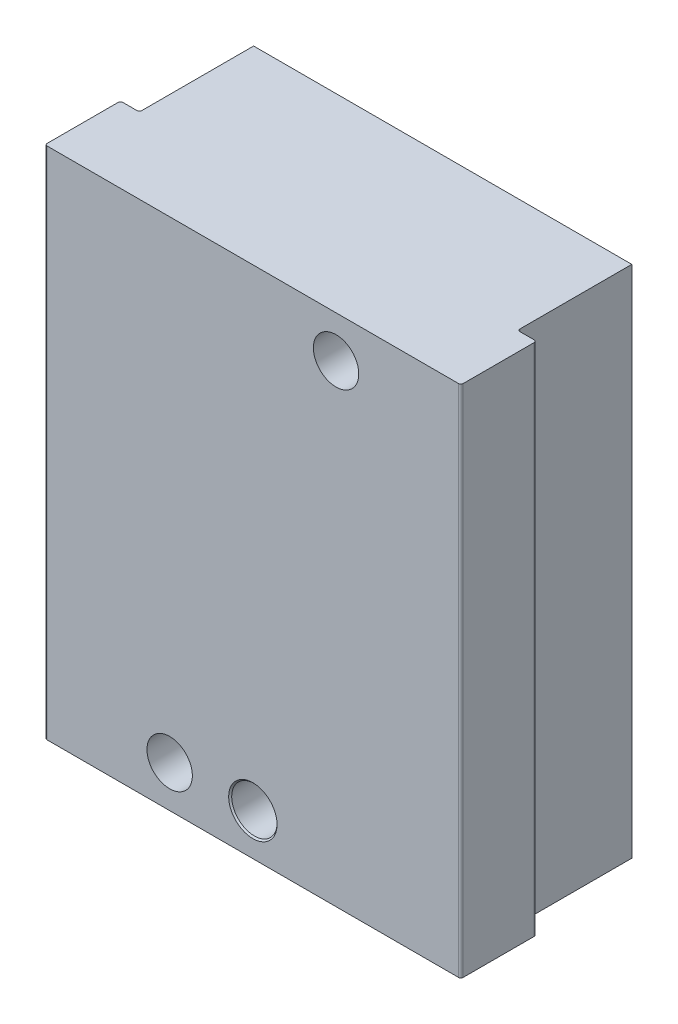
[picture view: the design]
ISO-10303-21;
HEADER;
FILE_DESCRIPTION(('STEP AP214'),'2;1');
FILE_NAME('part.step','',(''),(''),'','','');
FILE_SCHEMA(('AUTOMOTIVE_DESIGN { 1 0 10303 214 1 1 1 1 }'));
ENDSEC;
DATA;
#1=APPLICATION_CONTEXT('core data for automotive mechanical design processes');
#2=APPLICATION_PROTOCOL_DEFINITION('international standard','automotive_design',2000,#1);
#3=PRODUCT_CONTEXT('',#1,'mechanical');
#4=PRODUCT('Part','Part','',(#3));
#5=PRODUCT_RELATED_PRODUCT_CATEGORY('part','',(#4));
#6=PRODUCT_DEFINITION_FORMATION('','',#4);
#7=PRODUCT_DEFINITION_CONTEXT('part definition',#1,'design');
#8=PRODUCT_DEFINITION('design','',#6,#7);
#9=PRODUCT_DEFINITION_SHAPE('','',#8);
#10=(LENGTH_UNIT() NAMED_UNIT(*) SI_UNIT(.MILLI.,.METRE.));
#11=(NAMED_UNIT(*) PLANE_ANGLE_UNIT() SI_UNIT($,.RADIAN.));
#12=(NAMED_UNIT(*) SI_UNIT($,.STERADIAN.) SOLID_ANGLE_UNIT());
#13=UNCERTAINTY_MEASURE_WITH_UNIT(LENGTH_MEASURE(1.E-05),#10,'distance_accuracy_value','');
#14=(GEOMETRIC_REPRESENTATION_CONTEXT(3) GLOBAL_UNCERTAINTY_ASSIGNED_CONTEXT((#13)) GLOBAL_UNIT_ASSIGNED_CONTEXT((#10,
#11,#12)) REPRESENTATION_CONTEXT('',''));
#15=CARTESIAN_POINT('',(0.,0.,0.));
#16=DIRECTION('',(0.,0.,1.));
#17=DIRECTION('',(1.,0.,0.));
#18=AXIS2_PLACEMENT_3D('',#15,#16,#17);
#19=CARTESIAN_POINT('',(-27.0049800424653,-47.5378154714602,-43.689241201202));
#20=DIRECTION('',(0.,0.,-1.));
#21=DIRECTION('',(-1.,0.,0.));
#22=AXIS2_PLACEMENT_3D('',#19,#20,#21);
#23=CYLINDRICAL_SURFACE('',#22,1.5);
#24=CARTESIAN_POINT('',(-28.4999146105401,-47.4146463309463,-66.789241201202));
#25=CARTESIAN_POINT('',(-28.4972110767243,-47.3817342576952,-66.7892330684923));
#26=CARTESIAN_POINT('',(-28.4934051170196,-47.3489165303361,-66.7903240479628));
#27=CARTESIAN_POINT('',(-28.483673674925,-47.2837622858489,-66.7946785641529));
#28=CARTESIAN_POINT('',(-28.477749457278,-47.2514254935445,-66.7979408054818));
#29=CARTESIAN_POINT('',(-28.4639196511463,-47.1877447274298,-66.8065771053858));
#30=CARTESIAN_POINT('',(-28.4560305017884,-47.1563948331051,-66.8119338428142));
#31=CARTESIAN_POINT('',(-28.4383822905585,-47.0946558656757,-66.8246760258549));
#32=CARTESIAN_POINT('',(-28.4286230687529,-47.0642668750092,-66.8320616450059));
#33=CARTESIAN_POINT('',(-28.3968080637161,-46.9749749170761,-66.8570731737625));
#34=CARTESIAN_POINT('',(-28.3721724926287,-46.9177568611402,-66.8775803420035));
#35=CARTESIAN_POINT('',(-28.3174044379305,-46.8089287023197,-66.9251452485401));
#36=CARTESIAN_POINT('',(-28.2872611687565,-46.7573299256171,-66.9522158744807));
#37=CARTESIAN_POINT('',(-28.209920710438,-46.6407227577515,-67.0235740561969));
#38=CARTESIAN_POINT('',(-28.1607244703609,-46.5786047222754,-67.0704173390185));
#39=CARTESIAN_POINT('',(-28.0570787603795,-46.4659110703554,-67.1715633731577));
#40=CARTESIAN_POINT('',(-28.002617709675,-46.4153617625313,-67.2258826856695));
#41=CARTESIAN_POINT('',(-27.8644724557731,-46.3039609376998,-67.3660541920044));
#42=CARTESIAN_POINT('',(-27.7789289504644,-46.249169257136,-67.4548650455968));
#43=CARTESIAN_POINT('',(-27.6045173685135,-46.1593404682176,-67.6387878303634));
#44=CARTESIAN_POINT('',(-27.5156456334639,-46.1243258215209,-67.7339067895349));
#45=CARTESIAN_POINT('',(-27.3572407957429,-46.0780080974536,-67.9049248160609));
#46=CARTESIAN_POINT('',(-27.2880051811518,-46.063088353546,-67.9801625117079));
#47=CARTESIAN_POINT('',(-27.1492344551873,-46.0431264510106,-68.1314555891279));
#48=CARTESIAN_POINT('',(-27.0797001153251,-46.0380664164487,-68.2075092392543));
#49=CARTESIAN_POINT('',(-27.0084643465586,-46.0378185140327,-68.2854299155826));
#50=CARTESIAN_POINT('',(-27.0067221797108,-46.0378154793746,-68.2873355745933));
#51=CARTESIAN_POINT('',(-27.0049800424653,-46.0378154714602,-68.289241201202));
#52=B_SPLINE_CURVE_WITH_KNOTS('',3,(#24,#25,#26,#27,#28,#29,#30,#31,#32,#33,#34,#35,#36,#37,#38,
#39,#40,#41,#42,#43,#44,#45,#46,#47,#48,#49,#50,#51),.UNSPECIFIED.,.F.,.F.,(4,2,2,2,2,2,2,2,2,2,
2,2,2,4),(0.,0.099026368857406,0.197993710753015,0.296159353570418,0.394333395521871,
0.590099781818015,0.786253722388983,1.0608579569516,1.33608060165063,1.73868272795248,
2.14174119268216,2.45127871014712,2.76025450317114,2.76800047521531),.UNSPECIFIED.);
#53=CARTESIAN_POINT('',(-28.4999146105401,-47.4146463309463,-66.789241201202));
#54=VERTEX_POINT('',#53);
#55=CARTESIAN_POINT('',(-27.0049800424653,-46.0378154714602,-68.289241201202));
#56=VERTEX_POINT('',#55);
#57=EDGE_CURVE('E1026',#54,#56,#52,.T.);
#58=ORIENTED_EDGE('',*,*,#57,.T.);
#59=CARTESIAN_POINT('',(-25.5100454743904,-47.4146463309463,-66.789241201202));
#60=CARTESIAN_POINT('',(-25.5127490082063,-47.3817342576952,-66.7892330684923));
#61=CARTESIAN_POINT('',(-25.516554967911,-47.3489165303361,-66.7903240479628));
#62=CARTESIAN_POINT('',(-25.5262864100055,-47.2837622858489,-66.7946785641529));
#63=CARTESIAN_POINT('',(-25.5322106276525,-47.2514254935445,-66.7979408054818));
#64=CARTESIAN_POINT('',(-25.5460404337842,-47.1877447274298,-66.8065771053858));
#65=CARTESIAN_POINT('',(-25.5539295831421,-47.1563948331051,-66.8119338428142));
#66=CARTESIAN_POINT('',(-25.571577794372,-47.0946558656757,-66.8246760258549));
#67=CARTESIAN_POINT('',(-25.5813370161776,-47.0642668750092,-66.8320616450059));
#68=CARTESIAN_POINT('',(-25.6131520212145,-46.9749749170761,-66.8570731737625));
#69=CARTESIAN_POINT('',(-25.6377875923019,-46.9177568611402,-66.8775803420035));
#70=CARTESIAN_POINT('',(-25.692555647,-46.8089287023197,-66.9251452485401));
#71=CARTESIAN_POINT('',(-25.722698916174,-46.7573299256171,-66.9522158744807));
#72=CARTESIAN_POINT('',(-25.8000393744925,-46.6407227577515,-67.0235740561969));
#73=CARTESIAN_POINT('',(-25.8492356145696,-46.5786047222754,-67.0704173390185));
#74=CARTESIAN_POINT('',(-25.952881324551,-46.4659110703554,-67.1715633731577));
#75=CARTESIAN_POINT('',(-26.0073423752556,-46.4153617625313,-67.2258826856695));
#76=CARTESIAN_POINT('',(-26.1454876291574,-46.3039609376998,-67.3660541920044));
#77=CARTESIAN_POINT('',(-26.2310311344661,-46.249169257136,-67.4548650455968));
#78=CARTESIAN_POINT('',(-26.405442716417,-46.1593404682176,-67.6387878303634));
#79=CARTESIAN_POINT('',(-26.4943144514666,-46.1243258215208,-67.7339067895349));
#80=CARTESIAN_POINT('',(-26.6527192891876,-46.0780080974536,-67.9049248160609));
#81=CARTESIAN_POINT('',(-26.7219549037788,-46.063088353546,-67.9801625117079));
#82=CARTESIAN_POINT('',(-26.8607256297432,-46.0431264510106,-68.1314555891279));
#83=CARTESIAN_POINT('',(-26.9302599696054,-46.0380664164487,-68.2075092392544));
#84=CARTESIAN_POINT('',(-27.0014957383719,-46.0378185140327,-68.2854299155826));
#85=CARTESIAN_POINT('',(-27.0032379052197,-46.0378154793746,-68.2873355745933));
#86=CARTESIAN_POINT('',(-27.0049800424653,-46.0378154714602,-68.289241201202));
#87=B_SPLINE_CURVE_WITH_KNOTS('',3,(#59,#60,#61,#62,#63,#64,#65,#66,#67,#68,#69,#70,#71,#72,#73,
#74,#75,#76,#77,#78,#79,#80,#81,#82,#83,#84,#85,#86),.UNSPECIFIED.,.F.,.F.,(4,2,2,2,2,2,2,2,2,2,
2,2,2,4),(0.,0.099026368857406,0.197993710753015,0.296159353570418,0.394333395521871,
0.590099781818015,0.786253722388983,1.06085795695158,1.33608060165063,1.7386827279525,
2.14174119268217,2.45127871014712,2.76025450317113,2.76800047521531),.UNSPECIFIED.);
#88=CARTESIAN_POINT('',(-25.5100454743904,-47.4146463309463,-66.789241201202));
#89=VERTEX_POINT('',#88);
#90=EDGE_CURVE('E1060',#56,#89,#87,.F.);
#91=ORIENTED_EDGE('',*,*,#90,.T.);
#92=CARTESIAN_POINT('',(-25.5100454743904,-47.4146463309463,-66.789241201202));
#93=CARTESIAN_POINT('',(-25.5072231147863,-47.4487981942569,-66.7892334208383));
#94=CARTESIAN_POINT('',(-25.5055885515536,-47.483038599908,-66.7904073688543));
#95=CARTESIAN_POINT('',(-25.5046547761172,-47.5513686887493,-66.7950174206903));
#96=CARTESIAN_POINT('',(-25.5053534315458,-47.5854584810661,-66.7984514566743));
#97=CARTESIAN_POINT('',(-25.5090251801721,-47.6529351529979,-66.8074423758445));
#98=CARTESIAN_POINT('',(-25.511978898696,-47.6863255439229,-66.8129809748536));
#99=CARTESIAN_POINT('',(-25.5200410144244,-47.7524477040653,-66.8260400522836));
#100=CARTESIAN_POINT('',(-25.5251498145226,-47.7851793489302,-66.8335609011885));
#101=CARTESIAN_POINT('',(-25.5434958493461,-47.8818249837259,-66.8588079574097));
#102=CARTESIAN_POINT('',(-25.5597706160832,-47.9444872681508,-66.8792604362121));
#103=CARTESIAN_POINT('',(-25.5993224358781,-48.0652514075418,-66.9261517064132));
#104=CARTESIAN_POINT('',(-25.6226162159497,-48.1233419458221,-66.9526047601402));
#105=CARTESIAN_POINT('',(-25.6855078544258,-48.2563882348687,-67.0217805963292));
#106=CARTESIAN_POINT('',(-25.7279038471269,-48.3288406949,-67.0667861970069));
#107=CARTESIAN_POINT('',(-25.8213452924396,-48.4628618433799,-67.1634416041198));
#108=CARTESIAN_POINT('',(-25.8724040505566,-48.5244134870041,-67.2151016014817));
#109=CARTESIAN_POINT('',(-25.9984156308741,-48.6547154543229,-67.3404775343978));
#110=CARTESIAN_POINT('',(-26.0757786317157,-48.7194390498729,-67.4159519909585));
#111=CARTESIAN_POINT('',(-26.2380110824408,-48.8306627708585,-67.5720731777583));
#112=CARTESIAN_POINT('',(-26.3228915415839,-48.8771356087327,-67.6527274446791));
#113=CARTESIAN_POINT('',(-26.5047543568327,-48.9557039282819,-67.8241245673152));
#114=CARTESIAN_POINT('',(-26.6021508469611,-48.9862296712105,-67.9151402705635));
#115=CARTESIAN_POINT('',(-26.7993600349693,-49.0270516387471,-68.0986670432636));
#116=CARTESIAN_POINT('',(-26.8991664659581,-49.0373955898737,-68.1911740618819));
#117=CARTESIAN_POINT('',(-27.0008934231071,-49.0378112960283,-68.2854537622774));
#118=CARTESIAN_POINT('',(-27.0029367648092,-49.0378154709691,-68.2873475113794));
#119=CARTESIAN_POINT('',(-27.0049800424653,-49.0378154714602,-68.289241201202));
#120=B_SPLINE_CURVE_WITH_KNOTS('',3,(#92,#93,#94,#95,#96,#97,#98,#99,#100,#101,#102,#103,#104,
#105,#106,#107,#108,#109,#110,#111,#112,#113,#114,#115,#116,#117,#118,#119),.UNSPECIFIED.,.F.,
.F.,(4,2,2,2,2,2,2,2,2,2,2,2,2,4),(0.,0.102749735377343,0.20540559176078,0.307189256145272,
0.408991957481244,0.611706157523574,0.814907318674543,1.09907841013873,1.38368999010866,
1.75961926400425,2.13610848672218,2.54480013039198,2.95252411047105,2.96088196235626),.UNSPECIFIED.);
#121=CARTESIAN_POINT('',(-27.0049800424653,-49.0378154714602,-68.289241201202));
#122=VERTEX_POINT('',#121);
#123=EDGE_CURVE('E1066',#89,#122,#120,.T.);
#124=ORIENTED_EDGE('',*,*,#123,.T.);
#125=CARTESIAN_POINT('',(-28.4999146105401,-47.4146463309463,-66.789241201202));
#126=CARTESIAN_POINT('',(-28.5027369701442,-47.4487981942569,-66.7892334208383));
#127=CARTESIAN_POINT('',(-28.5043715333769,-47.483038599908,-66.7904073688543));
#128=CARTESIAN_POINT('',(-28.5053053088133,-47.5513686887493,-66.7950174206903));
#129=CARTESIAN_POINT('',(-28.5046066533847,-47.5854584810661,-66.7984514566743));
#130=CARTESIAN_POINT('',(-28.5009349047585,-47.6529351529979,-66.8074423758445));
#131=CARTESIAN_POINT('',(-28.4979811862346,-47.6863255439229,-66.8129809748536));
#132=CARTESIAN_POINT('',(-28.4899190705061,-47.7524477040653,-66.8260400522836));
#133=CARTESIAN_POINT('',(-28.4848102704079,-47.7851793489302,-66.8335609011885));
#134=CARTESIAN_POINT('',(-28.4664642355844,-47.8818249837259,-66.8588079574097));
#135=CARTESIAN_POINT('',(-28.4501894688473,-47.9444872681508,-66.8792604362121));
#136=CARTESIAN_POINT('',(-28.4106376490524,-48.0652514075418,-66.9261517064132));
#137=CARTESIAN_POINT('',(-28.3873438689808,-48.1233419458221,-66.9526047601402));
#138=CARTESIAN_POINT('',(-28.3244522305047,-48.2563882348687,-67.0217805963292));
#139=CARTESIAN_POINT('',(-28.2820562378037,-48.3288406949,-67.0667861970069));
#140=CARTESIAN_POINT('',(-28.1886147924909,-48.4628618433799,-67.1634416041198));
#141=CARTESIAN_POINT('',(-28.1375560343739,-48.5244134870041,-67.2151016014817));
#142=CARTESIAN_POINT('',(-28.0115444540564,-48.6547154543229,-67.3404775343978));
#143=CARTESIAN_POINT('',(-27.9341814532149,-48.7194390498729,-67.4159519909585));
#144=CARTESIAN_POINT('',(-27.7719490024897,-48.8306627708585,-67.5720731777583));
#145=CARTESIAN_POINT('',(-27.6870685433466,-48.8771356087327,-67.6527274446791));
#146=CARTESIAN_POINT('',(-27.5052057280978,-48.9557039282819,-67.8241245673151));
#147=CARTESIAN_POINT('',(-27.4078092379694,-48.9862296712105,-67.9151402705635));
#148=CARTESIAN_POINT('',(-27.2106000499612,-49.027051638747,-68.0986670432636));
#149=CARTESIAN_POINT('',(-27.1107936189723,-49.0373955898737,-68.1911740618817));
#150=CARTESIAN_POINT('',(-27.0090666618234,-49.0378112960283,-68.2854537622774));
#151=CARTESIAN_POINT('',(-27.0070233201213,-49.0378154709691,-68.2873475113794));
#152=CARTESIAN_POINT('',(-27.0049800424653,-49.0378154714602,-68.289241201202));
#153=B_SPLINE_CURVE_WITH_KNOTS('',3,(#125,#126,#127,#128,#129,#130,#131,#132,#133,#134,#135,
#136,#137,#138,#139,#140,#141,#142,#143,#144,#145,#146,#147,#148,#149,#150,#151,#152),
.UNSPECIFIED.,.F.,.F.,(4,2,2,2,2,2,2,2,2,2,2,2,2,4),(0.,0.102749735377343,0.20540559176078,
0.307189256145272,0.408991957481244,0.611706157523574,0.814907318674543,1.09907841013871,
1.38368999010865,1.75961926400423,2.13610848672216,2.54480013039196,2.95252411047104,
2.96088196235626),.UNSPECIFIED.);
#154=EDGE_CURVE('E1034',#122,#54,#153,.F.);
#155=ORIENTED_EDGE('',*,*,#154,.T.);
#156=EDGE_LOOP('',(#58,#91,#124,#155));
#157=FACE_BOUND('',#156,.T.);
#158=CARTESIAN_POINT('',(-27.0049800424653,-47.5378154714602,-53.689241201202));
#159=DIRECTION('',(0.,0.,1.));
#160=DIRECTION('',(1.,0.,0.));
#161=AXIS2_PLACEMENT_3D('',#158,#159,#160);
#162=CIRCLE('',#161,1.5);
#163=CARTESIAN_POINT('',(-25.5049800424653,-47.5378154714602,-53.689241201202));
#164=VERTEX_POINT('',#163);
#165=EDGE_CURVE('E754',#164,#164,#162,.F.);
#166=ORIENTED_EDGE('',*,*,#165,.F.);
#167=EDGE_LOOP('',(#166));
#168=FACE_BOUND('',#167,.T.);
#169=ADVANCED_FACE('F36',(#157,#168),#23,.F.);
#170=CARTESIAN_POINT('',(0.495019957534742,14.9621845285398,-53.689241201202));
#171=DIRECTION('',(-1.,0.,0.));
#172=DIRECTION('',(0.,0.,1.));
#173=AXIS2_PLACEMENT_3D('',#170,#171,#172);
#174=PLANE('',#173);
#175=DIRECTION('',(0.,0.,-1.));
#176=VECTOR('',#175,1.);
#177=CARTESIAN_POINT('',(0.495019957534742,-53.0378154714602,-53.689241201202));
#178=LINE('',#177,#176);
#179=CARTESIAN_POINT('',(0.495019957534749,-53.0378154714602,-43.989241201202));
#180=VERTEX_POINT('',#179);
#181=CARTESIAN_POINT('',(0.495019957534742,-53.0378154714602,-53.389241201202));
#182=VERTEX_POINT('',#181);
#183=EDGE_CURVE('E765',#180,#182,#178,.T.);
#184=ORIENTED_EDGE('',*,*,#183,.T.);
#185=DIRECTION('',(0.,-1.,0.));
#186=VECTOR('',#185,1.);
#187=CARTESIAN_POINT('',(0.495019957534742,14.9621845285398,-53.389241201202));
#188=LINE('',#187,#186);
#189=CARTESIAN_POINT('',(0.495019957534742,14.9621845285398,-53.389241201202));
#190=VERTEX_POINT('',#189);
#191=EDGE_CURVE('E833',#182,#190,#188,.F.);
#192=ORIENTED_EDGE('',*,*,#191,.T.);
#193=DIRECTION('',(0.,0.,-1.));
#194=VECTOR('',#193,1.);
#195=CARTESIAN_POINT('',(0.495019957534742,14.9621845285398,-53.689241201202));
#196=LINE('',#195,#194);
#197=CARTESIAN_POINT('',(0.495019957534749,14.9621845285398,-43.989241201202));
#198=VERTEX_POINT('',#197);
#199=EDGE_CURVE('E768',#198,#190,#196,.T.);
#200=ORIENTED_EDGE('',*,*,#199,.F.);
#201=DIRECTION('',(0.,-1.,0.));
#202=VECTOR('',#201,1.);
#203=CARTESIAN_POINT('',(0.495019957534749,14.9621845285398,-43.989241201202));
#204=LINE('',#203,#202);
#205=EDGE_CURVE('E830',#198,#180,#204,.T.);
#206=ORIENTED_EDGE('',*,*,#205,.T.);
#207=EDGE_LOOP('',(#184,#192,#200,#206));
#208=FACE_BOUND('',#207,.T.);
#209=ADVANCED_FACE('F1267',(#208),#174,.F.);
#210=CARTESIAN_POINT('',(0.495019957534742,14.9621845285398,-53.689241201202));
#211=DIRECTION('',(0.,0.,1.));
#212=DIRECTION('',(1.,0.,0.));
#213=AXIS2_PLACEMENT_3D('',#210,#211,#212);
#214=PLANE('',#213);
#215=DIRECTION('',(-1.,0.,0.));
#216=VECTOR('',#215,1.);
#217=CARTESIAN_POINT('',(0.495019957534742,14.9621845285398,-53.689241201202));
#218=LINE('',#217,#216);
#219=CARTESIAN_POINT('',(0.19501995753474,14.9621845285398,-53.689241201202));
#220=VERTEX_POINT('',#219);
#221=CARTESIAN_POINT('',(-1.70498004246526,14.9621845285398,-53.689241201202));
#222=VERTEX_POINT('',#221);
#223=EDGE_CURVE('E771',#220,#222,#218,.T.);
#224=ORIENTED_EDGE('',*,*,#223,.F.);
#225=DIRECTION('',(0.,-1.,0.));
#226=VECTOR('',#225,1.);
#227=CARTESIAN_POINT('',(0.19501995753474,14.9621845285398,-53.689241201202));
#228=LINE('',#227,#226);
#229=CARTESIAN_POINT('',(0.19501995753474,-53.0378154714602,-53.689241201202));
#230=VERTEX_POINT('',#229);
#231=EDGE_CURVE('E819',#220,#230,#228,.T.);
#232=ORIENTED_EDGE('',*,*,#231,.T.);
#233=DIRECTION('',(-1.,0.,0.));
#234=VECTOR('',#233,1.);
#235=CARTESIAN_POINT('',(0.495019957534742,-53.0378154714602,-53.689241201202));
#236=LINE('',#235,#234);
#237=CARTESIAN_POINT('',(-1.70498004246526,-53.0378154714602,-53.689241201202));
#238=VERTEX_POINT('',#237);
#239=EDGE_CURVE('E794',#230,#238,#236,.T.);
#240=ORIENTED_EDGE('',*,*,#239,.T.);
#241=DIRECTION('',(0.,-1.,0.));
#242=VECTOR('',#241,1.);
#243=CARTESIAN_POINT('',(-1.70498004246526,14.9621845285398,-53.689241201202));
#244=LINE('',#243,#242);
#245=EDGE_CURVE('E817',#238,#222,#244,.F.);
#246=ORIENTED_EDGE('',*,*,#245,.T.);
#247=EDGE_LOOP('',(#224,#232,#240,#246));
#248=FACE_BOUND('',#247,.T.);
#249=ADVANCED_FACE('F1271',(#248),#214,.F.);
#250=CARTESIAN_POINT('',(-2.00498004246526,14.9621845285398,-68.789241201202));
#251=DIRECTION('',(-1.,0.,0.));
#252=DIRECTION('',(0.,0.,1.));
#253=AXIS2_PLACEMENT_3D('',#250,#251,#252);
#254=PLANE('',#253);
#255=DIRECTION('',(0.,0.,-1.));
#256=VECTOR('',#255,1.);
#257=CARTESIAN_POINT('',(-2.00498004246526,14.9621845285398,-68.789241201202));
#258=LINE('',#257,#256);
#259=CARTESIAN_POINT('',(-2.00498004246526,14.9621845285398,-53.989241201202));
#260=VERTEX_POINT('',#259);
#261=CARTESIAN_POINT('',(-2.00498004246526,14.9621845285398,-68.789241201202));
#262=VERTEX_POINT('',#261);
#263=EDGE_CURVE('E775',#260,#262,#258,.T.);
#264=ORIENTED_EDGE('',*,*,#263,.F.);
#265=DIRECTION('',(0.,-1.,0.));
#266=VECTOR('',#265,1.);
#267=CARTESIAN_POINT('',(-2.00498004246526,-53.0378154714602,-53.989241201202));
#268=LINE('',#267,#266);
#269=CARTESIAN_POINT('',(-2.00498004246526,-53.0378154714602,-53.989241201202));
#270=VERTEX_POINT('',#269);
#271=EDGE_CURVE('E843',#260,#270,#268,.T.);
#272=ORIENTED_EDGE('',*,*,#271,.T.);
#273=DIRECTION('',(0.,0.,-1.));
#274=VECTOR('',#273,1.);
#275=CARTESIAN_POINT('',(-2.00498004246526,-53.0378154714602,-68.789241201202));
#276=LINE('',#275,#274);
#277=CARTESIAN_POINT('',(-2.00498004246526,-53.0378154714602,-68.789241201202));
#278=VERTEX_POINT('',#277);
#279=EDGE_CURVE('E797',#270,#278,#276,.T.);
#280=ORIENTED_EDGE('',*,*,#279,.T.);
#281=DIRECTION('',(0.,-1.,0.));
#282=VECTOR('',#281,1.);
#283=CARTESIAN_POINT('',(-2.00498004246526,14.9621845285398,-68.789241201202));
#284=LINE('',#283,#282);
#285=EDGE_CURVE('E814',#262,#278,#284,.T.);
#286=ORIENTED_EDGE('',*,*,#285,.F.);
#287=EDGE_LOOP('',(#264,#272,#280,#286));
#288=FACE_BOUND('',#287,.T.);
#289=ADVANCED_FACE('F1277',(#288),#254,.F.);
#290=CARTESIAN_POINT('',(-52.0049800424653,14.9621845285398,-68.789241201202));
#291=DIRECTION('',(0.,0.,1.));
#292=DIRECTION('',(1.,0.,0.));
#293=AXIS2_PLACEMENT_3D('',#290,#291,#292);
#294=PLANE('',#293);
#295=CARTESIAN_POINT('',(-34.9583645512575,-42.8950959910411,-68.789241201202));
#296=DIRECTION('',(0.,0.,1.));
#297=DIRECTION('',(1.,0.,0.));
#298=AXIS2_PLACEMENT_3D('',#295,#296,#297);
#299=CIRCLE('',#298,1.5);
#300=CARTESIAN_POINT('',(-33.6522158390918,-42.1575490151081,-68.789241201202));
#301=VERTEX_POINT('',#300);
#302=CARTESIAN_POINT('',(-35.1102008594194,-41.4028005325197,-68.789241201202));
#303=VERTEX_POINT('',#302);
#304=EDGE_CURVE('E995',#301,#303,#299,.T.);
#305=ORIENTED_EDGE('',*,*,#304,.T.);
#306=DIRECTION('',(0.,-1.,0.));
#307=VECTOR('',#306,1.);
#308=CARTESIAN_POINT('',(-35.1102008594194,-42.0812232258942,-68.789241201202));
#309=LINE('',#308,#307);
#310=CARTESIAN_POINT('',(-35.1102008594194,-40.5628154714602,-68.789241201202));
#311=VERTEX_POINT('',#310);
#312=EDGE_CURVE('E1136',#311,#303,#309,.T.);
#313=ORIENTED_EDGE('',*,*,#312,.F.);
#314=DIRECTION('',(-1.,0.,0.));
#315=VECTOR('',#314,1.);
#316=CARTESIAN_POINT('',(-52.0049800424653,-40.5628154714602,-68.789241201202));
#317=LINE('',#316,#315);
#318=CARTESIAN_POINT('',(-34.9299800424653,-40.5628154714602,-68.789241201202));
#319=VERTEX_POINT('',#318);
#320=EDGE_CURVE('E513',#319,#311,#317,.T.);
#321=ORIENTED_EDGE('',*,*,#320,.F.);
#322=CARTESIAN_POINT('',(-34.9299800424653,-38.5128154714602,-68.789241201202));
#323=DIRECTION('',(0.,0.,1.));
#324=DIRECTION('',(1.,0.,0.));
#325=AXIS2_PLACEMENT_3D('',#322,#323,#324);
#326=CIRCLE('',#325,2.05);
#327=CARTESIAN_POINT('',(-32.8799800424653,-38.5128154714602,-68.789241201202));
#328=VERTEX_POINT('',#327);
#329=EDGE_CURVE('E966',#319,#328,#326,.T.);
#330=ORIENTED_EDGE('',*,*,#329,.T.);
#331=DIRECTION('',(0.,-1.,0.));
#332=VECTOR('',#331,1.);
#333=CARTESIAN_POINT('',(-32.8799800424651,14.9621845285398,-68.789241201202));
#334=LINE('',#333,#332);
#335=CARTESIAN_POINT('',(-32.8799800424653,-34.1140252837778,-68.789241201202));
#336=VERTEX_POINT('',#335);
#337=EDGE_CURVE('E964',#336,#328,#334,.T.);
#338=ORIENTED_EDGE('',*,*,#337,.F.);
#339=CARTESIAN_POINT('',(-34.9299800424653,-34.1140252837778,-68.789241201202));
#340=DIRECTION('',(0.,0.,1.));
#341=DIRECTION('',(1.,0.,0.));
#342=AXIS2_PLACEMENT_3D('',#339,#340,#341);
#343=CIRCLE('',#342,2.05);
#344=CARTESIAN_POINT('',(-33.2899800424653,-32.8840252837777,-68.789241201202));
#345=VERTEX_POINT('',#344);
#346=EDGE_CURVE('E959',#336,#345,#343,.T.);
#347=ORIENTED_EDGE('',*,*,#346,.T.);
#348=CARTESIAN_POINT('',(-26.7299800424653,-27.9640252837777,-68.789241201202));
#349=DIRECTION('',(0.,0.,1.));
#350=DIRECTION('',(1.,0.,0.));
#351=AXIS2_PLACEMENT_3D('',#348,#349,#350);
#352=CIRCLE('',#351,8.2);
#353=CARTESIAN_POINT('',(-34.9299800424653,-27.9640252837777,-68.789241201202));
#354=VERTEX_POINT('',#353);
#355=EDGE_CURVE('E953',#354,#345,#352,.T.);
#356=ORIENTED_EDGE('',*,*,#355,.F.);
#357=DIRECTION('',(0.,-1.,0.));
#358=VECTOR('',#357,1.);
#359=CARTESIAN_POINT('',(-34.9299800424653,14.9621845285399,-68.789241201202));
#360=LINE('',#359,#358);
#361=CARTESIAN_POINT('',(-34.9299800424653,-10.1116056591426,-68.789241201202));
#362=VERTEX_POINT('',#361);
#363=EDGE_CURVE('E948',#362,#354,#360,.T.);
#364=ORIENTED_EDGE('',*,*,#363,.F.);
#365=CARTESIAN_POINT('',(-26.7299800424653,-10.1116056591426,-68.789241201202));
#366=DIRECTION('',(0.,0.,1.));
#367=DIRECTION('',(1.,0.,0.));
#368=AXIS2_PLACEMENT_3D('',#365,#366,#367);
#369=CIRCLE('',#368,8.2);
#370=CARTESIAN_POINT('',(-33.2899800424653,-5.19160565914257,-68.789241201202));
#371=VERTEX_POINT('',#370);
#372=EDGE_CURVE('E944',#371,#362,#369,.T.);
#373=ORIENTED_EDGE('',*,*,#372,.F.);
#374=CARTESIAN_POINT('',(-34.9299800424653,-3.96160565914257,-68.789241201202));
#375=DIRECTION('',(0.,0.,1.));
#376=DIRECTION('',(1.,0.,0.));
#377=AXIS2_PLACEMENT_3D('',#374,#375,#376);
#378=CIRCLE('',#377,2.05);
#379=CARTESIAN_POINT('',(-32.8799800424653,-3.96160565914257,-68.789241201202));
#380=VERTEX_POINT('',#379);
#381=EDGE_CURVE('E938',#371,#380,#378,.T.);
#382=ORIENTED_EDGE('',*,*,#381,.T.);
#383=DIRECTION('',(0.,-1.,0.));
#384=VECTOR('',#383,1.);
#385=CARTESIAN_POINT('',(-32.8799800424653,14.9621845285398,-68.789241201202));
#386=LINE('',#385,#384);
#387=CARTESIAN_POINT('',(-32.8799800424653,0.437184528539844,-68.789241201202));
#388=VERTEX_POINT('',#387);
#389=EDGE_CURVE('E936',#388,#380,#386,.T.);
#390=ORIENTED_EDGE('',*,*,#389,.F.);
#391=CARTESIAN_POINT('',(-34.9299800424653,0.437184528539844,-68.789241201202));
#392=DIRECTION('',(0.,0.,1.));
#393=DIRECTION('',(1.,0.,0.));
#394=AXIS2_PLACEMENT_3D('',#391,#392,#393);
#395=CIRCLE('',#394,2.05);
#396=CARTESIAN_POINT('',(-34.9299800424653,2.48718452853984,-68.789241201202));
#397=VERTEX_POINT('',#396);
#398=EDGE_CURVE('E930',#388,#397,#395,.T.);
#399=ORIENTED_EDGE('',*,*,#398,.T.);
#400=DIRECTION('',(1.,0.,0.));
#401=VECTOR('',#400,1.);
#402=CARTESIAN_POINT('',(-52.0049800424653,2.48718452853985,-68.789241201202));
#403=LINE('',#402,#401);
#404=CARTESIAN_POINT('',(-41.0799800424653,2.48718452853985,-68.789241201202));
#405=VERTEX_POINT('',#404);
#406=EDGE_CURVE('E933',#405,#397,#403,.T.);
#407=ORIENTED_EDGE('',*,*,#406,.F.);
#408=CARTESIAN_POINT('',(-41.0799800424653,0.437184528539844,-68.789241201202));
#409=DIRECTION('',(0.,0.,1.));
#410=DIRECTION('',(1.,0.,0.));
#411=AXIS2_PLACEMENT_3D('',#408,#409,#410);
#412=CIRCLE('',#411,2.05);
#413=CARTESIAN_POINT('',(-43.1299800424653,0.437184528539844,-68.789241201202));
#414=VERTEX_POINT('',#413);
#415=EDGE_CURVE('E941',#405,#414,#412,.T.);
#416=ORIENTED_EDGE('',*,*,#415,.T.);
#417=DIRECTION('',(0.,1.,0.));
#418=VECTOR('',#417,1.);
#419=CARTESIAN_POINT('',(-43.1299800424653,14.9621845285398,-68.789241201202));
#420=LINE('',#419,#418);
#421=CARTESIAN_POINT('',(-43.1299800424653,-3.96160565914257,-68.789241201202));
#422=VERTEX_POINT('',#421);
#423=EDGE_CURVE('E946',#422,#414,#420,.T.);
#424=ORIENTED_EDGE('',*,*,#423,.F.);
#425=CARTESIAN_POINT('',(-41.0799800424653,-3.96160565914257,-68.789241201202));
#426=DIRECTION('',(0.,0.,1.));
#427=DIRECTION('',(1.,0.,0.));
#428=AXIS2_PLACEMENT_3D('',#425,#426,#427);
#429=CIRCLE('',#428,2.05);
#430=CARTESIAN_POINT('',(-42.7199800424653,-5.19160565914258,-68.789241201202));
#431=VERTEX_POINT('',#430);
#432=EDGE_CURVE('E950',#422,#431,#429,.T.);
#433=ORIENTED_EDGE('',*,*,#432,.T.);
#434=CARTESIAN_POINT('',(-49.2799800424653,-10.1116056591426,-68.789241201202));
#435=DIRECTION('',(0.,0.,1.));
#436=DIRECTION('',(1.,0.,0.));
#437=AXIS2_PLACEMENT_3D('',#434,#435,#436);
#438=CIRCLE('',#437,8.2);
#439=CARTESIAN_POINT('',(-41.0799800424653,-10.1116056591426,-68.789241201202));
#440=VERTEX_POINT('',#439);
#441=EDGE_CURVE('E955',#440,#431,#438,.T.);
#442=ORIENTED_EDGE('',*,*,#441,.F.);
#443=DIRECTION('',(0.,1.,0.));
#444=VECTOR('',#443,1.);
#445=CARTESIAN_POINT('',(-41.0799800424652,14.9621845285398,-68.789241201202));
#446=LINE('',#445,#444);
#447=CARTESIAN_POINT('',(-41.0799800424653,-27.9640252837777,-68.789241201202));
#448=VERTEX_POINT('',#447);
#449=EDGE_CURVE('E957',#448,#440,#446,.T.);
#450=ORIENTED_EDGE('',*,*,#449,.F.);
#451=CARTESIAN_POINT('',(-49.2799800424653,-27.9640252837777,-68.789241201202));
#452=DIRECTION('',(0.,0.,1.));
#453=DIRECTION('',(1.,0.,0.));
#454=AXIS2_PLACEMENT_3D('',#451,#452,#453);
#455=CIRCLE('',#454,8.2);
#456=CARTESIAN_POINT('',(-42.7199800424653,-32.8840252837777,-68.789241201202));
#457=VERTEX_POINT('',#456);
#458=EDGE_CURVE('E962',#457,#448,#455,.T.);
#459=ORIENTED_EDGE('',*,*,#458,.F.);
#460=CARTESIAN_POINT('',(-41.0799800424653,-34.1140252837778,-68.789241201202));
#461=DIRECTION('',(0.,0.,1.));
#462=DIRECTION('',(1.,0.,0.));
#463=AXIS2_PLACEMENT_3D('',#460,#461,#462);
#464=CIRCLE('',#463,2.05);
#465=CARTESIAN_POINT('',(-43.1299800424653,-34.1140252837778,-68.789241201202));
#466=VERTEX_POINT('',#465);
#467=EDGE_CURVE('E969',#457,#466,#464,.T.);
#468=ORIENTED_EDGE('',*,*,#467,.T.);
#469=DIRECTION('',(0.,1.,0.));
#470=VECTOR('',#469,1.);
#471=CARTESIAN_POINT('',(-43.1299800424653,14.9621845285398,-68.789241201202));
#472=LINE('',#471,#470);
#473=CARTESIAN_POINT('',(-43.1299800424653,-38.5128154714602,-68.789241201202));
#474=VERTEX_POINT('',#473);
#475=EDGE_CURVE('E974',#474,#466,#472,.T.);
#476=ORIENTED_EDGE('',*,*,#475,.F.);
#477=CARTESIAN_POINT('',(-41.0799800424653,-38.5128154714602,-68.789241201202));
#478=DIRECTION('',(0.,0.,1.));
#479=DIRECTION('',(1.,0.,0.));
#480=AXIS2_PLACEMENT_3D('',#477,#478,#479);
#481=CIRCLE('',#480,2.05);
#482=CARTESIAN_POINT('',(-41.0799800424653,-40.5628154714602,-68.789241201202));
#483=VERTEX_POINT('',#482);
#484=EDGE_CURVE('E976',#474,#483,#481,.T.);
#485=ORIENTED_EDGE('',*,*,#484,.T.);
#486=CARTESIAN_POINT('',(-35.857329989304,-40.5628154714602,-68.789241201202));
#487=VERTEX_POINT('',#486);
#488=EDGE_CURVE('E972',#487,#483,#317,.T.);
#489=ORIENTED_EDGE('',*,*,#488,.F.);
#490=DIRECTION('',(0.,1.,0.));
#491=VECTOR('',#490,1.);
#492=CARTESIAN_POINT('',(-35.857329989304,-42.0812232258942,-68.789241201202));
#493=LINE('',#492,#491);
#494=CARTESIAN_POINT('',(-35.857329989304,-41.6943207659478,-68.789241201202));
#495=VERTEX_POINT('',#494);
#496=EDGE_CURVE('E507',#495,#487,#493,.T.);
#497=ORIENTED_EDGE('',*,*,#496,.F.);
#498=CARTESIAN_POINT('',(-34.9583645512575,-42.8950959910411,-68.789241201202));
#499=DIRECTION('',(0.,0.,1.));
#500=DIRECTION('',(1.,0.,0.));
#501=AXIS2_PLACEMENT_3D('',#498,#499,#500);
#502=CIRCLE('',#501,1.5);
#503=CARTESIAN_POINT('',(-36.2645132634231,-43.6326429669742,-68.789241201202));
#504=VERTEX_POINT('',#503);
#505=EDGE_CURVE('E998',#495,#504,#502,.T.);
#506=ORIENTED_EDGE('',*,*,#505,.T.);
#507=CARTESIAN_POINT('',(-27.0049800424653,-38.404034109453,-68.789241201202));
#508=DIRECTION('',(0.,0.,1.));
#509=DIRECTION('',(1.,0.,0.));
#510=AXIS2_PLACEMENT_3D('',#507,#508,#509);
#511=CIRCLE('',#510,10.6337813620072);
#512=CARTESIAN_POINT('',(-17.7454468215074,-43.6326429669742,-68.789241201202));
#513=VERTEX_POINT('',#512);
#514=EDGE_CURVE('E982',#504,#513,#511,.T.);
#515=ORIENTED_EDGE('',*,*,#514,.T.);
#516=CARTESIAN_POINT('',(-19.0515955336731,-42.8950959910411,-68.789241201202));
#517=DIRECTION('',(0.,0.,1.));
#518=DIRECTION('',(1.,0.,0.));
#519=AXIS2_PLACEMENT_3D('',#516,#517,#518);
#520=CIRCLE('',#519,1.5);
#521=CARTESIAN_POINT('',(-18.204598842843,-41.6571151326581,-68.7892412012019));
#522=VERTEX_POINT('',#521);
#523=EDGE_CURVE('E1000',#513,#522,#520,.T.);
#524=ORIENTED_EDGE('',*,*,#523,.T.);
#525=DIRECTION('',(-0.412647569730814,-0.910890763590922,0.));
#526=VECTOR('',#525,1.);
#527=CARTESIAN_POINT('',(-18.2617564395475,-41.7832865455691,-68.789241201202));
#528=LINE('',#527,#526);
#529=CARTESIAN_POINT('',(-17.7088642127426,-40.5628154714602,-68.7892412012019));
#530=VERTEX_POINT('',#529);
#531=EDGE_CURVE('E523',#530,#522,#528,.T.);
#532=ORIENTED_EDGE('',*,*,#531,.F.);
#533=DIRECTION('',(-1.,0.,0.));
#534=VECTOR('',#533,1.);
#535=CARTESIAN_POINT('',(-52.0049800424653,-40.5628154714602,-68.789241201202));
#536=LINE('',#535,#534);
#537=CARTESIAN_POINT('',(-12.9299800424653,-40.5628154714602,-68.789241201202));
#538=VERTEX_POINT('',#537);
#539=EDGE_CURVE('E922',#538,#530,#536,.T.);
#540=ORIENTED_EDGE('',*,*,#539,.F.);
#541=CARTESIAN_POINT('',(-12.9299800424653,-38.5128154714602,-68.789241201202));
#542=DIRECTION('',(0.,0.,1.));
#543=DIRECTION('',(1.,0.,0.));
#544=AXIS2_PLACEMENT_3D('',#541,#542,#543);
#545=CIRCLE('',#544,2.05);
#546=CARTESIAN_POINT('',(-10.8799800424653,-38.5128154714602,-68.789241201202));
#547=VERTEX_POINT('',#546);
#548=EDGE_CURVE('E927',#538,#547,#545,.T.);
#549=ORIENTED_EDGE('',*,*,#548,.T.);
#550=DIRECTION('',(0.,-1.,0.));
#551=VECTOR('',#550,1.);
#552=CARTESIAN_POINT('',(-10.8799800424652,14.9621845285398,-68.789241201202));
#553=LINE('',#552,#551);
#554=CARTESIAN_POINT('',(-10.8799800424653,-34.1140252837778,-68.789241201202));
#555=VERTEX_POINT('',#554);
#556=EDGE_CURVE('E925',#555,#547,#553,.T.);
#557=ORIENTED_EDGE('',*,*,#556,.F.);
#558=CARTESIAN_POINT('',(-12.9299800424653,-34.1140252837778,-68.789241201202));
#559=DIRECTION('',(0.,0.,1.));
#560=DIRECTION('',(1.,0.,0.));
#561=AXIS2_PLACEMENT_3D('',#558,#559,#560);
#562=CIRCLE('',#561,2.05);
#563=CARTESIAN_POINT('',(-11.2899800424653,-32.8840252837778,-68.789241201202));
#564=VERTEX_POINT('',#563);
#565=EDGE_CURVE('E918',#555,#564,#562,.T.);
#566=ORIENTED_EDGE('',*,*,#565,.T.);
#567=CARTESIAN_POINT('',(-4.72998004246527,-27.9640252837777,-68.789241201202));
#568=DIRECTION('',(0.,0.,1.));
#569=DIRECTION('',(1.,0.,0.));
#570=AXIS2_PLACEMENT_3D('',#567,#568,#569);
#571=CIRCLE('',#570,8.2);
#572=CARTESIAN_POINT('',(-12.9299800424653,-27.9640252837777,-68.789241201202));
#573=VERTEX_POINT('',#572);
#574=EDGE_CURVE('E911',#573,#564,#571,.T.);
#575=ORIENTED_EDGE('',*,*,#574,.F.);
#576=DIRECTION('',(0.,-1.,0.));
#577=VECTOR('',#576,1.);
#578=CARTESIAN_POINT('',(-12.9299800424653,14.9621845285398,-68.789241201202));
#579=LINE('',#578,#577);
#580=CARTESIAN_POINT('',(-12.9299800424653,-10.1116056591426,-68.789241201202));
#581=VERTEX_POINT('',#580);
#582=EDGE_CURVE('E906',#581,#573,#579,.T.);
#583=ORIENTED_EDGE('',*,*,#582,.F.);
#584=CARTESIAN_POINT('',(-4.72998004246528,-10.1116056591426,-68.789241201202));
#585=DIRECTION('',(0.,0.,1.));
#586=DIRECTION('',(1.,0.,0.));
#587=AXIS2_PLACEMENT_3D('',#584,#585,#586);
#588=CIRCLE('',#587,8.2);
#589=CARTESIAN_POINT('',(-11.2899800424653,-5.19160565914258,-68.789241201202));
#590=VERTEX_POINT('',#589);
#591=EDGE_CURVE('E904',#590,#581,#588,.T.);
#592=ORIENTED_EDGE('',*,*,#591,.F.);
#593=CARTESIAN_POINT('',(-12.9299800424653,-3.96160565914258,-68.789241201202));
#594=DIRECTION('',(0.,0.,1.));
#595=DIRECTION('',(1.,0.,0.));
#596=AXIS2_PLACEMENT_3D('',#593,#594,#595);
#597=CIRCLE('',#596,2.05);
#598=CARTESIAN_POINT('',(-10.8799800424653,-3.96160565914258,-68.789241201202));
#599=VERTEX_POINT('',#598);
#600=EDGE_CURVE('E899',#590,#599,#597,.T.);
#601=ORIENTED_EDGE('',*,*,#600,.T.);
#602=DIRECTION('',(0.,-1.,0.));
#603=VECTOR('',#602,1.);
#604=CARTESIAN_POINT('',(-10.8799800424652,14.9621845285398,-68.789241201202));
#605=LINE('',#604,#603);
#606=CARTESIAN_POINT('',(-10.8799800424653,0.437184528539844,-68.789241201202));
#607=VERTEX_POINT('',#606);
#608=EDGE_CURVE('E895',#607,#599,#605,.T.);
#609=ORIENTED_EDGE('',*,*,#608,.F.);
#610=CARTESIAN_POINT('',(-12.9299800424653,0.437184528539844,-68.789241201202));
#611=DIRECTION('',(0.,0.,1.));
#612=DIRECTION('',(1.,0.,0.));
#613=AXIS2_PLACEMENT_3D('',#610,#611,#612);
#614=CIRCLE('',#613,2.05);
#615=CARTESIAN_POINT('',(-12.9299800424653,2.48718452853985,-68.789241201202));
#616=VERTEX_POINT('',#615);
#617=EDGE_CURVE('E890',#607,#616,#614,.T.);
#618=ORIENTED_EDGE('',*,*,#617,.T.);
#619=DIRECTION('',(1.,0.,0.));
#620=VECTOR('',#619,1.);
#621=CARTESIAN_POINT('',(-52.0049800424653,2.48718452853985,-68.789241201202));
#622=LINE('',#621,#620);
#623=CARTESIAN_POINT('',(-19.0799800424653,2.48718452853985,-68.789241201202));
#624=VERTEX_POINT('',#623);
#625=EDGE_CURVE('E882',#624,#616,#622,.T.);
#626=ORIENTED_EDGE('',*,*,#625,.F.);
#627=CARTESIAN_POINT('',(-19.0799800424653,0.437184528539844,-68.789241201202));
#628=DIRECTION('',(0.,0.,1.));
#629=DIRECTION('',(1.,0.,0.));
#630=AXIS2_PLACEMENT_3D('',#627,#628,#629);
#631=CIRCLE('',#630,2.05);
#632=CARTESIAN_POINT('',(-21.1299800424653,0.437184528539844,-68.789241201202));
#633=VERTEX_POINT('',#632);
#634=EDGE_CURVE('E879',#624,#633,#631,.T.);
#635=ORIENTED_EDGE('',*,*,#634,.T.);
#636=DIRECTION('',(0.,1.,0.));
#637=VECTOR('',#636,1.);
#638=CARTESIAN_POINT('',(-21.1299800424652,14.9621845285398,-68.789241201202));
#639=LINE('',#638,#637);
#640=CARTESIAN_POINT('',(-21.1299800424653,-3.96160565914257,-68.789241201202));
#641=VERTEX_POINT('',#640);
#642=EDGE_CURVE('E884',#641,#633,#639,.T.);
#643=ORIENTED_EDGE('',*,*,#642,.F.);
#644=CARTESIAN_POINT('',(-19.0799800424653,-3.96160565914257,-68.789241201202));
#645=DIRECTION('',(0.,0.,1.));
#646=DIRECTION('',(1.,0.,0.));
#647=AXIS2_PLACEMENT_3D('',#644,#645,#646);
#648=CIRCLE('',#647,2.05);
#649=CARTESIAN_POINT('',(-20.7199800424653,-5.19160565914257,-68.789241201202));
#650=VERTEX_POINT('',#649);
#651=EDGE_CURVE('E887',#641,#650,#648,.T.);
#652=ORIENTED_EDGE('',*,*,#651,.T.);
#653=CARTESIAN_POINT('',(-27.2799800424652,-10.1116056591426,-68.789241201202));
#654=DIRECTION('',(0.,0.,1.));
#655=DIRECTION('',(1.,0.,0.));
#656=AXIS2_PLACEMENT_3D('',#653,#654,#655);
#657=CIRCLE('',#656,8.2);
#658=CARTESIAN_POINT('',(-19.0799800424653,-10.1116056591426,-68.789241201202));
#659=VERTEX_POINT('',#658);
#660=EDGE_CURVE('E893',#659,#650,#657,.T.);
#661=ORIENTED_EDGE('',*,*,#660,.F.);
#662=DIRECTION('',(0.,1.,0.));
#663=VECTOR('',#662,1.);
#664=CARTESIAN_POINT('',(-19.0799800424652,14.9621845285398,-68.789241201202));
#665=LINE('',#664,#663);
#666=CARTESIAN_POINT('',(-19.0799800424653,-27.9640252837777,-68.789241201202));
#667=VERTEX_POINT('',#666);
#668=EDGE_CURVE('E897',#667,#659,#665,.T.);
#669=ORIENTED_EDGE('',*,*,#668,.F.);
#670=CARTESIAN_POINT('',(-27.2799800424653,-27.9640252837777,-68.789241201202));
#671=DIRECTION('',(0.,0.,1.));
#672=DIRECTION('',(1.,0.,0.));
#673=AXIS2_PLACEMENT_3D('',#670,#671,#672);
#674=CIRCLE('',#673,8.2);
#675=CARTESIAN_POINT('',(-20.7199800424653,-32.8840252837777,-68.789241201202));
#676=VERTEX_POINT('',#675);
#677=EDGE_CURVE('E902',#676,#667,#674,.T.);
#678=ORIENTED_EDGE('',*,*,#677,.F.);
#679=CARTESIAN_POINT('',(-19.0799800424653,-34.1140252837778,-68.789241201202));
#680=DIRECTION('',(0.,0.,1.));
#681=DIRECTION('',(1.,0.,0.));
#682=AXIS2_PLACEMENT_3D('',#679,#680,#681);
#683=CIRCLE('',#682,2.05);
#684=CARTESIAN_POINT('',(-21.1299800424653,-34.1140252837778,-68.789241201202));
#685=VERTEX_POINT('',#684);
#686=EDGE_CURVE('E908',#676,#685,#683,.T.);
#687=ORIENTED_EDGE('',*,*,#686,.T.);
#688=DIRECTION('',(0.,1.,0.));
#689=VECTOR('',#688,1.);
#690=CARTESIAN_POINT('',(-21.1299800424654,14.9621845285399,-68.789241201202));
#691=LINE('',#690,#689);
#692=CARTESIAN_POINT('',(-21.1299800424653,-38.5128154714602,-68.789241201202));
#693=VERTEX_POINT('',#692);
#694=EDGE_CURVE('E913',#693,#685,#691,.T.);
#695=ORIENTED_EDGE('',*,*,#694,.F.);
#696=CARTESIAN_POINT('',(-19.0799800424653,-38.5128154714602,-68.789241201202));
#697=DIRECTION('',(0.,0.,1.));
#698=DIRECTION('',(1.,0.,0.));
#699=AXIS2_PLACEMENT_3D('',#696,#697,#698);
#700=CIRCLE('',#699,2.05);
#701=CARTESIAN_POINT('',(-19.0799800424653,-40.5628154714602,-68.789241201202));
#702=VERTEX_POINT('',#701);
#703=EDGE_CURVE('E915',#693,#702,#700,.T.);
#704=ORIENTED_EDGE('',*,*,#703,.T.);
#705=CARTESIAN_POINT('',(-18.5322340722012,-40.5628154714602,-68.7892412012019));
#706=VERTEX_POINT('',#705);
#707=EDGE_CURVE('E921',#706,#702,#536,.T.);
#708=ORIENTED_EDGE('',*,*,#707,.F.);
#709=DIRECTION('',(0.412647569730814,0.910890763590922,0.));
#710=VECTOR('',#709,1.);
#711=CARTESIAN_POINT('',(-18.9703918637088,-41.5300182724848,-68.789241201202));
#712=LINE('',#711,#710);
#713=CARTESIAN_POINT('',(-18.9122101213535,-41.4015861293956,-68.7892412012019));
#714=VERTEX_POINT('',#713);
#715=EDGE_CURVE('E525',#714,#706,#712,.T.);
#716=ORIENTED_EDGE('',*,*,#715,.F.);
#717=CARTESIAN_POINT('',(-19.0515955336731,-42.8950959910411,-68.789241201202));
#718=DIRECTION('',(0.,0.,1.));
#719=DIRECTION('',(1.,0.,0.));
#720=AXIS2_PLACEMENT_3D('',#717,#718,#719);
#721=CIRCLE('',#720,1.5);
#722=CARTESIAN_POINT('',(-20.3577442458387,-42.1575490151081,-68.789241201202));
#723=VERTEX_POINT('',#722);
#724=EDGE_CURVE('E1003',#714,#723,#721,.T.);
#725=ORIENTED_EDGE('',*,*,#724,.T.);
#726=CARTESIAN_POINT('',(-27.0049800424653,-38.404034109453,-68.789241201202));
#727=DIRECTION('',(0.,0.,1.));
#728=DIRECTION('',(1.,0.,0.));
#729=AXIS2_PLACEMENT_3D('',#726,#727,#728);
#730=CIRCLE('',#729,7.63378136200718);
#731=EDGE_CURVE('E979',#723,#301,#730,.F.);
#732=ORIENTED_EDGE('',*,*,#731,.T.);
#733=EDGE_LOOP('',(#305,#313,#321,#330,#338,#347,#356,#364,#373,#382,#390,#399,#407,#416,#424,
#433,#442,#450,#459,#468,#476,#485,#489,#497,#506,#515,#524,#532,#540,#549,#557,#566,#575,#583,
#592,#601,#609,#618,#626,#635,#643,#652,#661,#669,#678,#687,#695,#704,#708,#716,#725,#732));
#734=FACE_BOUND('',#733,.T.);
#735=CARTESIAN_POINT('',(-38.0049800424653,-47.5378154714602,-68.789241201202));
#736=DIRECTION('',(0.,0.,-1.));
#737=DIRECTION('',(-1.,0.,0.));
#738=AXIS2_PLACEMENT_3D('',#735,#736,#737);
#739=CIRCLE('',#738,3.);
#740=CARTESIAN_POINT('',(-41.0049800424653,-47.5378154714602,-68.789241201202));
#741=VERTEX_POINT('',#740);
#742=EDGE_CURVE('E759',#741,#741,#739,.T.);
#743=ORIENTED_EDGE('',*,*,#742,.F.);
#744=EDGE_LOOP('',(#743));
#745=FACE_BOUND('',#744,.T.);
#746=CARTESIAN_POINT('',(-16.0049800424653,9.46218452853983,-68.789241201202));
#747=DIRECTION('',(0.,0.,-1.));
#748=DIRECTION('',(-1.,0.,0.));
#749=AXIS2_PLACEMENT_3D('',#746,#747,#748);
#750=CIRCLE('',#749,3.);
#751=CARTESIAN_POINT('',(-19.0049800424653,9.46218452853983,-68.789241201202));
#752=VERTEX_POINT('',#751);
#753=EDGE_CURVE('E758',#752,#752,#750,.T.);
#754=ORIENTED_EDGE('',*,*,#753,.F.);
#755=EDGE_LOOP('',(#754));
#756=FACE_BOUND('',#755,.T.);
#757=DIRECTION('',(-1.,0.,0.));
#758=VECTOR('',#757,1.);
#759=CARTESIAN_POINT('',(-52.0049800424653,-53.0378154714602,-68.789241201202));
#760=LINE('',#759,#758);
#761=CARTESIAN_POINT('',(-52.0049800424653,-53.0378154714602,-68.789241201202));
#762=VERTEX_POINT('',#761);
#763=EDGE_CURVE('E799',#278,#762,#760,.T.);
#764=ORIENTED_EDGE('',*,*,#763,.T.);
#765=DIRECTION('',(0.,-1.,0.));
#766=VECTOR('',#765,1.);
#767=CARTESIAN_POINT('',(-52.0049800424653,14.9621845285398,-68.789241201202));
#768=LINE('',#767,#766);
#769=CARTESIAN_POINT('',(-52.0049800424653,14.9621845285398,-68.789241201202));
#770=VERTEX_POINT('',#769);
#771=EDGE_CURVE('E791',#770,#762,#768,.T.);
#772=ORIENTED_EDGE('',*,*,#771,.F.);
#773=DIRECTION('',(-1.,0.,0.));
#774=VECTOR('',#773,1.);
#775=CARTESIAN_POINT('',(-52.0049800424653,14.9621845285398,-68.789241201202));
#776=LINE('',#775,#774);
#777=EDGE_CURVE('E777',#262,#770,#776,.T.);
#778=ORIENTED_EDGE('',*,*,#777,.F.);
#779=ORIENTED_EDGE('',*,*,#285,.T.);
#780=EDGE_LOOP('',(#764,#772,#778,#779));
#781=FACE_BOUND('',#780,.T.);
#782=ADVANCED_FACE('F1138',(#734,#745,#756,#781),#294,.F.);
#783=CARTESIAN_POINT('',(-52.0049800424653,14.9621845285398,-68.789241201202));
#784=DIRECTION('',(1.,0.,0.));
#785=DIRECTION('',(0.,0.,-1.));
#786=AXIS2_PLACEMENT_3D('',#783,#784,#785);
#787=PLANE('',#786);
#788=DIRECTION('',(0.,0.,1.));
#789=VECTOR('',#788,1.);
#790=CARTESIAN_POINT('',(-52.0049800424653,-53.0378154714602,-68.789241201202));
#791=LINE('',#790,#789);
#792=CARTESIAN_POINT('',(-52.0049800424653,-53.0378154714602,-53.989241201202));
#793=VERTEX_POINT('',#792);
#794=EDGE_CURVE('E801',#762,#793,#791,.T.);
#795=ORIENTED_EDGE('',*,*,#794,.T.);
#796=DIRECTION('',(0.,-1.,0.));
#797=VECTOR('',#796,1.);
#798=CARTESIAN_POINT('',(-52.0049800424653,14.9621845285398,-53.989241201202));
#799=LINE('',#798,#797);
#800=CARTESIAN_POINT('',(-52.0049800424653,14.9621845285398,-53.989241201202));
#801=VERTEX_POINT('',#800);
#802=EDGE_CURVE('E851',#793,#801,#799,.F.);
#803=ORIENTED_EDGE('',*,*,#802,.T.);
#804=DIRECTION('',(0.,0.,1.));
#805=VECTOR('',#804,1.);
#806=CARTESIAN_POINT('',(-52.0049800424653,14.9621845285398,-68.789241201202));
#807=LINE('',#806,#805);
#808=EDGE_CURVE('E779',#770,#801,#807,.T.);
#809=ORIENTED_EDGE('',*,*,#808,.F.);
#810=ORIENTED_EDGE('',*,*,#771,.T.);
#811=EDGE_LOOP('',(#795,#803,#809,#810));
#812=FACE_BOUND('',#811,.T.);
#813=ADVANCED_FACE('F1469',(#812),#787,.F.);
#814=CARTESIAN_POINT('',(-54.5049800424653,14.9621845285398,-53.689241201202));
#815=DIRECTION('',(0.,0.,1.));
#816=DIRECTION('',(1.,0.,0.));
#817=AXIS2_PLACEMENT_3D('',#814,#815,#816);
#818=PLANE('',#817);
#819=DIRECTION('',(-1.,0.,0.));
#820=VECTOR('',#819,1.);
#821=CARTESIAN_POINT('',(-54.5049800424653,14.9621845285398,-53.689241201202));
#822=LINE('',#821,#820);
#823=CARTESIAN_POINT('',(-52.3049800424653,14.9621845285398,-53.689241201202));
#824=VERTEX_POINT('',#823);
#825=CARTESIAN_POINT('',(-54.2049800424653,14.9621845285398,-53.689241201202));
#826=VERTEX_POINT('',#825);
#827=EDGE_CURVE('E782',#824,#826,#822,.T.);
#828=ORIENTED_EDGE('',*,*,#827,.F.);
#829=DIRECTION('',(0.,-1.,0.));
#830=VECTOR('',#829,1.);
#831=CARTESIAN_POINT('',(-52.3049800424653,-53.0378154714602,-53.689241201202));
#832=LINE('',#831,#830);
#833=CARTESIAN_POINT('',(-52.3049800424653,-53.0378154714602,-53.689241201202));
#834=VERTEX_POINT('',#833);
#835=EDGE_CURVE('E848',#824,#834,#832,.T.);
#836=ORIENTED_EDGE('',*,*,#835,.T.);
#837=DIRECTION('',(-1.,0.,0.));
#838=VECTOR('',#837,1.);
#839=CARTESIAN_POINT('',(-54.5049800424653,-53.0378154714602,-53.689241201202));
#840=LINE('',#839,#838);
#841=CARTESIAN_POINT('',(-54.2049800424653,-53.0378154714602,-53.689241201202));
#842=VERTEX_POINT('',#841);
#843=EDGE_CURVE('E804',#834,#842,#840,.T.);
#844=ORIENTED_EDGE('',*,*,#843,.T.);
#845=DIRECTION('',(0.,-1.,0.));
#846=VECTOR('',#845,1.);
#847=CARTESIAN_POINT('',(-54.2049800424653,14.9621845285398,-53.689241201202));
#848=LINE('',#847,#846);
#849=EDGE_CURVE('E846',#842,#826,#848,.F.);
#850=ORIENTED_EDGE('',*,*,#849,.T.);
#851=EDGE_LOOP('',(#828,#836,#844,#850));
#852=FACE_BOUND('',#851,.T.);
#853=ADVANCED_FACE('F1944',(#852),#818,.F.);
#854=CARTESIAN_POINT('',(-54.5049800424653,14.9621845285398,-53.689241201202));
#855=DIRECTION('',(1.,0.,0.));
#856=DIRECTION('',(0.,0.,-1.));
#857=AXIS2_PLACEMENT_3D('',#854,#855,#856);
#858=PLANE('',#857);
#859=DIRECTION('',(0.,0.,1.));
#860=VECTOR('',#859,1.);
#861=CARTESIAN_POINT('',(-54.5049800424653,14.9621845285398,-53.689241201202));
#862=LINE('',#861,#860);
#863=CARTESIAN_POINT('',(-54.5049800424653,14.9621845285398,-53.389241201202));
#864=VERTEX_POINT('',#863);
#865=CARTESIAN_POINT('',(-54.5049800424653,14.9621845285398,-43.989241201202));
#866=VERTEX_POINT('',#865);
#867=EDGE_CURVE('E785',#864,#866,#862,.T.);
#868=ORIENTED_EDGE('',*,*,#867,.F.);
#869=DIRECTION('',(0.,-1.,0.));
#870=VECTOR('',#869,1.);
#871=CARTESIAN_POINT('',(-54.5049800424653,14.9621845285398,-53.389241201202));
#872=LINE('',#871,#870);
#873=CARTESIAN_POINT('',(-54.5049800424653,-53.0378154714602,-53.389241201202));
#874=VERTEX_POINT('',#873);
#875=EDGE_CURVE('E855',#864,#874,#872,.T.);
#876=ORIENTED_EDGE('',*,*,#875,.T.);
#877=DIRECTION('',(0.,0.,1.));
#878=VECTOR('',#877,1.);
#879=CARTESIAN_POINT('',(-54.5049800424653,-53.0378154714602,-53.689241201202));
#880=LINE('',#879,#878);
#881=CARTESIAN_POINT('',(-54.5049800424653,-53.0378154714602,-43.989241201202));
#882=VERTEX_POINT('',#881);
#883=EDGE_CURVE('E807',#874,#882,#880,.T.);
#884=ORIENTED_EDGE('',*,*,#883,.T.);
#885=DIRECTION('',(0.,-1.,0.));
#886=VECTOR('',#885,1.);
#887=CARTESIAN_POINT('',(-54.5049800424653,14.9621845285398,-43.989241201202));
#888=LINE('',#887,#886);
#889=EDGE_CURVE('E853',#882,#866,#888,.F.);
#890=ORIENTED_EDGE('',*,*,#889,.T.);
#891=EDGE_LOOP('',(#868,#876,#884,#890));
#892=FACE_BOUND('',#891,.T.);
#893=ADVANCED_FACE('F1935',(#892),#858,.F.);
#894=CARTESIAN_POINT('',(-54.5049800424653,14.9621845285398,-43.689241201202));
#895=DIRECTION('',(0.,0.,-1.));
#896=DIRECTION('',(-1.,0.,0.));
#897=AXIS2_PLACEMENT_3D('',#894,#895,#896);
#898=PLANE('',#897);
#899=CARTESIAN_POINT('',(-27.0049800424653,-47.5378154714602,-43.689241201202));
#900=DIRECTION('',(0.,0.,-1.));
#901=DIRECTION('',(-1.,0.,0.));
#902=AXIS2_PLACEMENT_3D('',#899,#900,#901);
#903=CIRCLE('',#902,3.19999999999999);
#904=CARTESIAN_POINT('',(-30.2049800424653,-47.5378154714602,-43.689241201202));
#905=VERTEX_POINT('',#904);
#906=EDGE_CURVE('E876',#905,#905,#903,.T.);
#907=ORIENTED_EDGE('',*,*,#906,.T.);
#908=EDGE_LOOP('',(#907));
#909=FACE_BOUND('',#908,.T.);
#910=CARTESIAN_POINT('',(-38.0049800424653,-47.5378154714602,-43.689241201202));
#911=DIRECTION('',(0.,0.,-1.));
#912=DIRECTION('',(-1.,0.,0.));
#913=AXIS2_PLACEMENT_3D('',#910,#911,#912);
#914=CIRCLE('',#913,3.);
#915=CARTESIAN_POINT('',(-41.0049800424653,-47.5378154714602,-43.689241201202));
#916=VERTEX_POINT('',#915);
#917=EDGE_CURVE('E755',#916,#916,#914,.T.);
#918=ORIENTED_EDGE('',*,*,#917,.T.);
#919=EDGE_LOOP('',(#918));
#920=FACE_BOUND('',#919,.T.);
#921=CARTESIAN_POINT('',(-16.0049800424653,9.46218452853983,-43.689241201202));
#922=DIRECTION('',(0.,0.,-1.));
#923=DIRECTION('',(-1.,0.,0.));
#924=AXIS2_PLACEMENT_3D('',#921,#922,#923);
#925=CIRCLE('',#924,3.);
#926=CARTESIAN_POINT('',(-19.0049800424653,9.46218452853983,-43.689241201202));
#927=VERTEX_POINT('',#926);
#928=EDGE_CURVE('E762',#927,#927,#925,.T.);
#929=ORIENTED_EDGE('',*,*,#928,.T.);
#930=EDGE_LOOP('',(#929));
#931=FACE_BOUND('',#930,.T.);
#932=DIRECTION('',(1.,0.,0.));
#933=VECTOR('',#932,1.);
#934=CARTESIAN_POINT('',(-54.5049800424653,-53.0378154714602,-43.689241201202));
#935=LINE('',#934,#933);
#936=CARTESIAN_POINT('',(-54.2049800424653,-53.0378154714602,-43.689241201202));
#937=VERTEX_POINT('',#936);
#938=CARTESIAN_POINT('',(0.195019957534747,-53.0378154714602,-43.689241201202));
#939=VERTEX_POINT('',#938);
#940=EDGE_CURVE('E772',#937,#939,#935,.T.);
#941=ORIENTED_EDGE('',*,*,#940,.T.);
#942=DIRECTION('',(0.,-1.,0.));
#943=VECTOR('',#942,1.);
#944=CARTESIAN_POINT('',(0.195019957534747,14.9621845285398,-43.689241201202));
#945=LINE('',#944,#943);
#946=CARTESIAN_POINT('',(0.195019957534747,14.9621845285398,-43.689241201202));
#947=VERTEX_POINT('',#946);
#948=EDGE_CURVE('E861',#939,#947,#945,.F.);
#949=ORIENTED_EDGE('',*,*,#948,.T.);
#950=DIRECTION('',(1.,0.,0.));
#951=VECTOR('',#950,1.);
#952=CARTESIAN_POINT('',(-54.5049800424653,14.9621845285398,-43.689241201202));
#953=LINE('',#952,#951);
#954=CARTESIAN_POINT('',(-54.2049800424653,14.9621845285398,-43.689241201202));
#955=VERTEX_POINT('',#954);
#956=EDGE_CURVE('E788',#955,#947,#953,.T.);
#957=ORIENTED_EDGE('',*,*,#956,.F.);
#958=DIRECTION('',(0.,-1.,0.));
#959=VECTOR('',#958,1.);
#960=CARTESIAN_POINT('',(-54.2049800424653,14.9621845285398,-43.689241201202));
#961=LINE('',#960,#959);
#962=EDGE_CURVE('E858',#955,#937,#961,.T.);
#963=ORIENTED_EDGE('',*,*,#962,.T.);
#964=EDGE_LOOP('',(#941,#949,#957,#963));
#965=FACE_BOUND('',#964,.T.);
#966=ADVANCED_FACE('F1926',(#909,#920,#931,#965),#898,.F.);
#967=CARTESIAN_POINT('',(-27.0049800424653,14.9621845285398,-43.689241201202));
#968=DIRECTION('',(0.,1.,0.));
#969=DIRECTION('',(0.,0.,1.));
#970=AXIS2_PLACEMENT_3D('',#967,#968,#969);
#971=PLANE('',#970);
#972=ORIENTED_EDGE('',*,*,#199,.T.);
#973=CARTESIAN_POINT('',(0.19501995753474,14.9621845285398,-53.389241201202));
#974=DIRECTION('',(0.,1.,0.));
#975=DIRECTION('',(0.,0.,1.));
#976=AXIS2_PLACEMENT_3D('',#973,#974,#975);
#977=CIRCLE('',#976,0.3);
#978=EDGE_CURVE('E841',#190,#220,#977,.T.);
#979=ORIENTED_EDGE('',*,*,#978,.T.);
#980=ORIENTED_EDGE('',*,*,#223,.T.);
#981=CARTESIAN_POINT('',(-1.70498004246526,14.9621845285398,-53.989241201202));
#982=DIRECTION('',(0.,1.,0.));
#983=DIRECTION('',(0.,0.,1.));
#984=AXIS2_PLACEMENT_3D('',#981,#982,#983);
#985=CIRCLE('',#984,0.3);
#986=EDGE_CURVE('E865',#222,#260,#985,.F.);
#987=ORIENTED_EDGE('',*,*,#986,.T.);
#988=ORIENTED_EDGE('',*,*,#263,.T.);
#989=ORIENTED_EDGE('',*,*,#777,.T.);
#990=ORIENTED_EDGE('',*,*,#808,.T.);
#991=CARTESIAN_POINT('',(-52.3049800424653,14.9621845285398,-53.989241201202));
#992=DIRECTION('',(0.,1.,0.));
#993=DIRECTION('',(0.,0.,1.));
#994=AXIS2_PLACEMENT_3D('',#991,#992,#993);
#995=CIRCLE('',#994,0.3);
#996=EDGE_CURVE('E869',#801,#824,#995,.F.);
#997=ORIENTED_EDGE('',*,*,#996,.T.);
#998=ORIENTED_EDGE('',*,*,#827,.T.);
#999=CARTESIAN_POINT('',(-54.2049800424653,14.9621845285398,-53.389241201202));
#1000=DIRECTION('',(0.,1.,0.));
#1001=DIRECTION('',(0.,0.,1.));
#1002=AXIS2_PLACEMENT_3D('',#999,#1000,#1001);
#1003=CIRCLE('',#1002,0.3);
#1004=EDGE_CURVE('E839',#826,#864,#1003,.T.);
#1005=ORIENTED_EDGE('',*,*,#1004,.T.);
#1006=ORIENTED_EDGE('',*,*,#867,.T.);
#1007=CARTESIAN_POINT('',(-54.2049800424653,14.9621845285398,-43.989241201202));
#1008=DIRECTION('',(0.,1.,0.));
#1009=DIRECTION('',(0.,0.,1.));
#1010=AXIS2_PLACEMENT_3D('',#1007,#1008,#1009);
#1011=CIRCLE('',#1010,0.3);
#1012=EDGE_CURVE('E835',#866,#955,#1011,.T.);
#1013=ORIENTED_EDGE('',*,*,#1012,.T.);
#1014=ORIENTED_EDGE('',*,*,#956,.T.);
#1015=CARTESIAN_POINT('',(0.195019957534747,14.9621845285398,-43.989241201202));
#1016=DIRECTION('',(0.,1.,0.));
#1017=DIRECTION('',(0.,0.,1.));
#1018=AXIS2_PLACEMENT_3D('',#1015,#1016,#1017);
#1019=CIRCLE('',#1018,0.3);
#1020=EDGE_CURVE('E837',#947,#198,#1019,.T.);
#1021=ORIENTED_EDGE('',*,*,#1020,.T.);
#1022=EDGE_LOOP('',(#972,#979,#980,#987,#988,#989,#990,#997,#998,#1005,#1006,#1013,#1014,#1021));
#1023=FACE_BOUND('',#1022,.T.);
#1024=ADVANCED_FACE('F1917',(#1023),#971,.T.);
#1025=CARTESIAN_POINT('',(-27.0049800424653,-53.0378154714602,-43.689241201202));
#1026=DIRECTION('',(0.,1.,0.));
#1027=DIRECTION('',(0.,0.,1.));
#1028=AXIS2_PLACEMENT_3D('',#1025,#1026,#1027);
#1029=PLANE('',#1028);
#1030=ORIENTED_EDGE('',*,*,#239,.F.);
#1031=CARTESIAN_POINT('',(0.19501995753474,-53.0378154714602,-53.389241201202));
#1032=DIRECTION('',(0.,1.,0.));
#1033=DIRECTION('',(0.,0.,1.));
#1034=AXIS2_PLACEMENT_3D('',#1031,#1032,#1033);
#1035=CIRCLE('',#1034,0.3);
#1036=EDGE_CURVE('E828',#230,#182,#1035,.F.);
#1037=ORIENTED_EDGE('',*,*,#1036,.T.);
#1038=ORIENTED_EDGE('',*,*,#183,.F.);
#1039=CARTESIAN_POINT('',(0.195019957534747,-53.0378154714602,-43.989241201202));
#1040=DIRECTION('',(0.,1.,0.));
#1041=DIRECTION('',(0.,0.,1.));
#1042=AXIS2_PLACEMENT_3D('',#1039,#1040,#1041);
#1043=CIRCLE('',#1042,0.3);
#1044=EDGE_CURVE('E824',#180,#939,#1043,.F.);
#1045=ORIENTED_EDGE('',*,*,#1044,.T.);
#1046=ORIENTED_EDGE('',*,*,#940,.F.);
#1047=CARTESIAN_POINT('',(-54.2049800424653,-53.0378154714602,-43.989241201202));
#1048=DIRECTION('',(0.,1.,0.));
#1049=DIRECTION('',(0.,0.,1.));
#1050=AXIS2_PLACEMENT_3D('',#1047,#1048,#1049);
#1051=CIRCLE('',#1050,0.3);
#1052=EDGE_CURVE('E822',#937,#882,#1051,.F.);
#1053=ORIENTED_EDGE('',*,*,#1052,.T.);
#1054=ORIENTED_EDGE('',*,*,#883,.F.);
#1055=CARTESIAN_POINT('',(-54.2049800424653,-53.0378154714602,-53.389241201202));
#1056=DIRECTION('',(0.,1.,0.));
#1057=DIRECTION('',(0.,0.,1.));
#1058=AXIS2_PLACEMENT_3D('',#1055,#1056,#1057);
#1059=CIRCLE('',#1058,0.3);
#1060=EDGE_CURVE('E826',#874,#842,#1059,.F.);
#1061=ORIENTED_EDGE('',*,*,#1060,.T.);
#1062=ORIENTED_EDGE('',*,*,#843,.F.);
#1063=CARTESIAN_POINT('',(-52.3049800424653,-53.0378154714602,-53.989241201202));
#1064=DIRECTION('',(0.,1.,0.));
#1065=DIRECTION('',(0.,0.,1.));
#1066=AXIS2_PLACEMENT_3D('',#1063,#1064,#1065);
#1067=CIRCLE('',#1066,0.3);
#1068=EDGE_CURVE('E867',#834,#793,#1067,.T.);
#1069=ORIENTED_EDGE('',*,*,#1068,.T.);
#1070=ORIENTED_EDGE('',*,*,#794,.F.);
#1071=ORIENTED_EDGE('',*,*,#763,.F.);
#1072=ORIENTED_EDGE('',*,*,#279,.F.);
#1073=CARTESIAN_POINT('',(-1.70498004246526,-53.0378154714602,-53.989241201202));
#1074=DIRECTION('',(0.,1.,0.));
#1075=DIRECTION('',(0.,0.,1.));
#1076=AXIS2_PLACEMENT_3D('',#1073,#1074,#1075);
#1077=CIRCLE('',#1076,0.3);
#1078=EDGE_CURVE('E863',#270,#238,#1077,.T.);
#1079=ORIENTED_EDGE('',*,*,#1078,.T.);
#1080=EDGE_LOOP('',(#1030,#1037,#1038,#1045,#1046,#1053,#1054,#1061,#1062,#1069,#1070,#1071,
#1072,#1079));
#1081=FACE_BOUND('',#1080,.T.);
#1082=ADVANCED_FACE('F1286',(#1081),#1029,.F.);
#1083=CARTESIAN_POINT('',(0.19501995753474,14.9621845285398,-53.389241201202));
#1084=DIRECTION('',(0.,-1.,0.));
#1085=DIRECTION('',(0.,0.,-1.));
#1086=AXIS2_PLACEMENT_3D('',#1083,#1084,#1085);
#1087=CYLINDRICAL_SURFACE('',#1086,0.3);
#1088=ORIENTED_EDGE('',*,*,#978,.F.);
#1089=ORIENTED_EDGE('',*,*,#191,.F.);
#1090=ORIENTED_EDGE('',*,*,#1036,.F.);
#1091=ORIENTED_EDGE('',*,*,#231,.F.);
#1092=EDGE_LOOP('',(#1088,#1089,#1090,#1091));
#1093=FACE_BOUND('',#1092,.T.);
#1094=ADVANCED_FACE('F1282',(#1093),#1087,.T.);
#1095=CARTESIAN_POINT('',(-1.70498004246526,14.9621845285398,-53.989241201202));
#1096=DIRECTION('',(0.,1.,0.));
#1097=DIRECTION('',(0.,0.,1.));
#1098=AXIS2_PLACEMENT_3D('',#1095,#1096,#1097);
#1099=CYLINDRICAL_SURFACE('',#1098,0.3);
#1100=ORIENTED_EDGE('',*,*,#986,.F.);
#1101=ORIENTED_EDGE('',*,*,#245,.F.);
#1102=ORIENTED_EDGE('',*,*,#1078,.F.);
#1103=ORIENTED_EDGE('',*,*,#271,.F.);
#1104=EDGE_LOOP('',(#1100,#1101,#1102,#1103));
#1105=FACE_BOUND('',#1104,.T.);
#1106=ADVANCED_FACE('F1285',(#1105),#1099,.F.);
#1107=CARTESIAN_POINT('',(-52.3049800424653,14.9621845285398,-53.989241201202));
#1108=DIRECTION('',(0.,1.,0.));
#1109=DIRECTION('',(0.,0.,1.));
#1110=AXIS2_PLACEMENT_3D('',#1107,#1108,#1109);
#1111=CYLINDRICAL_SURFACE('',#1110,0.3);
#1112=ORIENTED_EDGE('',*,*,#996,.F.);
#1113=ORIENTED_EDGE('',*,*,#802,.F.);
#1114=ORIENTED_EDGE('',*,*,#1068,.F.);
#1115=ORIENTED_EDGE('',*,*,#835,.F.);
#1116=EDGE_LOOP('',(#1112,#1113,#1114,#1115));
#1117=FACE_BOUND('',#1116,.T.);
#1118=ADVANCED_FACE('F1290',(#1117),#1111,.F.);
#1119=CARTESIAN_POINT('',(-54.2049800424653,14.9621845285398,-53.389241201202));
#1120=DIRECTION('',(0.,-1.,0.));
#1121=DIRECTION('',(0.,0.,-1.));
#1122=AXIS2_PLACEMENT_3D('',#1119,#1120,#1121);
#1123=CYLINDRICAL_SURFACE('',#1122,0.3);
#1124=ORIENTED_EDGE('',*,*,#1004,.F.);
#1125=ORIENTED_EDGE('',*,*,#849,.F.);
#1126=ORIENTED_EDGE('',*,*,#1060,.F.);
#1127=ORIENTED_EDGE('',*,*,#875,.F.);
#1128=EDGE_LOOP('',(#1124,#1125,#1126,#1127));
#1129=FACE_BOUND('',#1128,.T.);
#1130=ADVANCED_FACE('F1294',(#1129),#1123,.T.);
#1131=CARTESIAN_POINT('',(0.195019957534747,14.9621845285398,-43.989241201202));
#1132=DIRECTION('',(0.,-1.,0.));
#1133=DIRECTION('',(0.,0.,-1.));
#1134=AXIS2_PLACEMENT_3D('',#1131,#1132,#1133);
#1135=CYLINDRICAL_SURFACE('',#1134,0.3);
#1136=ORIENTED_EDGE('',*,*,#1020,.F.);
#1137=ORIENTED_EDGE('',*,*,#948,.F.);
#1138=ORIENTED_EDGE('',*,*,#1044,.F.);
#1139=ORIENTED_EDGE('',*,*,#205,.F.);
#1140=EDGE_LOOP('',(#1136,#1137,#1138,#1139));
#1141=FACE_BOUND('',#1140,.T.);
#1142=ADVANCED_FACE('F1298',(#1141),#1135,.T.);
#1143=CARTESIAN_POINT('',(-54.2049800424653,14.9621845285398,-43.989241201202));
#1144=DIRECTION('',(0.,-1.,0.));
#1145=DIRECTION('',(0.,0.,-1.));
#1146=AXIS2_PLACEMENT_3D('',#1143,#1144,#1145);
#1147=CYLINDRICAL_SURFACE('',#1146,0.3);
#1148=ORIENTED_EDGE('',*,*,#1012,.F.);
#1149=ORIENTED_EDGE('',*,*,#889,.F.);
#1150=ORIENTED_EDGE('',*,*,#1052,.F.);
#1151=ORIENTED_EDGE('',*,*,#962,.F.);
#1152=EDGE_LOOP('',(#1148,#1149,#1150,#1151));
#1153=FACE_BOUND('',#1152,.T.);
#1154=ADVANCED_FACE('F1302',(#1153),#1147,.T.);
#1155=CARTESIAN_POINT('',(-16.0049800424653,9.46218452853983,-43.689241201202));
#1156=DIRECTION('',(0.,0.,-1.));
#1157=DIRECTION('',(-1.,0.,0.));
#1158=AXIS2_PLACEMENT_3D('',#1155,#1156,#1157);
#1159=CYLINDRICAL_SURFACE('',#1158,3.);
#1160=ORIENTED_EDGE('',*,*,#928,.F.);
#1161=EDGE_LOOP('',(#1160));
#1162=FACE_BOUND('',#1161,.T.);
#1163=ORIENTED_EDGE('',*,*,#753,.T.);
#1164=EDGE_LOOP('',(#1163));
#1165=FACE_BOUND('',#1164,.T.);
#1166=ADVANCED_FACE('F1306',(#1162,#1165),#1159,.F.);
#1167=CARTESIAN_POINT('',(-38.0049800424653,-47.5378154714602,-43.689241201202));
#1168=DIRECTION('',(0.,0.,-1.));
#1169=DIRECTION('',(-1.,0.,0.));
#1170=AXIS2_PLACEMENT_3D('',#1167,#1168,#1169);
#1171=CYLINDRICAL_SURFACE('',#1170,3.);
#1172=ORIENTED_EDGE('',*,*,#917,.F.);
#1173=EDGE_LOOP('',(#1172));
#1174=FACE_BOUND('',#1173,.T.);
#1175=ORIENTED_EDGE('',*,*,#742,.T.);
#1176=EDGE_LOOP('',(#1175));
#1177=FACE_BOUND('',#1176,.T.);
#1178=ADVANCED_FACE('F1829',(#1174,#1177),#1171,.F.);
#1179=CARTESIAN_POINT('',(-27.0049800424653,-47.5378154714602,-53.689241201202));
#1180=DIRECTION('',(0.,0.,1.));
#1181=DIRECTION('',(1.,0.,0.));
#1182=AXIS2_PLACEMENT_3D('',#1179,#1180,#1181);
#1183=PLANE('',#1182);
#1184=CARTESIAN_POINT('',(-27.0049800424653,-47.5378154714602,-53.689241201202));
#1185=DIRECTION('',(0.,0.,1.));
#1186=DIRECTION('',(1.,0.,0.));
#1187=AXIS2_PLACEMENT_3D('',#1184,#1185,#1186);
#1188=CIRCLE('',#1187,3.);
#1189=CARTESIAN_POINT('',(-24.0049800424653,-47.5378154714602,-53.689241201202));
#1190=VERTEX_POINT('',#1189);
#1191=EDGE_CURVE('E751',#1190,#1190,#1188,.T.);
#1192=ORIENTED_EDGE('',*,*,#1191,.T.);
#1193=EDGE_LOOP('',(#1192));
#1194=FACE_BOUND('',#1193,.T.);
#1195=ORIENTED_EDGE('',*,*,#165,.T.);
#1196=EDGE_LOOP('',(#1195));
#1197=FACE_BOUND('',#1196,.T.);
#1198=ADVANCED_FACE('F1827',(#1194,#1197),#1183,.T.);
#1199=CARTESIAN_POINT('',(-27.0049800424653,-47.5378154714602,-53.689241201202));
#1200=DIRECTION('',(0.,0.,1.));
#1201=DIRECTION('',(1.,0.,0.));
#1202=AXIS2_PLACEMENT_3D('',#1199,#1200,#1201);
#1203=CYLINDRICAL_SURFACE('',#1202,3.);
#1204=CARTESIAN_POINT('',(-27.0049800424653,-47.5378154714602,-43.889241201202));
#1205=DIRECTION('',(0.,0.,-1.));
#1206=DIRECTION('',(-1.,0.,0.));
#1207=AXIS2_PLACEMENT_3D('',#1204,#1205,#1206);
#1208=CIRCLE('',#1207,3.);
#1209=CARTESIAN_POINT('',(-30.0049800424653,-47.5378154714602,-43.889241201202));
#1210=VERTEX_POINT('',#1209);
#1211=EDGE_CURVE('E871',#1210,#1210,#1208,.F.);
#1212=ORIENTED_EDGE('',*,*,#1211,.T.);
#1213=EDGE_LOOP('',(#1212));
#1214=FACE_BOUND('',#1213,.T.);
#1215=ORIENTED_EDGE('',*,*,#1191,.F.);
#1216=EDGE_LOOP('',(#1215));
#1217=FACE_BOUND('',#1216,.T.);
#1218=ADVANCED_FACE('F1312',(#1214,#1217),#1203,.F.);
#1219=CARTESIAN_POINT('',(-27.0049800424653,-47.5378154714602,-43.889241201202));
#1220=DIRECTION('',(0.,0.,1.));
#1221=DIRECTION('',(1.,0.,0.));
#1222=AXIS2_PLACEMENT_3D('',#1219,#1220,#1221);
#1223=CONICAL_SURFACE('',#1222,3.,0.785398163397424);
#1224=ORIENTED_EDGE('',*,*,#906,.F.);
#1225=EDGE_LOOP('',(#1224));
#1226=FACE_BOUND('',#1225,.T.);
#1227=ORIENTED_EDGE('',*,*,#1211,.F.);
#1228=EDGE_LOOP('',(#1227));
#1229=FACE_BOUND('',#1228,.T.);
#1230=ADVANCED_FACE('F1308',(#1226,#1229),#1223,.F.);
#1231=CARTESIAN_POINT('',(-12.9299800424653,-4.68781547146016,-68.807991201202));
#1232=DIRECTION('',(-1.,0.,0.));
#1233=DIRECTION('',(0.,1.,0.));
#1234=AXIS2_PLACEMENT_3D('',#1231,#1232,#1233);
#1235=PLANE('',#1234);
#1236=ORIENTED_EDGE('',*,*,#582,.T.);
#1237=DIRECTION('',(0.,0.,-1.));
#1238=VECTOR('',#1237,1.);
#1239=CARTESIAN_POINT('',(-12.9299800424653,-27.9640252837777,-68.807991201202));
#1240=LINE('',#1239,#1238);
#1241=CARTESIAN_POINT('',(-12.9299800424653,-27.9640252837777,-67.270491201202));
#1242=VERTEX_POINT('',#1241);
#1243=EDGE_CURVE('E676',#1242,#573,#1240,.T.);
#1244=ORIENTED_EDGE('',*,*,#1243,.F.);
#1245=DIRECTION('',(0.,-1.,0.));
#1246=VECTOR('',#1245,1.);
#1247=CARTESIAN_POINT('',(-12.9299800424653,-4.68781547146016,-67.270491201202));
#1248=LINE('',#1247,#1246);
#1249=CARTESIAN_POINT('',(-12.9299800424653,-10.1116056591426,-67.270491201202));
#1250=VERTEX_POINT('',#1249);
#1251=EDGE_CURVE('E652',#1250,#1242,#1248,.T.);
#1252=ORIENTED_EDGE('',*,*,#1251,.F.);
#1253=DIRECTION('',(0.,0.,1.));
#1254=VECTOR('',#1253,1.);
#1255=CARTESIAN_POINT('',(-12.9299800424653,-10.1116056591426,-68.807991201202));
#1256=LINE('',#1255,#1254);
#1257=EDGE_CURVE('E679',#581,#1250,#1256,.T.);
#1258=ORIENTED_EDGE('',*,*,#1257,.F.);
#1259=EDGE_LOOP('',(#1236,#1244,#1252,#1258));
#1260=FACE_BOUND('',#1259,.T.);
#1261=ADVANCED_FACE('F1311',(#1260),#1235,.T.);
#1262=CARTESIAN_POINT('',(-10.8799800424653,-33.3878154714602,-68.807991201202));
#1263=DIRECTION('',(-1.,0.,0.));
#1264=DIRECTION('',(0.,1.,0.));
#1265=AXIS2_PLACEMENT_3D('',#1262,#1263,#1264);
#1266=PLANE('',#1265);
#1267=ORIENTED_EDGE('',*,*,#556,.T.);
#1268=DIRECTION('',(0.,0.,1.));
#1269=VECTOR('',#1268,1.);
#1270=CARTESIAN_POINT('',(-10.8799800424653,-38.5128154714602,-68.807991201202));
#1271=LINE('',#1270,#1269);
#1272=CARTESIAN_POINT('',(-10.8799800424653,-38.5128154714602,-67.270491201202));
#1273=VERTEX_POINT('',#1272);
#1274=EDGE_CURVE('E724',#1273,#547,#1271,.F.);
#1275=ORIENTED_EDGE('',*,*,#1274,.F.);
#1276=DIRECTION('',(0.,-1.,0.));
#1277=VECTOR('',#1276,1.);
#1278=CARTESIAN_POINT('',(-10.8799800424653,-33.3878154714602,-67.270491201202));
#1279=LINE('',#1278,#1277);
#1280=CARTESIAN_POINT('',(-10.8799800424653,-34.1140252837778,-67.270491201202));
#1281=VERTEX_POINT('',#1280);
#1282=EDGE_CURVE('E655',#1281,#1273,#1279,.T.);
#1283=ORIENTED_EDGE('',*,*,#1282,.F.);
#1284=DIRECTION('',(0.,0.,-1.));
#1285=VECTOR('',#1284,1.);
#1286=CARTESIAN_POINT('',(-10.8799800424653,-34.1140252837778,-68.807991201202));
#1287=LINE('',#1286,#1285);
#1288=EDGE_CURVE('E727',#555,#1281,#1287,.F.);
#1289=ORIENTED_EDGE('',*,*,#1288,.F.);
#1290=EDGE_LOOP('',(#1267,#1275,#1283,#1289));
#1291=FACE_BOUND('',#1290,.T.);
#1292=ADVANCED_FACE('F1624',(#1291),#1266,.T.);
#1293=CARTESIAN_POINT('',(-10.8799800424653,-40.5628154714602,-68.807991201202));
#1294=DIRECTION('',(0.,1.,0.));
#1295=DIRECTION('',(0.,0.,-1.));
#1296=AXIS2_PLACEMENT_3D('',#1293,#1294,#1295);
#1297=PLANE('',#1296);
#1298=DIRECTION('',(0.190048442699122,0.,-0.981774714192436));
#1299=VECTOR('',#1298,1.);
#1300=CARTESIAN_POINT('',(-17.4587173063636,-40.5628154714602,-70.0814796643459));
#1301=LINE('',#1300,#1299);
#1302=CARTESIAN_POINT('',(-17.8350224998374,-40.5628154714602,-68.1375178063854));
#1303=VERTEX_POINT('',#1302);
#1304=EDGE_CURVE('E549',#1303,#530,#1301,.T.);
#1305=ORIENTED_EDGE('',*,*,#1304,.F.);
#1306=DIRECTION('',(0.941668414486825,0.,-0.336542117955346));
#1307=VECTOR('',#1306,1.);
#1308=CARTESIAN_POINT('',(-11.4552318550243,-40.5628154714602,-70.4175860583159));
#1309=LINE('',#1308,#1307);
#1310=CARTESIAN_POINT('',(-18.1100073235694,-40.5628154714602,-68.0392412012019));
#1311=VERTEX_POINT('',#1310);
#1312=EDGE_CURVE('E1098',#1311,#1303,#1309,.T.);
#1313=ORIENTED_EDGE('',*,*,#1312,.F.);
#1314=DIRECTION('',(-1.,0.,0.));
#1315=VECTOR('',#1314,1.);
#1316=CARTESIAN_POINT('',(-10.8799800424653,-40.5628154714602,-68.0392412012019));
#1317=LINE('',#1316,#1315);
#1318=CARTESIAN_POINT('',(-18.3870517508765,-40.5628154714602,-68.0392412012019));
#1319=VERTEX_POINT('',#1318);
#1320=EDGE_CURVE('E538',#1311,#1319,#1317,.T.);
#1321=ORIENTED_EDGE('',*,*,#1320,.T.);
#1322=DIRECTION('',(0.190048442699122,0.,0.981774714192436));
#1323=VECTOR('',#1322,1.);
#1324=CARTESIAN_POINT('',(-18.2593452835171,-40.5628154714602,-67.3795200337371));
#1325=LINE('',#1324,#1323);
#1326=EDGE_CURVE('E544',#706,#1319,#1325,.T.);
#1327=ORIENTED_EDGE('',*,*,#1326,.F.);
#1328=ORIENTED_EDGE('',*,*,#707,.T.);
#1329=DIRECTION('',(0.,0.,1.));
#1330=VECTOR('',#1329,1.);
#1331=CARTESIAN_POINT('',(-19.0799800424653,-40.5628154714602,-68.807991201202));
#1332=LINE('',#1331,#1330);
#1333=CARTESIAN_POINT('',(-19.0799800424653,-40.5628154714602,-67.270491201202));
#1334=VERTEX_POINT('',#1333);
#1335=EDGE_CURVE('E732',#1334,#702,#1332,.F.);
#1336=ORIENTED_EDGE('',*,*,#1335,.F.);
#1337=DIRECTION('',(-1.,0.,0.));
#1338=VECTOR('',#1337,1.);
#1339=CARTESIAN_POINT('',(-10.8799800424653,-40.5628154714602,-67.270491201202));
#1340=LINE('',#1339,#1338);
#1341=CARTESIAN_POINT('',(-12.9299800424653,-40.5628154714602,-67.270491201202));
#1342=VERTEX_POINT('',#1341);
#1343=EDGE_CURVE('E658',#1342,#1334,#1340,.T.);
#1344=ORIENTED_EDGE('',*,*,#1343,.F.);
#1345=DIRECTION('',(0.,0.,1.));
#1346=VECTOR('',#1345,1.);
#1347=CARTESIAN_POINT('',(-12.9299800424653,-40.5628154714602,-68.807991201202));
#1348=LINE('',#1347,#1346);
#1349=EDGE_CURVE('E735',#538,#1342,#1348,.T.);
#1350=ORIENTED_EDGE('',*,*,#1349,.F.);
#1351=ORIENTED_EDGE('',*,*,#539,.T.);
#1352=EDGE_LOOP('',(#1305,#1313,#1321,#1327,#1328,#1336,#1344,#1350,#1351));
#1353=FACE_BOUND('',#1352,.T.);
#1354=ADVANCED_FACE('F1619',(#1353),#1297,.T.);
#1355=CARTESIAN_POINT('',(-21.1299800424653,-33.3878154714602,-68.807991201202));
#1356=DIRECTION('',(1.,0.,0.));
#1357=DIRECTION('',(0.,-1.,0.));
#1358=AXIS2_PLACEMENT_3D('',#1355,#1356,#1357);
#1359=PLANE('',#1358);
#1360=ORIENTED_EDGE('',*,*,#694,.T.);
#1361=DIRECTION('',(0.,0.,1.));
#1362=VECTOR('',#1361,1.);
#1363=CARTESIAN_POINT('',(-21.1299800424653,-34.1140252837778,-68.807991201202));
#1364=LINE('',#1363,#1362);
#1365=CARTESIAN_POINT('',(-21.1299800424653,-34.1140252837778,-67.270491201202));
#1366=VERTEX_POINT('',#1365);
#1367=EDGE_CURVE('E737',#1366,#685,#1364,.F.);
#1368=ORIENTED_EDGE('',*,*,#1367,.F.);
#1369=DIRECTION('',(0.,1.,0.));
#1370=VECTOR('',#1369,1.);
#1371=CARTESIAN_POINT('',(-21.1299800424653,-33.3878154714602,-67.270491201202));
#1372=LINE('',#1371,#1370);
#1373=CARTESIAN_POINT('',(-21.1299800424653,-38.5128154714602,-67.270491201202));
#1374=VERTEX_POINT('',#1373);
#1375=EDGE_CURVE('E661',#1374,#1366,#1372,.T.);
#1376=ORIENTED_EDGE('',*,*,#1375,.F.);
#1377=DIRECTION('',(0.,0.,1.));
#1378=VECTOR('',#1377,1.);
#1379=CARTESIAN_POINT('',(-21.1299800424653,-38.5128154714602,-68.807991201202));
#1380=LINE('',#1379,#1378);
#1381=EDGE_CURVE('E740',#693,#1374,#1380,.T.);
#1382=ORIENTED_EDGE('',*,*,#1381,.F.);
#1383=EDGE_LOOP('',(#1360,#1368,#1376,#1382));
#1384=FACE_BOUND('',#1383,.T.);
#1385=ADVANCED_FACE('F1623',(#1384),#1359,.T.);
#1386=CARTESIAN_POINT('',(-19.0799800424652,-4.68781547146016,-68.807991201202));
#1387=DIRECTION('',(1.,0.,0.));
#1388=DIRECTION('',(0.,-1.,0.));
#1389=AXIS2_PLACEMENT_3D('',#1386,#1387,#1388);
#1390=PLANE('',#1389);
#1391=ORIENTED_EDGE('',*,*,#668,.T.);
#1392=DIRECTION('',(0.,0.,-1.));
#1393=VECTOR('',#1392,1.);
#1394=CARTESIAN_POINT('',(-19.0799800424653,-10.1116056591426,-68.807991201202));
#1395=LINE('',#1394,#1393);
#1396=CARTESIAN_POINT('',(-19.0799800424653,-10.1116056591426,-67.270491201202));
#1397=VERTEX_POINT('',#1396);
#1398=EDGE_CURVE('E683',#1397,#659,#1395,.T.);
#1399=ORIENTED_EDGE('',*,*,#1398,.F.);
#1400=DIRECTION('',(0.,1.,0.));
#1401=VECTOR('',#1400,1.);
#1402=CARTESIAN_POINT('',(-19.0799800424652,-4.68781547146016,-67.270491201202));
#1403=LINE('',#1402,#1401);
#1404=CARTESIAN_POINT('',(-19.0799800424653,-27.9640252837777,-67.270491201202));
#1405=VERTEX_POINT('',#1404);
#1406=EDGE_CURVE('E664',#1405,#1397,#1403,.T.);
#1407=ORIENTED_EDGE('',*,*,#1406,.F.);
#1408=DIRECTION('',(0.,0.,1.));
#1409=VECTOR('',#1408,1.);
#1410=CARTESIAN_POINT('',(-19.0799800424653,-27.9640252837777,-68.807991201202));
#1411=LINE('',#1410,#1409);
#1412=EDGE_CURVE('E681',#667,#1405,#1411,.T.);
#1413=ORIENTED_EDGE('',*,*,#1412,.F.);
#1414=EDGE_LOOP('',(#1391,#1399,#1407,#1413));
#1415=FACE_BOUND('',#1414,.T.);
#1416=ADVANCED_FACE('F1640',(#1415),#1390,.T.);
#1417=CARTESIAN_POINT('',(-21.1299800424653,2.48718452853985,-68.807991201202));
#1418=DIRECTION('',(1.,0.,0.));
#1419=DIRECTION('',(0.,0.,-1.));
#1420=AXIS2_PLACEMENT_3D('',#1417,#1418,#1419);
#1421=PLANE('',#1420);
#1422=ORIENTED_EDGE('',*,*,#642,.T.);
#1423=DIRECTION('',(0.,0.,1.));
#1424=VECTOR('',#1423,1.);
#1425=CARTESIAN_POINT('',(-21.1299800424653,0.437184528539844,-68.807991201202));
#1426=LINE('',#1425,#1424);
#1427=CARTESIAN_POINT('',(-21.1299800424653,0.437184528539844,-67.270491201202));
#1428=VERTEX_POINT('',#1427);
#1429=EDGE_CURVE('E744',#1428,#633,#1426,.F.);
#1430=ORIENTED_EDGE('',*,*,#1429,.F.);
#1431=DIRECTION('',(0.,1.,0.));
#1432=VECTOR('',#1431,1.);
#1433=CARTESIAN_POINT('',(-21.1299800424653,2.48718452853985,-67.270491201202));
#1434=LINE('',#1433,#1432);
#1435=CARTESIAN_POINT('',(-21.1299800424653,-3.96160565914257,-67.270491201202));
#1436=VERTEX_POINT('',#1435);
#1437=EDGE_CURVE('E667',#1436,#1428,#1434,.T.);
#1438=ORIENTED_EDGE('',*,*,#1437,.F.);
#1439=DIRECTION('',(0.,0.,-1.));
#1440=VECTOR('',#1439,1.);
#1441=CARTESIAN_POINT('',(-21.1299800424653,-3.96160565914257,-68.807991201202));
#1442=LINE('',#1441,#1440);
#1443=EDGE_CURVE('E746',#641,#1436,#1442,.F.);
#1444=ORIENTED_EDGE('',*,*,#1443,.F.);
#1445=EDGE_LOOP('',(#1422,#1430,#1438,#1444));
#1446=FACE_BOUND('',#1445,.T.);
#1447=ADVANCED_FACE('F1647',(#1446),#1421,.T.);
#1448=CARTESIAN_POINT('',(-10.8799800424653,2.48718452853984,-68.807991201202));
#1449=DIRECTION('',(0.,-1.,0.));
#1450=DIRECTION('',(0.,0.,1.));
#1451=AXIS2_PLACEMENT_3D('',#1448,#1449,#1450);
#1452=PLANE('',#1451);
#1453=ORIENTED_EDGE('',*,*,#625,.T.);
#1454=DIRECTION('',(0.,0.,1.));
#1455=VECTOR('',#1454,1.);
#1456=CARTESIAN_POINT('',(-12.9299800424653,2.48718452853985,-68.807991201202));
#1457=LINE('',#1456,#1455);
#1458=CARTESIAN_POINT('',(-12.9299800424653,2.48718452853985,-67.270491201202));
#1459=VERTEX_POINT('',#1458);
#1460=EDGE_CURVE('E719',#1459,#616,#1457,.F.);
#1461=ORIENTED_EDGE('',*,*,#1460,.F.);
#1462=DIRECTION('',(1.,0.,0.));
#1463=VECTOR('',#1462,1.);
#1464=CARTESIAN_POINT('',(-10.8799800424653,2.48718452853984,-67.270491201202));
#1465=LINE('',#1464,#1463);
#1466=CARTESIAN_POINT('',(-19.0799800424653,2.48718452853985,-67.270491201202));
#1467=VERTEX_POINT('',#1466);
#1468=EDGE_CURVE('E670',#1467,#1459,#1465,.T.);
#1469=ORIENTED_EDGE('',*,*,#1468,.F.);
#1470=DIRECTION('',(0.,0.,1.));
#1471=VECTOR('',#1470,1.);
#1472=CARTESIAN_POINT('',(-19.0799800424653,2.48718452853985,-68.807991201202));
#1473=LINE('',#1472,#1471);
#1474=EDGE_CURVE('E717',#624,#1467,#1473,.T.);
#1475=ORIENTED_EDGE('',*,*,#1474,.F.);
#1476=EDGE_LOOP('',(#1453,#1461,#1469,#1475));
#1477=FACE_BOUND('',#1476,.T.);
#1478=ADVANCED_FACE('F1655',(#1477),#1452,.T.);
#1479=CARTESIAN_POINT('',(-10.8799800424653,2.48718452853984,-68.807991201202));
#1480=DIRECTION('',(-1.,0.,0.));
#1481=DIRECTION('',(0.,0.,1.));
#1482=AXIS2_PLACEMENT_3D('',#1479,#1480,#1481);
#1483=PLANE('',#1482);
#1484=ORIENTED_EDGE('',*,*,#608,.T.);
#1485=DIRECTION('',(0.,0.,1.));
#1486=VECTOR('',#1485,1.);
#1487=CARTESIAN_POINT('',(-10.8799800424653,-3.96160565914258,-68.807991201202));
#1488=LINE('',#1487,#1486);
#1489=CARTESIAN_POINT('',(-10.8799800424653,-3.96160565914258,-67.270491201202));
#1490=VERTEX_POINT('',#1489);
#1491=EDGE_CURVE('E696',#1490,#599,#1488,.F.);
#1492=ORIENTED_EDGE('',*,*,#1491,.F.);
#1493=DIRECTION('',(0.,-1.,0.));
#1494=VECTOR('',#1493,1.);
#1495=CARTESIAN_POINT('',(-10.8799800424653,2.48718452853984,-67.270491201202));
#1496=LINE('',#1495,#1494);
#1497=CARTESIAN_POINT('',(-10.8799800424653,0.437184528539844,-67.270491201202));
#1498=VERTEX_POINT('',#1497);
#1499=EDGE_CURVE('E673',#1498,#1490,#1496,.T.);
#1500=ORIENTED_EDGE('',*,*,#1499,.F.);
#1501=DIRECTION('',(0.,0.,1.));
#1502=VECTOR('',#1501,1.);
#1503=CARTESIAN_POINT('',(-10.8799800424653,0.437184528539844,-68.807991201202));
#1504=LINE('',#1503,#1502);
#1505=EDGE_CURVE('E699',#607,#1498,#1504,.T.);
#1506=ORIENTED_EDGE('',*,*,#1505,.F.);
#1507=EDGE_LOOP('',(#1484,#1492,#1500,#1506));
#1508=FACE_BOUND('',#1507,.T.);
#1509=ADVANCED_FACE('F1663',(#1508),#1483,.T.);
#1510=CARTESIAN_POINT('',(-4.72998004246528,-10.1116056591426,-68.807991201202));
#1511=DIRECTION('',(0.,0.,1.));
#1512=DIRECTION('',(1.,0.,0.));
#1513=AXIS2_PLACEMENT_3D('',#1510,#1511,#1512);
#1514=CYLINDRICAL_SURFACE('',#1513,8.2);
#1515=ORIENTED_EDGE('',*,*,#591,.T.);
#1516=ORIENTED_EDGE('',*,*,#1257,.T.);
#1517=CARTESIAN_POINT('',(-4.72998004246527,-10.1116056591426,-67.270491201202));
#1518=DIRECTION('',(0.,0.,1.));
#1519=DIRECTION('',(1.,0.,0.));
#1520=AXIS2_PLACEMENT_3D('',#1517,#1518,#1519);
#1521=CIRCLE('',#1520,8.2);
#1522=CARTESIAN_POINT('',(-11.2899800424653,-5.19160565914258,-67.270491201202));
#1523=VERTEX_POINT('',#1522);
#1524=EDGE_CURVE('E686',#1250,#1523,#1521,.F.);
#1525=ORIENTED_EDGE('',*,*,#1524,.T.);
#1526=DIRECTION('',(0.,0.,1.));
#1527=VECTOR('',#1526,1.);
#1528=CARTESIAN_POINT('',(-11.2899800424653,-5.19160565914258,-68.807991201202));
#1529=LINE('',#1528,#1527);
#1530=EDGE_CURVE('E722',#590,#1523,#1529,.T.);
#1531=ORIENTED_EDGE('',*,*,#1530,.F.);
#1532=EDGE_LOOP('',(#1515,#1516,#1525,#1531));
#1533=FACE_BOUND('',#1532,.T.);
#1534=ADVANCED_FACE('F1671',(#1533),#1514,.T.);
#1535=CARTESIAN_POINT('',(-27.2799800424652,-10.1116056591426,-68.807991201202));
#1536=DIRECTION('',(0.,0.,-1.));
#1537=DIRECTION('',(-1.,0.,0.));
#1538=AXIS2_PLACEMENT_3D('',#1535,#1536,#1537);
#1539=CYLINDRICAL_SURFACE('',#1538,8.2);
#1540=ORIENTED_EDGE('',*,*,#660,.T.);
#1541=DIRECTION('',(0.,0.,-1.));
#1542=VECTOR('',#1541,1.);
#1543=CARTESIAN_POINT('',(-20.7199800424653,-5.19160565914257,-68.807991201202));
#1544=LINE('',#1543,#1542);
#1545=CARTESIAN_POINT('',(-20.7199800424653,-5.19160565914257,-67.270491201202));
#1546=VERTEX_POINT('',#1545);
#1547=EDGE_CURVE('E748',#1546,#650,#1544,.T.);
#1548=ORIENTED_EDGE('',*,*,#1547,.F.);
#1549=CARTESIAN_POINT('',(-27.2799800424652,-10.1116056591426,-67.2704912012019));
#1550=DIRECTION('',(0.,0.,1.));
#1551=DIRECTION('',(1.,0.,0.));
#1552=AXIS2_PLACEMENT_3D('',#1549,#1550,#1551);
#1553=CIRCLE('',#1552,8.2);
#1554=EDGE_CURVE('E689',#1546,#1397,#1553,.F.);
#1555=ORIENTED_EDGE('',*,*,#1554,.T.);
#1556=ORIENTED_EDGE('',*,*,#1398,.T.);
#1557=EDGE_LOOP('',(#1540,#1548,#1555,#1556));
#1558=FACE_BOUND('',#1557,.T.);
#1559=ADVANCED_FACE('F1679',(#1558),#1539,.T.);
#1560=CARTESIAN_POINT('',(-27.2799800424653,-27.9640252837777,-68.8079912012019));
#1561=DIRECTION('',(0.,0.,1.));
#1562=DIRECTION('',(1.,0.,0.));
#1563=AXIS2_PLACEMENT_3D('',#1560,#1561,#1562);
#1564=CYLINDRICAL_SURFACE('',#1563,8.2);
#1565=ORIENTED_EDGE('',*,*,#677,.T.);
#1566=ORIENTED_EDGE('',*,*,#1412,.T.);
#1567=CARTESIAN_POINT('',(-27.2799800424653,-27.9640252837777,-67.2704912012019));
#1568=DIRECTION('',(0.,0.,1.));
#1569=DIRECTION('',(1.,0.,0.));
#1570=AXIS2_PLACEMENT_3D('',#1567,#1568,#1569);
#1571=CIRCLE('',#1570,8.2);
#1572=CARTESIAN_POINT('',(-20.7199800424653,-32.8840252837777,-67.270491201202));
#1573=VERTEX_POINT('',#1572);
#1574=EDGE_CURVE('E691',#1405,#1573,#1571,.F.);
#1575=ORIENTED_EDGE('',*,*,#1574,.T.);
#1576=DIRECTION('',(0.,0.,1.));
#1577=VECTOR('',#1576,1.);
#1578=CARTESIAN_POINT('',(-20.7199800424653,-32.8840252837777,-68.807991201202));
#1579=LINE('',#1578,#1577);
#1580=EDGE_CURVE('E742',#676,#1573,#1579,.T.);
#1581=ORIENTED_EDGE('',*,*,#1580,.F.);
#1582=EDGE_LOOP('',(#1565,#1566,#1575,#1581));
#1583=FACE_BOUND('',#1582,.T.);
#1584=ADVANCED_FACE('F1687',(#1583),#1564,.T.);
#1585=CARTESIAN_POINT('',(-4.72998004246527,-27.9640252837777,-68.807991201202));
#1586=DIRECTION('',(0.,0.,-1.));
#1587=DIRECTION('',(-1.,0.,0.));
#1588=AXIS2_PLACEMENT_3D('',#1585,#1586,#1587);
#1589=CYLINDRICAL_SURFACE('',#1588,8.2);
#1590=ORIENTED_EDGE('',*,*,#574,.T.);
#1591=DIRECTION('',(0.,0.,-1.));
#1592=VECTOR('',#1591,1.);
#1593=CARTESIAN_POINT('',(-11.2899800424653,-32.8840252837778,-68.807991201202));
#1594=LINE('',#1593,#1592);
#1595=CARTESIAN_POINT('',(-11.2899800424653,-32.8840252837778,-67.270491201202));
#1596=VERTEX_POINT('',#1595);
#1597=EDGE_CURVE('E729',#1596,#564,#1594,.T.);
#1598=ORIENTED_EDGE('',*,*,#1597,.F.);
#1599=CARTESIAN_POINT('',(-4.72998004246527,-27.9640252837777,-67.270491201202));
#1600=DIRECTION('',(0.,0.,1.));
#1601=DIRECTION('',(1.,0.,0.));
#1602=AXIS2_PLACEMENT_3D('',#1599,#1600,#1601);
#1603=CIRCLE('',#1602,8.2);
#1604=EDGE_CURVE('E694',#1596,#1242,#1603,.F.);
#1605=ORIENTED_EDGE('',*,*,#1604,.T.);
#1606=ORIENTED_EDGE('',*,*,#1243,.T.);
#1607=EDGE_LOOP('',(#1590,#1598,#1605,#1606));
#1608=FACE_BOUND('',#1607,.T.);
#1609=ADVANCED_FACE('F1695',(#1608),#1589,.T.);
#1610=CARTESIAN_POINT('',(-12.9299800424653,0.437184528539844,-68.807991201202));
#1611=DIRECTION('',(0.,0.,1.));
#1612=DIRECTION('',(1.,0.,0.));
#1613=AXIS2_PLACEMENT_3D('',#1610,#1611,#1612);
#1614=CYLINDRICAL_SURFACE('',#1613,2.05);
#1615=ORIENTED_EDGE('',*,*,#1505,.T.);
#1616=CARTESIAN_POINT('',(-12.9299800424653,0.437184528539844,-67.270491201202));
#1617=DIRECTION('',(0.,0.,1.));
#1618=DIRECTION('',(1.,0.,0.));
#1619=AXIS2_PLACEMENT_3D('',#1616,#1617,#1618);
#1620=CIRCLE('',#1619,2.05);
#1621=EDGE_CURVE('E715',#1498,#1459,#1620,.T.);
#1622=ORIENTED_EDGE('',*,*,#1621,.T.);
#1623=ORIENTED_EDGE('',*,*,#1460,.T.);
#1624=ORIENTED_EDGE('',*,*,#617,.F.);
#1625=EDGE_LOOP('',(#1615,#1622,#1623,#1624));
#1626=FACE_BOUND('',#1625,.T.);
#1627=ADVANCED_FACE('F1703',(#1626),#1614,.F.);
#1628=CARTESIAN_POINT('',(-12.9299800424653,-3.96160565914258,-68.807991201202));
#1629=DIRECTION('',(0.,0.,1.));
#1630=DIRECTION('',(1.,0.,0.));
#1631=AXIS2_PLACEMENT_3D('',#1628,#1629,#1630);
#1632=CYLINDRICAL_SURFACE('',#1631,2.05);
#1633=ORIENTED_EDGE('',*,*,#1530,.T.);
#1634=CARTESIAN_POINT('',(-12.9299800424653,-3.96160565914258,-67.270491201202));
#1635=DIRECTION('',(0.,0.,1.));
#1636=DIRECTION('',(1.,0.,0.));
#1637=AXIS2_PLACEMENT_3D('',#1634,#1635,#1636);
#1638=CIRCLE('',#1637,2.05);
#1639=EDGE_CURVE('E713',#1523,#1490,#1638,.T.);
#1640=ORIENTED_EDGE('',*,*,#1639,.T.);
#1641=ORIENTED_EDGE('',*,*,#1491,.T.);
#1642=ORIENTED_EDGE('',*,*,#600,.F.);
#1643=EDGE_LOOP('',(#1633,#1640,#1641,#1642));
#1644=FACE_BOUND('',#1643,.T.);
#1645=ADVANCED_FACE('F1711',(#1644),#1632,.F.);
#1646=CARTESIAN_POINT('',(-12.9299800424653,-34.1140252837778,-68.807991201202));
#1647=DIRECTION('',(0.,0.,-1.));
#1648=DIRECTION('',(-1.,0.,0.));
#1649=AXIS2_PLACEMENT_3D('',#1646,#1647,#1648);
#1650=CYLINDRICAL_SURFACE('',#1649,2.05);
#1651=ORIENTED_EDGE('',*,*,#1288,.T.);
#1652=CARTESIAN_POINT('',(-12.9299800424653,-34.1140252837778,-67.270491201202));
#1653=DIRECTION('',(0.,0.,1.));
#1654=DIRECTION('',(1.,0.,0.));
#1655=AXIS2_PLACEMENT_3D('',#1652,#1653,#1654);
#1656=CIRCLE('',#1655,2.05);
#1657=EDGE_CURVE('E711',#1281,#1596,#1656,.T.);
#1658=ORIENTED_EDGE('',*,*,#1657,.T.);
#1659=ORIENTED_EDGE('',*,*,#1597,.T.);
#1660=ORIENTED_EDGE('',*,*,#565,.F.);
#1661=EDGE_LOOP('',(#1651,#1658,#1659,#1660));
#1662=FACE_BOUND('',#1661,.T.);
#1663=ADVANCED_FACE('F1719',(#1662),#1650,.F.);
#1664=CARTESIAN_POINT('',(-12.9299800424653,-38.5128154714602,-68.807991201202));
#1665=DIRECTION('',(0.,0.,1.));
#1666=DIRECTION('',(1.,0.,0.));
#1667=AXIS2_PLACEMENT_3D('',#1664,#1665,#1666);
#1668=CYLINDRICAL_SURFACE('',#1667,2.05);
#1669=ORIENTED_EDGE('',*,*,#1349,.T.);
#1670=CARTESIAN_POINT('',(-12.9299800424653,-38.5128154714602,-67.270491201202));
#1671=DIRECTION('',(0.,0.,1.));
#1672=DIRECTION('',(1.,0.,0.));
#1673=AXIS2_PLACEMENT_3D('',#1670,#1671,#1672);
#1674=CIRCLE('',#1673,2.05);
#1675=EDGE_CURVE('E709',#1342,#1273,#1674,.T.);
#1676=ORIENTED_EDGE('',*,*,#1675,.T.);
#1677=ORIENTED_EDGE('',*,*,#1274,.T.);
#1678=ORIENTED_EDGE('',*,*,#548,.F.);
#1679=EDGE_LOOP('',(#1669,#1676,#1677,#1678));
#1680=FACE_BOUND('',#1679,.T.);
#1681=ADVANCED_FACE('F1727',(#1680),#1668,.F.);
#1682=CARTESIAN_POINT('',(-19.0799800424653,-38.5128154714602,-68.807991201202));
#1683=DIRECTION('',(0.,0.,1.));
#1684=DIRECTION('',(1.,0.,0.));
#1685=AXIS2_PLACEMENT_3D('',#1682,#1683,#1684);
#1686=CYLINDRICAL_SURFACE('',#1685,2.05);
#1687=ORIENTED_EDGE('',*,*,#1381,.T.);
#1688=CARTESIAN_POINT('',(-19.0799800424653,-38.5128154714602,-67.270491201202));
#1689=DIRECTION('',(0.,0.,1.));
#1690=DIRECTION('',(1.,0.,0.));
#1691=AXIS2_PLACEMENT_3D('',#1688,#1689,#1690);
#1692=CIRCLE('',#1691,2.05);
#1693=EDGE_CURVE('E707',#1374,#1334,#1692,.T.);
#1694=ORIENTED_EDGE('',*,*,#1693,.T.);
#1695=ORIENTED_EDGE('',*,*,#1335,.T.);
#1696=ORIENTED_EDGE('',*,*,#703,.F.);
#1697=EDGE_LOOP('',(#1687,#1694,#1695,#1696));
#1698=FACE_BOUND('',#1697,.T.);
#1699=ADVANCED_FACE('F1735',(#1698),#1686,.F.);
#1700=CARTESIAN_POINT('',(-19.0799800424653,-34.1140252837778,-68.807991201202));
#1701=DIRECTION('',(0.,0.,1.));
#1702=DIRECTION('',(1.,0.,0.));
#1703=AXIS2_PLACEMENT_3D('',#1700,#1701,#1702);
#1704=CYLINDRICAL_SURFACE('',#1703,2.05);
#1705=ORIENTED_EDGE('',*,*,#1580,.T.);
#1706=CARTESIAN_POINT('',(-19.0799800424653,-34.1140252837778,-67.270491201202));
#1707=DIRECTION('',(0.,0.,1.));
#1708=DIRECTION('',(1.,0.,0.));
#1709=AXIS2_PLACEMENT_3D('',#1706,#1707,#1708);
#1710=CIRCLE('',#1709,2.05);
#1711=EDGE_CURVE('E705',#1573,#1366,#1710,.T.);
#1712=ORIENTED_EDGE('',*,*,#1711,.T.);
#1713=ORIENTED_EDGE('',*,*,#1367,.T.);
#1714=ORIENTED_EDGE('',*,*,#686,.F.);
#1715=EDGE_LOOP('',(#1705,#1712,#1713,#1714));
#1716=FACE_BOUND('',#1715,.T.);
#1717=ADVANCED_FACE('F1743',(#1716),#1704,.F.);
#1718=CARTESIAN_POINT('',(-19.0799800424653,-3.96160565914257,-68.807991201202));
#1719=DIRECTION('',(0.,0.,-1.));
#1720=DIRECTION('',(-1.,0.,0.));
#1721=AXIS2_PLACEMENT_3D('',#1718,#1719,#1720);
#1722=CYLINDRICAL_SURFACE('',#1721,2.05);
#1723=ORIENTED_EDGE('',*,*,#1443,.T.);
#1724=CARTESIAN_POINT('',(-19.0799800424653,-3.96160565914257,-67.270491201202));
#1725=DIRECTION('',(0.,0.,1.));
#1726=DIRECTION('',(1.,0.,0.));
#1727=AXIS2_PLACEMENT_3D('',#1724,#1725,#1726);
#1728=CIRCLE('',#1727,2.05);
#1729=EDGE_CURVE('E703',#1436,#1546,#1728,.T.);
#1730=ORIENTED_EDGE('',*,*,#1729,.T.);
#1731=ORIENTED_EDGE('',*,*,#1547,.T.);
#1732=ORIENTED_EDGE('',*,*,#651,.F.);
#1733=EDGE_LOOP('',(#1723,#1730,#1731,#1732));
#1734=FACE_BOUND('',#1733,.T.);
#1735=ADVANCED_FACE('F1751',(#1734),#1722,.F.);
#1736=CARTESIAN_POINT('',(-19.0799800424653,0.437184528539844,-68.807991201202));
#1737=DIRECTION('',(0.,0.,1.));
#1738=DIRECTION('',(1.,0.,0.));
#1739=AXIS2_PLACEMENT_3D('',#1736,#1737,#1738);
#1740=CYLINDRICAL_SURFACE('',#1739,2.05);
#1741=ORIENTED_EDGE('',*,*,#1474,.T.);
#1742=CARTESIAN_POINT('',(-19.0799800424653,0.437184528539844,-67.270491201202));
#1743=DIRECTION('',(0.,0.,1.));
#1744=DIRECTION('',(1.,0.,0.));
#1745=AXIS2_PLACEMENT_3D('',#1742,#1743,#1744);
#1746=CIRCLE('',#1745,2.05);
#1747=EDGE_CURVE('E701',#1467,#1428,#1746,.T.);
#1748=ORIENTED_EDGE('',*,*,#1747,.T.);
#1749=ORIENTED_EDGE('',*,*,#1429,.T.);
#1750=ORIENTED_EDGE('',*,*,#634,.F.);
#1751=EDGE_LOOP('',(#1741,#1748,#1749,#1750));
#1752=FACE_BOUND('',#1751,.T.);
#1753=ADVANCED_FACE('F1759',(#1752),#1740,.F.);
#1754=CARTESIAN_POINT('',(-16.0049800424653,-13.9128154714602,-67.270491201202));
#1755=DIRECTION('',(0.,0.,1.));
#1756=DIRECTION('',(1.,0.,0.));
#1757=AXIS2_PLACEMENT_3D('',#1754,#1755,#1756);
#1758=PLANE('',#1757);
#1759=ORIENTED_EDGE('',*,*,#1499,.T.);
#1760=ORIENTED_EDGE('',*,*,#1639,.F.);
#1761=ORIENTED_EDGE('',*,*,#1524,.F.);
#1762=ORIENTED_EDGE('',*,*,#1251,.T.);
#1763=ORIENTED_EDGE('',*,*,#1604,.F.);
#1764=ORIENTED_EDGE('',*,*,#1657,.F.);
#1765=ORIENTED_EDGE('',*,*,#1282,.T.);
#1766=ORIENTED_EDGE('',*,*,#1675,.F.);
#1767=ORIENTED_EDGE('',*,*,#1343,.T.);
#1768=ORIENTED_EDGE('',*,*,#1693,.F.);
#1769=ORIENTED_EDGE('',*,*,#1375,.T.);
#1770=ORIENTED_EDGE('',*,*,#1711,.F.);
#1771=ORIENTED_EDGE('',*,*,#1574,.F.);
#1772=ORIENTED_EDGE('',*,*,#1406,.T.);
#1773=ORIENTED_EDGE('',*,*,#1554,.F.);
#1774=ORIENTED_EDGE('',*,*,#1729,.F.);
#1775=ORIENTED_EDGE('',*,*,#1437,.T.);
#1776=ORIENTED_EDGE('',*,*,#1747,.F.);
#1777=ORIENTED_EDGE('',*,*,#1468,.T.);
#1778=ORIENTED_EDGE('',*,*,#1621,.F.);
#1779=EDGE_LOOP('',(#1759,#1760,#1761,#1762,#1763,#1764,#1765,#1766,#1767,#1768,#1769,#1770,
#1771,#1772,#1773,#1774,#1775,#1776,#1777,#1778));
#1780=FACE_BOUND('',#1779,.T.);
#1781=ADVANCED_FACE('F1264',(#1780),#1758,.F.);
#1782=CARTESIAN_POINT('',(-41.0799800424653,-4.68781547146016,-67.270491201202));
#1783=DIRECTION('',(1.,0.,0.));
#1784=DIRECTION('',(0.,1.,0.));
#1785=AXIS2_PLACEMENT_3D('',#1782,#1783,#1784);
#1786=PLANE('',#1785);
#1787=ORIENTED_EDGE('',*,*,#449,.T.);
#1788=DIRECTION('',(0.,0.,-1.));
#1789=VECTOR('',#1788,1.);
#1790=CARTESIAN_POINT('',(-41.0799800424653,-10.1116056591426,-67.270491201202));
#1791=LINE('',#1790,#1789);
#1792=CARTESIAN_POINT('',(-41.0799800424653,-10.1116056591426,-67.270491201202));
#1793=VERTEX_POINT('',#1792);
#1794=EDGE_CURVE('E579',#1793,#440,#1791,.T.);
#1795=ORIENTED_EDGE('',*,*,#1794,.F.);
#1796=DIRECTION('',(0.,-1.,0.));
#1797=VECTOR('',#1796,1.);
#1798=CARTESIAN_POINT('',(-41.0799800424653,-4.68781547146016,-67.270491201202));
#1799=LINE('',#1798,#1797);
#1800=CARTESIAN_POINT('',(-41.0799800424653,-27.9640252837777,-67.270491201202));
#1801=VERTEX_POINT('',#1800);
#1802=EDGE_CURVE('E552',#1793,#1801,#1799,.T.);
#1803=ORIENTED_EDGE('',*,*,#1802,.T.);
#1804=DIRECTION('',(0.,0.,1.));
#1805=VECTOR('',#1804,1.);
#1806=CARTESIAN_POINT('',(-41.0799800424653,-27.9640252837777,-67.270491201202));
#1807=LINE('',#1806,#1805);
#1808=EDGE_CURVE('E577',#448,#1801,#1807,.T.);
#1809=ORIENTED_EDGE('',*,*,#1808,.F.);
#1810=EDGE_LOOP('',(#1787,#1795,#1803,#1809));
#1811=FACE_BOUND('',#1810,.T.);
#1812=ADVANCED_FACE('F1245',(#1811),#1786,.T.);
#1813=CARTESIAN_POINT('',(-43.1299800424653,-33.3878154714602,-67.270491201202));
#1814=DIRECTION('',(1.,0.,0.));
#1815=DIRECTION('',(0.,1.,0.));
#1816=AXIS2_PLACEMENT_3D('',#1813,#1814,#1815);
#1817=PLANE('',#1816);
#1818=ORIENTED_EDGE('',*,*,#475,.T.);
#1819=DIRECTION('',(0.,0.,1.));
#1820=VECTOR('',#1819,1.);
#1821=CARTESIAN_POINT('',(-43.1299800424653,-34.1140252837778,-67.270491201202));
#1822=LINE('',#1821,#1820);
#1823=CARTESIAN_POINT('',(-43.1299800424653,-34.1140252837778,-67.270491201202));
#1824=VERTEX_POINT('',#1823);
#1825=EDGE_CURVE('E627',#1824,#466,#1822,.F.);
#1826=ORIENTED_EDGE('',*,*,#1825,.F.);
#1827=DIRECTION('',(0.,-1.,0.));
#1828=VECTOR('',#1827,1.);
#1829=CARTESIAN_POINT('',(-43.1299800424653,-33.3878154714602,-67.270491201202));
#1830=LINE('',#1829,#1828);
#1831=CARTESIAN_POINT('',(-43.1299800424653,-38.5128154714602,-67.270491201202));
#1832=VERTEX_POINT('',#1831);
#1833=EDGE_CURVE('E555',#1824,#1832,#1830,.T.);
#1834=ORIENTED_EDGE('',*,*,#1833,.T.);
#1835=DIRECTION('',(0.,0.,-1.));
#1836=VECTOR('',#1835,1.);
#1837=CARTESIAN_POINT('',(-43.1299800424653,-38.5128154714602,-67.270491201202));
#1838=LINE('',#1837,#1836);
#1839=EDGE_CURVE('E625',#474,#1832,#1838,.F.);
#1840=ORIENTED_EDGE('',*,*,#1839,.F.);
#1841=EDGE_LOOP('',(#1818,#1826,#1834,#1840));
#1842=FACE_BOUND('',#1841,.T.);
#1843=ADVANCED_FACE('F1256',(#1842),#1817,.T.);
#1844=CARTESIAN_POINT('',(-43.1299800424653,-40.5628154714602,-67.270491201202));
#1845=DIRECTION('',(0.,1.,0.));
#1846=DIRECTION('',(0.,0.,1.));
#1847=AXIS2_PLACEMENT_3D('',#1844,#1845,#1846);
#1848=PLANE('',#1847);
#1849=DIRECTION('',(0.173648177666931,0.,-0.984807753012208));
#1850=VECTOR('',#1849,1.);
#1851=CARTESIAN_POINT('',(-35.61174833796,-40.5628154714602,-65.9448241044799));
#1852=LINE('',#1851,#1850);
#1853=CARTESIAN_POINT('',(-35.2424460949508,-40.5628154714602,-68.039241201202));
#1854=VERTEX_POINT('',#1853);
#1855=EDGE_CURVE('E503',#1854,#311,#1852,.T.);
#1856=ORIENTED_EDGE('',*,*,#1855,.F.);
#1857=DIRECTION('',(-1.,0.,0.));
#1858=VECTOR('',#1857,1.);
#1859=CARTESIAN_POINT('',(-43.1299800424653,-40.5628154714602,-68.039241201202));
#1860=LINE('',#1859,#1858);
#1861=CARTESIAN_POINT('',(-35.7250847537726,-40.5628154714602,-68.039241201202));
#1862=VERTEX_POINT('',#1861);
#1863=EDGE_CURVE('E491',#1854,#1862,#1860,.T.);
#1864=ORIENTED_EDGE('',*,*,#1863,.T.);
#1865=DIRECTION('',(0.173648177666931,0.,0.984807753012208));
#1866=VECTOR('',#1865,1.);
#1867=CARTESIAN_POINT('',(-35.8169056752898,-40.5628154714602,-68.5599835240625));
#1868=LINE('',#1867,#1866);
#1869=EDGE_CURVE('E517',#487,#1862,#1868,.T.);
#1870=ORIENTED_EDGE('',*,*,#1869,.F.);
#1871=ORIENTED_EDGE('',*,*,#488,.T.);
#1872=DIRECTION('',(0.,0.,-1.));
#1873=VECTOR('',#1872,1.);
#1874=CARTESIAN_POINT('',(-41.0799800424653,-40.5628154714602,-67.270491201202));
#1875=LINE('',#1874,#1873);
#1876=CARTESIAN_POINT('',(-41.0799800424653,-40.5628154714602,-67.270491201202));
#1877=VERTEX_POINT('',#1876);
#1878=EDGE_CURVE('E634',#1877,#483,#1875,.T.);
#1879=ORIENTED_EDGE('',*,*,#1878,.F.);
#1880=DIRECTION('',(1.,0.,0.));
#1881=VECTOR('',#1880,1.);
#1882=CARTESIAN_POINT('',(-43.1299800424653,-40.5628154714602,-67.270491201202));
#1883=LINE('',#1882,#1881);
#1884=CARTESIAN_POINT('',(-34.9299800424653,-40.5628154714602,-67.270491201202));
#1885=VERTEX_POINT('',#1884);
#1886=EDGE_CURVE('E559',#1877,#1885,#1883,.T.);
#1887=ORIENTED_EDGE('',*,*,#1886,.T.);
#1888=DIRECTION('',(0.,0.,-1.));
#1889=VECTOR('',#1888,1.);
#1890=CARTESIAN_POINT('',(-34.9299800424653,-40.5628154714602,-67.270491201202));
#1891=LINE('',#1890,#1889);
#1892=EDGE_CURVE('E632',#319,#1885,#1891,.F.);
#1893=ORIENTED_EDGE('',*,*,#1892,.F.);
#1894=ORIENTED_EDGE('',*,*,#320,.T.);
#1895=EDGE_LOOP('',(#1856,#1864,#1870,#1871,#1879,#1887,#1893,#1894));
#1896=FACE_BOUND('',#1895,.T.);
#1897=ADVANCED_FACE('F510',(#1896),#1848,.T.);
#1898=CARTESIAN_POINT('',(-32.8799800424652,-33.3878154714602,-67.270491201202));
#1899=DIRECTION('',(-1.,0.,0.));
#1900=DIRECTION('',(0.,-1.,0.));
#1901=AXIS2_PLACEMENT_3D('',#1898,#1899,#1900);
#1902=PLANE('',#1901);
#1903=ORIENTED_EDGE('',*,*,#337,.T.);
#1904=DIRECTION('',(0.,0.,-1.));
#1905=VECTOR('',#1904,1.);
#1906=CARTESIAN_POINT('',(-32.8799800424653,-38.5128154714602,-67.270491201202));
#1907=LINE('',#1906,#1905);
#1908=CARTESIAN_POINT('',(-32.8799800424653,-38.5128154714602,-67.270491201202));
#1909=VERTEX_POINT('',#1908);
#1910=EDGE_CURVE('E639',#1909,#328,#1907,.T.);
#1911=ORIENTED_EDGE('',*,*,#1910,.F.);
#1912=DIRECTION('',(0.,1.,0.));
#1913=VECTOR('',#1912,1.);
#1914=CARTESIAN_POINT('',(-32.8799800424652,-33.3878154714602,-67.270491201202));
#1915=LINE('',#1914,#1913);
#1916=CARTESIAN_POINT('',(-32.8799800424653,-34.1140252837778,-67.270491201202));
#1917=VERTEX_POINT('',#1916);
#1918=EDGE_CURVE('E562',#1909,#1917,#1915,.T.);
#1919=ORIENTED_EDGE('',*,*,#1918,.T.);
#1920=DIRECTION('',(0.,0.,-1.));
#1921=VECTOR('',#1920,1.);
#1922=CARTESIAN_POINT('',(-32.8799800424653,-34.1140252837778,-67.270491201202));
#1923=LINE('',#1922,#1921);
#1924=EDGE_CURVE('E637',#336,#1917,#1923,.F.);
#1925=ORIENTED_EDGE('',*,*,#1924,.F.);
#1926=EDGE_LOOP('',(#1903,#1911,#1919,#1925));
#1927=FACE_BOUND('',#1926,.T.);
#1928=ADVANCED_FACE('F1187',(#1927),#1902,.T.);
#1929=CARTESIAN_POINT('',(-34.9299800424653,-4.68781547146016,-67.270491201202));
#1930=DIRECTION('',(-1.,0.,0.));
#1931=DIRECTION('',(0.,-1.,0.));
#1932=AXIS2_PLACEMENT_3D('',#1929,#1930,#1931);
#1933=PLANE('',#1932);
#1934=ORIENTED_EDGE('',*,*,#363,.T.);
#1935=DIRECTION('',(0.,0.,-1.));
#1936=VECTOR('',#1935,1.);
#1937=CARTESIAN_POINT('',(-34.9299800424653,-27.9640252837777,-67.270491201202));
#1938=LINE('',#1937,#1936);
#1939=CARTESIAN_POINT('',(-34.9299800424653,-27.9640252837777,-67.270491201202));
#1940=VERTEX_POINT('',#1939);
#1941=EDGE_CURVE('E582',#1940,#354,#1938,.T.);
#1942=ORIENTED_EDGE('',*,*,#1941,.F.);
#1943=DIRECTION('',(0.,1.,0.));
#1944=VECTOR('',#1943,1.);
#1945=CARTESIAN_POINT('',(-34.9299800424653,-4.68781547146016,-67.270491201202));
#1946=LINE('',#1945,#1944);
#1947=CARTESIAN_POINT('',(-34.9299800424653,-10.1116056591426,-67.270491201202));
#1948=VERTEX_POINT('',#1947);
#1949=EDGE_CURVE('E565',#1940,#1948,#1946,.T.);
#1950=ORIENTED_EDGE('',*,*,#1949,.T.);
#1951=DIRECTION('',(0.,0.,1.));
#1952=VECTOR('',#1951,1.);
#1953=CARTESIAN_POINT('',(-34.9299800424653,-10.1116056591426,-67.270491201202));
#1954=LINE('',#1953,#1952);
#1955=EDGE_CURVE('E585',#362,#1948,#1954,.T.);
#1956=ORIENTED_EDGE('',*,*,#1955,.F.);
#1957=EDGE_LOOP('',(#1934,#1942,#1950,#1956));
#1958=FACE_BOUND('',#1957,.T.);
#1959=ADVANCED_FACE('F1201',(#1958),#1933,.T.);
#1960=CARTESIAN_POINT('',(-32.8799800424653,2.48718452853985,-67.270491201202));
#1961=DIRECTION('',(-1.,0.,0.));
#1962=DIRECTION('',(0.,0.,1.));
#1963=AXIS2_PLACEMENT_3D('',#1960,#1961,#1962);
#1964=PLANE('',#1963);
#1965=ORIENTED_EDGE('',*,*,#389,.T.);
#1966=DIRECTION('',(0.,0.,1.));
#1967=VECTOR('',#1966,1.);
#1968=CARTESIAN_POINT('',(-32.8799800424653,-3.96160565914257,-67.270491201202));
#1969=LINE('',#1968,#1967);
#1970=CARTESIAN_POINT('',(-32.8799800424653,-3.96160565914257,-67.270491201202));
#1971=VERTEX_POINT('',#1970);
#1972=EDGE_CURVE('E647',#1971,#380,#1969,.F.);
#1973=ORIENTED_EDGE('',*,*,#1972,.F.);
#1974=DIRECTION('',(0.,1.,0.));
#1975=VECTOR('',#1974,1.);
#1976=CARTESIAN_POINT('',(-32.8799800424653,2.48718452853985,-67.270491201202));
#1977=LINE('',#1976,#1975);
#1978=CARTESIAN_POINT('',(-32.8799800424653,0.437184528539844,-67.270491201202));
#1979=VERTEX_POINT('',#1978);
#1980=EDGE_CURVE('E568',#1971,#1979,#1977,.T.);
#1981=ORIENTED_EDGE('',*,*,#1980,.T.);
#1982=DIRECTION('',(0.,0.,-1.));
#1983=VECTOR('',#1982,1.);
#1984=CARTESIAN_POINT('',(-32.8799800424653,0.437184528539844,-67.270491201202));
#1985=LINE('',#1984,#1983);
#1986=EDGE_CURVE('E645',#388,#1979,#1985,.F.);
#1987=ORIENTED_EDGE('',*,*,#1986,.F.);
#1988=EDGE_LOOP('',(#1965,#1973,#1981,#1987));
#1989=FACE_BOUND('',#1988,.T.);
#1990=ADVANCED_FACE('F1215',(#1989),#1964,.T.);
#1991=CARTESIAN_POINT('',(-43.1299800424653,2.48718452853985,-67.270491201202));
#1992=DIRECTION('',(0.,-1.,0.));
#1993=DIRECTION('',(0.,0.,-1.));
#1994=AXIS2_PLACEMENT_3D('',#1991,#1992,#1993);
#1995=PLANE('',#1994);
#1996=ORIENTED_EDGE('',*,*,#406,.T.);
#1997=DIRECTION('',(0.,0.,-1.));
#1998=VECTOR('',#1997,1.);
#1999=CARTESIAN_POINT('',(-34.9299800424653,2.48718452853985,-67.270491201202));
#2000=LINE('',#1999,#1998);
#2001=CARTESIAN_POINT('',(-34.9299800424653,2.48718452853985,-67.270491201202));
#2002=VERTEX_POINT('',#2001);
#2003=EDGE_CURVE('E602',#2002,#397,#2000,.T.);
#2004=ORIENTED_EDGE('',*,*,#2003,.F.);
#2005=DIRECTION('',(-1.,0.,0.));
#2006=VECTOR('',#2005,1.);
#2007=CARTESIAN_POINT('',(-43.1299800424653,2.48718452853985,-67.270491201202));
#2008=LINE('',#2007,#2006);
#2009=CARTESIAN_POINT('',(-41.0799800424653,2.48718452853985,-67.270491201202));
#2010=VERTEX_POINT('',#2009);
#2011=EDGE_CURVE('E571',#2002,#2010,#2008,.T.);
#2012=ORIENTED_EDGE('',*,*,#2011,.T.);
#2013=DIRECTION('',(0.,0.,-1.));
#2014=VECTOR('',#2013,1.);
#2015=CARTESIAN_POINT('',(-41.0799800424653,2.48718452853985,-67.270491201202));
#2016=LINE('',#2015,#2014);
#2017=EDGE_CURVE('E604',#405,#2010,#2016,.F.);
#2018=ORIENTED_EDGE('',*,*,#2017,.F.);
#2019=EDGE_LOOP('',(#1996,#2004,#2012,#2018));
#2020=FACE_BOUND('',#2019,.T.);
#2021=ADVANCED_FACE('F1222',(#2020),#1995,.T.);
#2022=CARTESIAN_POINT('',(-43.1299800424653,2.48718452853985,-67.270491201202));
#2023=DIRECTION('',(1.,0.,0.));
#2024=DIRECTION('',(0.,0.,-1.));
#2025=AXIS2_PLACEMENT_3D('',#2022,#2023,#2024);
#2026=PLANE('',#2025);
#2027=ORIENTED_EDGE('',*,*,#423,.T.);
#2028=DIRECTION('',(0.,0.,-1.));
#2029=VECTOR('',#2028,1.);
#2030=CARTESIAN_POINT('',(-43.1299800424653,0.437184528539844,-67.270491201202));
#2031=LINE('',#2030,#2029);
#2032=CARTESIAN_POINT('',(-43.1299800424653,0.437184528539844,-67.270491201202));
#2033=VERTEX_POINT('',#2032);
#2034=EDGE_CURVE('E599',#2033,#414,#2031,.T.);
#2035=ORIENTED_EDGE('',*,*,#2034,.F.);
#2036=DIRECTION('',(0.,-1.,0.));
#2037=VECTOR('',#2036,1.);
#2038=CARTESIAN_POINT('',(-43.1299800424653,2.48718452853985,-67.270491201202));
#2039=LINE('',#2038,#2037);
#2040=CARTESIAN_POINT('',(-43.1299800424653,-3.96160565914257,-67.270491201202));
#2041=VERTEX_POINT('',#2040);
#2042=EDGE_CURVE('E574',#2033,#2041,#2039,.T.);
#2043=ORIENTED_EDGE('',*,*,#2042,.T.);
#2044=DIRECTION('',(0.,0.,-1.));
#2045=VECTOR('',#2044,1.);
#2046=CARTESIAN_POINT('',(-43.1299800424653,-3.96160565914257,-67.270491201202));
#2047=LINE('',#2046,#2045);
#2048=EDGE_CURVE('E597',#422,#2041,#2047,.F.);
#2049=ORIENTED_EDGE('',*,*,#2048,.F.);
#2050=EDGE_LOOP('',(#2027,#2035,#2043,#2049));
#2051=FACE_BOUND('',#2050,.T.);
#2052=ADVANCED_FACE('F1230',(#2051),#2026,.T.);
#2053=CARTESIAN_POINT('',(-49.2799800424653,-10.1116056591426,-67.270491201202));
#2054=DIRECTION('',(0.,0.,-1.));
#2055=DIRECTION('',(-1.,0.,0.));
#2056=AXIS2_PLACEMENT_3D('',#2053,#2054,#2055);
#2057=CYLINDRICAL_SURFACE('',#2056,8.2);
#2058=ORIENTED_EDGE('',*,*,#441,.T.);
#2059=DIRECTION('',(0.,0.,-1.));
#2060=VECTOR('',#2059,1.);
#2061=CARTESIAN_POINT('',(-42.7199800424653,-5.19160565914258,-67.270491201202));
#2062=LINE('',#2061,#2060);
#2063=CARTESIAN_POINT('',(-42.7199800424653,-5.19160565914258,-67.270491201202));
#2064=VERTEX_POINT('',#2063);
#2065=EDGE_CURVE('E622',#2064,#431,#2062,.T.);
#2066=ORIENTED_EDGE('',*,*,#2065,.F.);
#2067=CARTESIAN_POINT('',(-49.2799800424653,-10.1116056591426,-67.270491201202));
#2068=DIRECTION('',(0.,0.,-1.));
#2069=DIRECTION('',(-1.,0.,0.));
#2070=AXIS2_PLACEMENT_3D('',#2067,#2068,#2069);
#2071=CIRCLE('',#2070,8.2);
#2072=EDGE_CURVE('E587',#2064,#1793,#2071,.T.);
#2073=ORIENTED_EDGE('',*,*,#2072,.T.);
#2074=ORIENTED_EDGE('',*,*,#1794,.T.);
#2075=EDGE_LOOP('',(#2058,#2066,#2073,#2074));
#2076=FACE_BOUND('',#2075,.T.);
#2077=ADVANCED_FACE('F1241',(#2076),#2057,.T.);
#2078=CARTESIAN_POINT('',(-26.7299800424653,-10.1116056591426,-67.270491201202));
#2079=DIRECTION('',(0.,0.,1.));
#2080=DIRECTION('',(1.,0.,0.));
#2081=AXIS2_PLACEMENT_3D('',#2078,#2079,#2080);
#2082=CYLINDRICAL_SURFACE('',#2081,8.2);
#2083=ORIENTED_EDGE('',*,*,#372,.T.);
#2084=ORIENTED_EDGE('',*,*,#1955,.T.);
#2085=CARTESIAN_POINT('',(-26.7299800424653,-10.1116056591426,-67.270491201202));
#2086=DIRECTION('',(0.,0.,-1.));
#2087=DIRECTION('',(-1.,0.,0.));
#2088=AXIS2_PLACEMENT_3D('',#2085,#2086,#2087);
#2089=CIRCLE('',#2088,8.2);
#2090=CARTESIAN_POINT('',(-33.2899800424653,-5.19160565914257,-67.270491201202));
#2091=VERTEX_POINT('',#2090);
#2092=EDGE_CURVE('E589',#1948,#2091,#2089,.T.);
#2093=ORIENTED_EDGE('',*,*,#2092,.T.);
#2094=DIRECTION('',(0.,0.,1.));
#2095=VECTOR('',#2094,1.);
#2096=CARTESIAN_POINT('',(-33.2899800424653,-5.19160565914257,-67.270491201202));
#2097=LINE('',#2096,#2095);
#2098=EDGE_CURVE('E650',#371,#2091,#2097,.T.);
#2099=ORIENTED_EDGE('',*,*,#2098,.F.);
#2100=EDGE_LOOP('',(#2083,#2084,#2093,#2099));
#2101=FACE_BOUND('',#2100,.T.);
#2102=ADVANCED_FACE('F1204',(#2101),#2082,.T.);
#2103=CARTESIAN_POINT('',(-26.7299800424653,-27.9640252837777,-67.270491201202));
#2104=DIRECTION('',(0.,0.,-1.));
#2105=DIRECTION('',(-1.,0.,0.));
#2106=AXIS2_PLACEMENT_3D('',#2103,#2104,#2105);
#2107=CYLINDRICAL_SURFACE('',#2106,8.2);
#2108=ORIENTED_EDGE('',*,*,#355,.T.);
#2109=DIRECTION('',(0.,0.,-1.));
#2110=VECTOR('',#2109,1.);
#2111=CARTESIAN_POINT('',(-33.2899800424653,-32.8840252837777,-67.270491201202));
#2112=LINE('',#2111,#2110);
#2113=CARTESIAN_POINT('',(-33.2899800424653,-32.8840252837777,-67.270491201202));
#2114=VERTEX_POINT('',#2113);
#2115=EDGE_CURVE('E642',#2114,#345,#2112,.T.);
#2116=ORIENTED_EDGE('',*,*,#2115,.F.);
#2117=CARTESIAN_POINT('',(-26.7299800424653,-27.9640252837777,-67.270491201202));
#2118=DIRECTION('',(0.,0.,-1.));
#2119=DIRECTION('',(-1.,0.,0.));
#2120=AXIS2_PLACEMENT_3D('',#2117,#2118,#2119);
#2121=CIRCLE('',#2120,8.2);
#2122=EDGE_CURVE('E592',#2114,#1940,#2121,.T.);
#2123=ORIENTED_EDGE('',*,*,#2122,.T.);
#2124=ORIENTED_EDGE('',*,*,#1941,.T.);
#2125=EDGE_LOOP('',(#2108,#2116,#2123,#2124));
#2126=FACE_BOUND('',#2125,.T.);
#2127=ADVANCED_FACE('F1194',(#2126),#2107,.T.);
#2128=CARTESIAN_POINT('',(-49.2799800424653,-27.9640252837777,-67.270491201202));
#2129=DIRECTION('',(0.,0.,1.));
#2130=DIRECTION('',(1.,0.,0.));
#2131=AXIS2_PLACEMENT_3D('',#2128,#2129,#2130);
#2132=CYLINDRICAL_SURFACE('',#2131,8.2);
#2133=ORIENTED_EDGE('',*,*,#458,.T.);
#2134=ORIENTED_EDGE('',*,*,#1808,.T.);
#2135=CARTESIAN_POINT('',(-49.2799800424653,-27.9640252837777,-67.270491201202));
#2136=DIRECTION('',(0.,0.,-1.));
#2137=DIRECTION('',(-1.,0.,0.));
#2138=AXIS2_PLACEMENT_3D('',#2135,#2136,#2137);
#2139=CIRCLE('',#2138,8.2);
#2140=CARTESIAN_POINT('',(-42.7199800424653,-32.8840252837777,-67.270491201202));
#2141=VERTEX_POINT('',#2140);
#2142=EDGE_CURVE('E594',#1801,#2141,#2139,.T.);
#2143=ORIENTED_EDGE('',*,*,#2142,.T.);
#2144=DIRECTION('',(0.,0.,1.));
#2145=VECTOR('',#2144,1.);
#2146=CARTESIAN_POINT('',(-42.7199800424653,-32.8840252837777,-67.270491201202));
#2147=LINE('',#2146,#2145);
#2148=EDGE_CURVE('E630',#457,#2141,#2147,.T.);
#2149=ORIENTED_EDGE('',*,*,#2148,.F.);
#2150=EDGE_LOOP('',(#2133,#2134,#2143,#2149));
#2151=FACE_BOUND('',#2150,.T.);
#2152=ADVANCED_FACE('F1249',(#2151),#2132,.T.);
#2153=CARTESIAN_POINT('',(-41.0799800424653,0.437184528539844,-67.270491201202));
#2154=DIRECTION('',(0.,0.,-1.));
#2155=DIRECTION('',(-1.,0.,0.));
#2156=AXIS2_PLACEMENT_3D('',#2153,#2154,#2155);
#2157=CYLINDRICAL_SURFACE('',#2156,2.05);
#2158=ORIENTED_EDGE('',*,*,#2017,.T.);
#2159=CARTESIAN_POINT('',(-41.0799800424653,0.437184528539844,-67.270491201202));
#2160=DIRECTION('',(0.,0.,-1.));
#2161=DIRECTION('',(-1.,0.,0.));
#2162=AXIS2_PLACEMENT_3D('',#2159,#2160,#2161);
#2163=CIRCLE('',#2162,2.05);
#2164=EDGE_CURVE('E620',#2010,#2033,#2163,.F.);
#2165=ORIENTED_EDGE('',*,*,#2164,.T.);
#2166=ORIENTED_EDGE('',*,*,#2034,.T.);
#2167=ORIENTED_EDGE('',*,*,#415,.F.);
#2168=EDGE_LOOP('',(#2158,#2165,#2166,#2167));
#2169=FACE_BOUND('',#2168,.T.);
#2170=ADVANCED_FACE('F1225',(#2169),#2157,.F.);
#2171=CARTESIAN_POINT('',(-41.0799800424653,-3.96160565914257,-67.270491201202));
#2172=DIRECTION('',(0.,0.,-1.));
#2173=DIRECTION('',(-1.,0.,0.));
#2174=AXIS2_PLACEMENT_3D('',#2171,#2172,#2173);
#2175=CYLINDRICAL_SURFACE('',#2174,2.05);
#2176=ORIENTED_EDGE('',*,*,#2048,.T.);
#2177=CARTESIAN_POINT('',(-41.0799800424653,-3.96160565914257,-67.270491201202));
#2178=DIRECTION('',(0.,0.,-1.));
#2179=DIRECTION('',(-1.,0.,0.));
#2180=AXIS2_PLACEMENT_3D('',#2177,#2178,#2179);
#2181=CIRCLE('',#2180,2.05);
#2182=EDGE_CURVE('E618',#2041,#2064,#2181,.F.);
#2183=ORIENTED_EDGE('',*,*,#2182,.T.);
#2184=ORIENTED_EDGE('',*,*,#2065,.T.);
#2185=ORIENTED_EDGE('',*,*,#432,.F.);
#2186=EDGE_LOOP('',(#2176,#2183,#2184,#2185));
#2187=FACE_BOUND('',#2186,.T.);
#2188=ADVANCED_FACE('F1234',(#2187),#2175,.F.);
#2189=CARTESIAN_POINT('',(-41.0799800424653,-34.1140252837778,-67.270491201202));
#2190=DIRECTION('',(0.,0.,1.));
#2191=DIRECTION('',(1.,0.,0.));
#2192=AXIS2_PLACEMENT_3D('',#2189,#2190,#2191);
#2193=CYLINDRICAL_SURFACE('',#2192,2.05);
#2194=ORIENTED_EDGE('',*,*,#2148,.T.);
#2195=CARTESIAN_POINT('',(-41.0799800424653,-34.1140252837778,-67.270491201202));
#2196=DIRECTION('',(0.,0.,-1.));
#2197=DIRECTION('',(-1.,0.,0.));
#2198=AXIS2_PLACEMENT_3D('',#2195,#2196,#2197);
#2199=CIRCLE('',#2198,2.05);
#2200=EDGE_CURVE('E616',#2141,#1824,#2199,.F.);
#2201=ORIENTED_EDGE('',*,*,#2200,.T.);
#2202=ORIENTED_EDGE('',*,*,#1825,.T.);
#2203=ORIENTED_EDGE('',*,*,#467,.F.);
#2204=EDGE_LOOP('',(#2194,#2201,#2202,#2203));
#2205=FACE_BOUND('',#2204,.T.);
#2206=ADVANCED_FACE('F1253',(#2205),#2193,.F.);
#2207=CARTESIAN_POINT('',(-41.0799800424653,-38.5128154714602,-67.270491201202));
#2208=DIRECTION('',(0.,0.,-1.));
#2209=DIRECTION('',(-1.,0.,0.));
#2210=AXIS2_PLACEMENT_3D('',#2207,#2208,#2209);
#2211=CYLINDRICAL_SURFACE('',#2210,2.05);
#2212=ORIENTED_EDGE('',*,*,#1839,.T.);
#2213=CARTESIAN_POINT('',(-41.0799800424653,-38.5128154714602,-67.270491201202));
#2214=DIRECTION('',(0.,0.,-1.));
#2215=DIRECTION('',(-1.,0.,0.));
#2216=AXIS2_PLACEMENT_3D('',#2213,#2214,#2215);
#2217=CIRCLE('',#2216,2.05);
#2218=EDGE_CURVE('E614',#1832,#1877,#2217,.F.);
#2219=ORIENTED_EDGE('',*,*,#2218,.T.);
#2220=ORIENTED_EDGE('',*,*,#1878,.T.);
#2221=ORIENTED_EDGE('',*,*,#484,.F.);
#2222=EDGE_LOOP('',(#2212,#2219,#2220,#2221));
#2223=FACE_BOUND('',#2222,.T.);
#2224=ADVANCED_FACE('F1170',(#2223),#2211,.F.);
#2225=CARTESIAN_POINT('',(-34.9299800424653,-38.5128154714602,-67.270491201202));
#2226=DIRECTION('',(0.,0.,-1.));
#2227=DIRECTION('',(-1.,0.,0.));
#2228=AXIS2_PLACEMENT_3D('',#2225,#2226,#2227);
#2229=CYLINDRICAL_SURFACE('',#2228,2.05);
#2230=ORIENTED_EDGE('',*,*,#1892,.T.);
#2231=CARTESIAN_POINT('',(-34.9299800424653,-38.5128154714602,-67.270491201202));
#2232=DIRECTION('',(0.,0.,-1.));
#2233=DIRECTION('',(-1.,0.,0.));
#2234=AXIS2_PLACEMENT_3D('',#2231,#2232,#2233);
#2235=CIRCLE('',#2234,2.05);
#2236=EDGE_CURVE('E612',#1885,#1909,#2235,.F.);
#2237=ORIENTED_EDGE('',*,*,#2236,.T.);
#2238=ORIENTED_EDGE('',*,*,#1910,.T.);
#2239=ORIENTED_EDGE('',*,*,#329,.F.);
#2240=EDGE_LOOP('',(#2230,#2237,#2238,#2239));
#2241=FACE_BOUND('',#2240,.T.);
#2242=ADVANCED_FACE('F1181',(#2241),#2229,.F.);
#2243=CARTESIAN_POINT('',(-34.9299800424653,-34.1140252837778,-67.270491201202));
#2244=DIRECTION('',(0.,0.,-1.));
#2245=DIRECTION('',(-1.,0.,0.));
#2246=AXIS2_PLACEMENT_3D('',#2243,#2244,#2245);
#2247=CYLINDRICAL_SURFACE('',#2246,2.05);
#2248=ORIENTED_EDGE('',*,*,#1924,.T.);
#2249=CARTESIAN_POINT('',(-34.9299800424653,-34.1140252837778,-67.270491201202));
#2250=DIRECTION('',(0.,0.,-1.));
#2251=DIRECTION('',(-1.,0.,0.));
#2252=AXIS2_PLACEMENT_3D('',#2249,#2250,#2251);
#2253=CIRCLE('',#2252,2.05);
#2254=EDGE_CURVE('E610',#1917,#2114,#2253,.F.);
#2255=ORIENTED_EDGE('',*,*,#2254,.T.);
#2256=ORIENTED_EDGE('',*,*,#2115,.T.);
#2257=ORIENTED_EDGE('',*,*,#346,.F.);
#2258=EDGE_LOOP('',(#2248,#2255,#2256,#2257));
#2259=FACE_BOUND('',#2258,.T.);
#2260=ADVANCED_FACE('F1190',(#2259),#2247,.F.);
#2261=CARTESIAN_POINT('',(-34.9299800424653,-3.96160565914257,-67.270491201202));
#2262=DIRECTION('',(0.,0.,1.));
#2263=DIRECTION('',(1.,0.,0.));
#2264=AXIS2_PLACEMENT_3D('',#2261,#2262,#2263);
#2265=CYLINDRICAL_SURFACE('',#2264,2.05);
#2266=ORIENTED_EDGE('',*,*,#2098,.T.);
#2267=CARTESIAN_POINT('',(-34.9299800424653,-3.96160565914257,-67.270491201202));
#2268=DIRECTION('',(0.,0.,-1.));
#2269=DIRECTION('',(-1.,0.,0.));
#2270=AXIS2_PLACEMENT_3D('',#2267,#2268,#2269);
#2271=CIRCLE('',#2270,2.05);
#2272=EDGE_CURVE('E608',#2091,#1971,#2271,.F.);
#2273=ORIENTED_EDGE('',*,*,#2272,.T.);
#2274=ORIENTED_EDGE('',*,*,#1972,.T.);
#2275=ORIENTED_EDGE('',*,*,#381,.F.);
#2276=EDGE_LOOP('',(#2266,#2273,#2274,#2275));
#2277=FACE_BOUND('',#2276,.T.);
#2278=ADVANCED_FACE('F1208',(#2277),#2265,.F.);
#2279=CARTESIAN_POINT('',(-34.9299800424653,0.437184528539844,-67.270491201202));
#2280=DIRECTION('',(0.,0.,-1.));
#2281=DIRECTION('',(-1.,0.,0.));
#2282=AXIS2_PLACEMENT_3D('',#2279,#2280,#2281);
#2283=CYLINDRICAL_SURFACE('',#2282,2.05);
#2284=ORIENTED_EDGE('',*,*,#1986,.T.);
#2285=CARTESIAN_POINT('',(-34.9299800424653,0.437184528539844,-67.270491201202));
#2286=DIRECTION('',(0.,0.,-1.));
#2287=DIRECTION('',(-1.,0.,0.));
#2288=AXIS2_PLACEMENT_3D('',#2285,#2286,#2287);
#2289=CIRCLE('',#2288,2.05);
#2290=EDGE_CURVE('E606',#1979,#2002,#2289,.F.);
#2291=ORIENTED_EDGE('',*,*,#2290,.T.);
#2292=ORIENTED_EDGE('',*,*,#2003,.T.);
#2293=ORIENTED_EDGE('',*,*,#398,.F.);
#2294=EDGE_LOOP('',(#2284,#2291,#2292,#2293));
#2295=FACE_BOUND('',#2294,.T.);
#2296=ADVANCED_FACE('F1218',(#2295),#2283,.F.);
#2297=CARTESIAN_POINT('',(-38.0049800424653,-13.9128154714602,-67.270491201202));
#2298=DIRECTION('',(0.,0.,-1.));
#2299=DIRECTION('',(-1.,0.,0.));
#2300=AXIS2_PLACEMENT_3D('',#2297,#2298,#2299);
#2301=PLANE('',#2300);
#2302=ORIENTED_EDGE('',*,*,#2011,.F.);
#2303=ORIENTED_EDGE('',*,*,#2290,.F.);
#2304=ORIENTED_EDGE('',*,*,#1980,.F.);
#2305=ORIENTED_EDGE('',*,*,#2272,.F.);
#2306=ORIENTED_EDGE('',*,*,#2092,.F.);
#2307=ORIENTED_EDGE('',*,*,#1949,.F.);
#2308=ORIENTED_EDGE('',*,*,#2122,.F.);
#2309=ORIENTED_EDGE('',*,*,#2254,.F.);
#2310=ORIENTED_EDGE('',*,*,#1918,.F.);
#2311=ORIENTED_EDGE('',*,*,#2236,.F.);
#2312=ORIENTED_EDGE('',*,*,#1886,.F.);
#2313=ORIENTED_EDGE('',*,*,#2218,.F.);
#2314=ORIENTED_EDGE('',*,*,#1833,.F.);
#2315=ORIENTED_EDGE('',*,*,#2200,.F.);
#2316=ORIENTED_EDGE('',*,*,#2142,.F.);
#2317=ORIENTED_EDGE('',*,*,#1802,.F.);
#2318=ORIENTED_EDGE('',*,*,#2072,.F.);
#2319=ORIENTED_EDGE('',*,*,#2182,.F.);
#2320=ORIENTED_EDGE('',*,*,#2042,.F.);
#2321=ORIENTED_EDGE('',*,*,#2164,.F.);
#2322=EDGE_LOOP('',(#2302,#2303,#2304,#2305,#2306,#2307,#2308,#2309,#2310,#2311,#2312,#2313,
#2314,#2315,#2316,#2317,#2318,#2319,#2320,#2321));
#2323=FACE_BOUND('',#2322,.T.);
#2324=ADVANCED_FACE('F1178',(#2323),#2301,.T.);
#2325=CARTESIAN_POINT('',(-27.0049800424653,-38.404034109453,-66.789241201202));
#2326=DIRECTION('',(0.,0.,-1.));
#2327=DIRECTION('',(-1.,0.,0.));
#2328=AXIS2_PLACEMENT_3D('',#2325,#2326,#2327);
#2329=CYLINDRICAL_SURFACE('',#2328,10.6337813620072);
#2330=DIRECTION('',(0.,0.,-1.));
#2331=VECTOR('',#2330,1.);
#2332=CARTESIAN_POINT('',(-36.2645132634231,-43.6326429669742,-66.789241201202));
#2333=LINE('',#2332,#2331);
#2334=CARTESIAN_POINT('',(-36.2645132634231,-43.6326429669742,-68.289241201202));
#2335=VERTEX_POINT('',#2334);
#2336=EDGE_CURVE('E992',#504,#2335,#2333,.F.);
#2337=ORIENTED_EDGE('',*,*,#2336,.T.);
#2338=CARTESIAN_POINT('',(-27.0049800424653,-38.404034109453,-68.289241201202));
#2339=DIRECTION('',(0.,0.,-1.));
#2340=DIRECTION('',(-1.,0.,0.));
#2341=AXIS2_PLACEMENT_3D('',#2338,#2339,#2340);
#2342=CIRCLE('',#2341,10.6337813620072);
#2343=EDGE_CURVE('E1018',#2335,#122,#2342,.F.);
#2344=ORIENTED_EDGE('',*,*,#2343,.T.);
#2345=CARTESIAN_POINT('',(-27.0049800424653,-38.404034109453,-68.289241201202));
#2346=DIRECTION('',(0.,0.,-1.));
#2347=DIRECTION('',(-1.,0.,0.));
#2348=AXIS2_PLACEMENT_3D('',#2345,#2346,#2347);
#2349=CIRCLE('',#2348,10.6337813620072);
#2350=CARTESIAN_POINT('',(-17.7454468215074,-43.6326429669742,-68.289241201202));
#2351=VERTEX_POINT('',#2350);
#2352=EDGE_CURVE('E1016',#122,#2351,#2349,.F.);
#2353=ORIENTED_EDGE('',*,*,#2352,.T.);
#2354=DIRECTION('',(0.,0.,-1.));
#2355=VECTOR('',#2354,1.);
#2356=CARTESIAN_POINT('',(-17.7454468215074,-43.6326429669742,-66.789241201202));
#2357=LINE('',#2356,#2355);
#2358=EDGE_CURVE('E990',#2351,#513,#2357,.T.);
#2359=ORIENTED_EDGE('',*,*,#2358,.T.);
#2360=ORIENTED_EDGE('',*,*,#514,.F.);
#2361=EDGE_LOOP('',(#2337,#2344,#2353,#2359,#2360));
#2362=FACE_BOUND('',#2361,.T.);
#2363=ADVANCED_FACE('F1158',(#2362),#2329,.F.);
#2364=CARTESIAN_POINT('',(-27.0049800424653,-38.404034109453,-66.789241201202));
#2365=DIRECTION('',(0.,0.,-1.));
#2366=DIRECTION('',(-1.,0.,0.));
#2367=AXIS2_PLACEMENT_3D('',#2364,#2365,#2366);
#2368=CYLINDRICAL_SURFACE('',#2367,7.63378136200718);
#2369=CARTESIAN_POINT('',(-27.0049800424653,-38.404034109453,-68.289241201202));
#2370=DIRECTION('',(0.,0.,-1.));
#2371=DIRECTION('',(-1.,0.,0.));
#2372=AXIS2_PLACEMENT_3D('',#2369,#2370,#2371);
#2373=CIRCLE('',#2372,7.63378136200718);
#2374=CARTESIAN_POINT('',(-20.3577442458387,-42.1575490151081,-68.289241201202));
#2375=VERTEX_POINT('',#2374);
#2376=EDGE_CURVE('E1005',#2375,#56,#2373,.T.);
#2377=ORIENTED_EDGE('',*,*,#2376,.T.);
#2378=CARTESIAN_POINT('',(-27.0049800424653,-38.404034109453,-68.289241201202));
#2379=DIRECTION('',(0.,0.,-1.));
#2380=DIRECTION('',(-1.,0.,0.));
#2381=AXIS2_PLACEMENT_3D('',#2378,#2379,#2380);
#2382=CIRCLE('',#2381,7.63378136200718);
#2383=CARTESIAN_POINT('',(-33.6522158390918,-42.1575490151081,-68.289241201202));
#2384=VERTEX_POINT('',#2383);
#2385=EDGE_CURVE('E1008',#56,#2384,#2382,.T.);
#2386=ORIENTED_EDGE('',*,*,#2385,.T.);
#2387=DIRECTION('',(0.,0.,-1.));
#2388=VECTOR('',#2387,1.);
#2389=CARTESIAN_POINT('',(-33.6522158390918,-42.1575490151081,-66.789241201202));
#2390=LINE('',#2389,#2388);
#2391=EDGE_CURVE('E988',#2384,#301,#2390,.T.);
#2392=ORIENTED_EDGE('',*,*,#2391,.T.);
#2393=ORIENTED_EDGE('',*,*,#731,.F.);
#2394=DIRECTION('',(0.,0.,-1.));
#2395=VECTOR('',#2394,1.);
#2396=CARTESIAN_POINT('',(-20.3577442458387,-42.1575490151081,-66.789241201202));
#2397=LINE('',#2396,#2395);
#2398=EDGE_CURVE('E985',#723,#2375,#2397,.F.);
#2399=ORIENTED_EDGE('',*,*,#2398,.T.);
#2400=EDGE_LOOP('',(#2377,#2386,#2392,#2393,#2399));
#2401=FACE_BOUND('',#2400,.T.);
#2402=ADVANCED_FACE('F1111',(#2401),#2368,.T.);
#2403=CARTESIAN_POINT('',(-34.9583645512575,-42.8950959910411,-66.789241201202));
#2404=DIRECTION('',(0.,0.,-1.));
#2405=DIRECTION('',(-1.,0.,0.));
#2406=AXIS2_PLACEMENT_3D('',#2403,#2404,#2405);
#2407=CYLINDRICAL_SURFACE('',#2406,1.5);
#2408=ORIENTED_EDGE('',*,*,#505,.F.);
#2409=CARTESIAN_POINT('',(-34.9583645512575,-42.8950959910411,-63.690954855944));
#2410=DIRECTION('',(-0.984807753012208,0.,0.173648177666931));
#2411=DIRECTION('',(-0.173648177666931,0.,-0.984807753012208));
#2412=AXIS2_PLACEMENT_3D('',#2409,#2410,#2411);
#2413=ELLIPSE('',#2412,8.63815572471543,1.5);
#2414=CARTESIAN_POINT('',(-35.7691664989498,-41.6331133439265,-68.289241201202));
#2415=VERTEX_POINT('',#2414);
#2416=EDGE_CURVE('E514',#495,#2415,#2413,.F.);
#2417=ORIENTED_EDGE('',*,*,#2416,.T.);
#2418=CARTESIAN_POINT('',(-34.9583645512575,-42.8950959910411,-68.289241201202));
#2419=DIRECTION('',(0.,0.,-1.));
#2420=DIRECTION('',(-1.,0.,0.));
#2421=AXIS2_PLACEMENT_3D('',#2418,#2419,#2420);
#2422=CIRCLE('',#2421,1.5);
#2423=EDGE_CURVE('E1014',#2415,#2335,#2422,.F.);
#2424=ORIENTED_EDGE('',*,*,#2423,.T.);
#2425=ORIENTED_EDGE('',*,*,#2336,.F.);
#2426=EDGE_LOOP('',(#2408,#2417,#2424,#2425));
#2427=FACE_BOUND('',#2426,.T.);
#2428=ADVANCED_FACE('F1162',(#2427),#2407,.F.);
#2429=CARTESIAN_POINT('',(-34.9583645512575,-42.8950959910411,-66.789241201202));
#2430=DIRECTION('',(0.,0.,-1.));
#2431=DIRECTION('',(-1.,0.,0.));
#2432=AXIS2_PLACEMENT_3D('',#2429,#2430,#2431);
#2433=CYLINDRICAL_SURFACE('',#2432,1.5);
#2434=CARTESIAN_POINT('',(-34.9583645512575,-42.8950959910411,-68.289241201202));
#2435=DIRECTION('',(0.,0.,-1.));
#2436=DIRECTION('',(-1.,0.,0.));
#2437=AXIS2_PLACEMENT_3D('',#2434,#2435,#2436);
#2438=CIRCLE('',#2437,1.5);
#2439=CARTESIAN_POINT('',(-35.1983643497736,-41.4144204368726,-68.289241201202));
#2440=VERTEX_POINT('',#2439);
#2441=EDGE_CURVE('E1011',#2384,#2440,#2438,.F.);
#2442=ORIENTED_EDGE('',*,*,#2441,.T.);
#2443=CARTESIAN_POINT('',(-34.9583645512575,-42.8950959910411,-69.6503476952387));
#2444=DIRECTION('',(0.984807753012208,0.,0.173648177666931));
#2445=DIRECTION('',(0.173648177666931,0.,-0.984807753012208));
#2446=AXIS2_PLACEMENT_3D('',#2443,#2444,#2445);
#2447=ELLIPSE('',#2446,8.63815572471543,1.5);
#2448=EDGE_CURVE('E498',#2440,#303,#2447,.F.);
#2449=ORIENTED_EDGE('',*,*,#2448,.T.);
#2450=ORIENTED_EDGE('',*,*,#304,.F.);
#2451=ORIENTED_EDGE('',*,*,#2391,.F.);
#2452=EDGE_LOOP('',(#2442,#2449,#2450,#2451));
#2453=FACE_BOUND('',#2452,.T.);
#2454=ADVANCED_FACE('F1107',(#2453),#2433,.F.);
#2455=CARTESIAN_POINT('',(-19.0515955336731,-42.8950959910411,-66.789241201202));
#2456=DIRECTION('',(0.,0.,-1.));
#2457=DIRECTION('',(-1.,0.,0.));
#2458=AXIS2_PLACEMENT_3D('',#2455,#2456,#2457);
#2459=CYLINDRICAL_SURFACE('',#2458,1.5);
#2460=ORIENTED_EDGE('',*,*,#724,.F.);
#2461=CARTESIAN_POINT('',(-19.0515955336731,-42.8950959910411,-66.0141223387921));
#2462=DIRECTION('',(-0.897052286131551,0.406378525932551,0.173648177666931));
#2463=DIRECTION('',(-0.158174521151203,0.0716554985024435,-0.984807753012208));
#2464=AXIS2_PLACEMENT_3D('',#2461,#2462,#2463);
#2465=ELLIPSE('',#2464,8.63815572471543,1.5);
#2466=CARTESIAN_POINT('',(-18.8205884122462,-41.4129908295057,-68.289241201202));
#2467=VERTEX_POINT('',#2466);
#2468=EDGE_CURVE('E541',#714,#2467,#2465,.F.);
#2469=ORIENTED_EDGE('',*,*,#2468,.T.);
#2470=CARTESIAN_POINT('',(-19.0515955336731,-42.8950959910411,-68.289241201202));
#2471=DIRECTION('',(0.,0.,-1.));
#2472=DIRECTION('',(-1.,0.,0.));
#2473=AXIS2_PLACEMENT_3D('',#2470,#2471,#2472);
#2474=CIRCLE('',#2473,1.5);
#2475=EDGE_CURVE('E1024',#2467,#2375,#2474,.F.);
#2476=ORIENTED_EDGE('',*,*,#2475,.T.);
#2477=ORIENTED_EDGE('',*,*,#2398,.F.);
#2478=EDGE_LOOP('',(#2460,#2469,#2476,#2477));
#2479=FACE_BOUND('',#2478,.T.);
#2480=ADVANCED_FACE('F1051',(#2479),#2459,.F.);
#2481=CARTESIAN_POINT('',(-19.0515955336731,-42.8950959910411,-66.789241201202));
#2482=DIRECTION('',(0.,0.,-1.));
#2483=DIRECTION('',(-1.,0.,0.));
#2484=AXIS2_PLACEMENT_3D('',#2481,#2482,#2483);
#2485=CYLINDRICAL_SURFACE('',#2484,1.5);
#2486=CARTESIAN_POINT('',(-19.0515955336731,-42.8950959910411,-68.289241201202));
#2487=DIRECTION('',(0.,0.,-1.));
#2488=DIRECTION('',(-1.,0.,0.));
#2489=AXIS2_PLACEMENT_3D('',#2486,#2487,#2488);
#2490=CIRCLE('',#2489,1.5);
#2491=CARTESIAN_POINT('',(-18.279595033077,-41.6090107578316,-68.289241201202));
#2492=VERTEX_POINT('',#2491);
#2493=EDGE_CURVE('E1021',#2351,#2492,#2490,.F.);
#2494=ORIENTED_EDGE('',*,*,#2493,.T.);
#2495=CARTESIAN_POINT('',(-19.0515955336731,-42.8950959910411,-67.3108986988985));
#2496=DIRECTION('',(0.89705228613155,-0.406378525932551,0.173648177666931));
#2497=DIRECTION('',(0.158174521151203,-0.0716554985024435,-0.984807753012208));
#2498=AXIS2_PLACEMENT_3D('',#2495,#2496,#2497);
#2499=ELLIPSE('',#2498,8.63815572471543,1.5);
#2500=EDGE_CURVE('E546',#2492,#522,#2499,.F.);
#2501=ORIENTED_EDGE('',*,*,#2500,.T.);
#2502=ORIENTED_EDGE('',*,*,#523,.F.);
#2503=ORIENTED_EDGE('',*,*,#2358,.F.);
#2504=EDGE_LOOP('',(#2494,#2501,#2502,#2503));
#2505=FACE_BOUND('',#2504,.T.);
#2506=ADVANCED_FACE('F1154',(#2505),#2485,.F.);
#2507=CARTESIAN_POINT('',(-19.0515955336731,-42.8950959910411,-68.289241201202));
#2508=DIRECTION('',(0.,0.,1.));
#2509=DIRECTION('',(1.,0.,0.));
#2510=AXIS2_PLACEMENT_3D('',#2507,#2508,#2509);
#2511=SPHERICAL_SURFACE('',#2510,1.5);
#2512=CARTESIAN_POINT('',(-19.0515955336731,-42.8950959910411,-68.0392412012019));
#2513=DIRECTION('',(0.,0.,-1.));
#2514=DIRECTION('',(-1.,0.,0.));
#2515=AXIS2_PLACEMENT_3D('',#2512,#2513,#2514);
#2516=CIRCLE('',#2515,1.4790199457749);
#2517=CARTESIAN_POINT('',(-18.3266042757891,-41.6059537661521,-68.0392412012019));
#2518=VERTEX_POINT('',#2517);
#2519=CARTESIAN_POINT('',(-18.5457409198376,-41.5052718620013,-68.0392412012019));
#2520=VERTEX_POINT('',#2519);
#2521=EDGE_CURVE('E59',#2518,#2520,#2516,.F.);
#2522=ORIENTED_EDGE('',*,*,#2521,.F.);
#2523=CARTESIAN_POINT('',(-18.8991976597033,-42.9641345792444,-68.2597405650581));
#2524=DIRECTION('',(0.89705228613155,-0.406378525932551,0.173648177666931));
#2525=DIRECTION('',(0.412647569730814,0.910890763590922,0.));
#2526=AXIS2_PLACEMENT_3D('',#2523,#2524,#2525);
#2527=CIRCLE('',#2526,1.49034837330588);
#2528=EDGE_CURVE('E1095',#2518,#2492,#2527,.F.);
#2529=ORIENTED_EDGE('',*,*,#2528,.T.);
#2530=ORIENTED_EDGE('',*,*,#2493,.F.);
#2531=CARTESIAN_POINT('',(-19.0515955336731,-42.8950959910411,-68.289241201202));
#2532=DIRECTION('',(0.491697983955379,0.870765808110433,0.));
#2533=DIRECTION('',(-0.870765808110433,0.491697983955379,0.));
#2534=AXIS2_PLACEMENT_3D('',#2531,#2532,#2533);
#2535=CIRCLE('',#2534,1.5);
#2536=CARTESIAN_POINT('',(-19.0515955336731,-42.8950959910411,-66.789241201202));
#2537=VERTEX_POINT('',#2536);
#2538=EDGE_CURVE('E556',#2537,#2351,#2535,.T.);
#2539=ORIENTED_EDGE('',*,*,#2538,.F.);
#2540=CARTESIAN_POINT('',(-19.0515955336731,-42.8950959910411,-68.289241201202));
#2541=DIRECTION('',(0.939692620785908,-0.342020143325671,0.));
#2542=DIRECTION('',(0.342020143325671,0.939692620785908,0.));
#2543=AXIS2_PLACEMENT_3D('',#2540,#2541,#2542);
#2544=CIRCLE('',#2543,1.5);
#2545=EDGE_CURVE('E1087',#2520,#2537,#2544,.T.);
#2546=ORIENTED_EDGE('',*,*,#2545,.F.);
#2547=EDGE_LOOP('',(#2522,#2529,#2530,#2539,#2546));
#2548=FACE_BOUND('',#2547,.T.);
#2549=ADVANCED_FACE('F38',(#2548),#2511,.F.);
#2550=CARTESIAN_POINT('',(-34.9583645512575,-42.8950959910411,-68.289241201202));
#2551=DIRECTION('',(0.,0.,1.));
#2552=DIRECTION('',(1.,0.,0.));
#2553=AXIS2_PLACEMENT_3D('',#2550,#2551,#2552);
#2554=SPHERICAL_SURFACE('',#2553,1.5);
#2555=ORIENTED_EDGE('',*,*,#2423,.F.);
#2556=CARTESIAN_POINT('',(-35.7447178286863,-42.8950959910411,-68.1505859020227));
#2557=DIRECTION('',(-0.984807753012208,0.,0.173648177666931));
#2558=DIRECTION('',(0.173648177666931,0.,0.984807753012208));
#2559=AXIS2_PLACEMENT_3D('',#2556,#2557,#2558);
#2560=CIRCLE('',#2559,1.26981228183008);
#2561=CARTESIAN_POINT('',(-35.7250847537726,-41.630327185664,-68.039241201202));
#2562=VERTEX_POINT('',#2561);
#2563=EDGE_CURVE('E11',#2415,#2562,#2560,.F.);
#2564=ORIENTED_EDGE('',*,*,#2563,.T.);
#2565=CARTESIAN_POINT('',(-34.9583645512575,-42.8950959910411,-68.039241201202));
#2566=DIRECTION('',(0.,0.,-1.));
#2567=DIRECTION('',(-1.,0.,0.));
#2568=AXIS2_PLACEMENT_3D('',#2565,#2566,#2567);
#2569=CIRCLE('',#2568,1.4790199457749);
#2570=CARTESIAN_POINT('',(-35.4642191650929,-41.5052718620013,-68.039241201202));
#2571=VERTEX_POINT('',#2570);
#2572=EDGE_CURVE('E499',#2571,#2562,#2569,.F.);
#2573=ORIENTED_EDGE('',*,*,#2572,.F.);
#2574=CARTESIAN_POINT('',(-34.9583645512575,-42.8950959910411,-68.289241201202));
#2575=DIRECTION('',(-0.93969262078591,-0.342020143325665,0.));
#2576=DIRECTION('',(0.342020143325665,-0.93969262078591,0.));
#2577=AXIS2_PLACEMENT_3D('',#2574,#2575,#2576);
#2578=CIRCLE('',#2577,1.5);
#2579=CARTESIAN_POINT('',(-34.9583645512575,-42.8950959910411,-66.789241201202));
#2580=VERTEX_POINT('',#2579);
#2581=EDGE_CURVE('E1084',#2580,#2571,#2578,.T.);
#2582=ORIENTED_EDGE('',*,*,#2581,.F.);
#2583=CARTESIAN_POINT('',(-34.9583645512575,-42.8950959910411,-68.289241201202));
#2584=DIRECTION('',(-0.491697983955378,0.870765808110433,0.));
#2585=DIRECTION('',(-0.870765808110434,-0.491697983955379,0.));
#2586=AXIS2_PLACEMENT_3D('',#2583,#2584,#2585);
#2587=CIRCLE('',#2586,1.5);
#2588=EDGE_CURVE('E1081',#2335,#2580,#2587,.T.);
#2589=ORIENTED_EDGE('',*,*,#2588,.F.);
#2590=EDGE_LOOP('',(#2555,#2564,#2573,#2582,#2589));
#2591=FACE_BOUND('',#2590,.T.);
#2592=ADVANCED_FACE('F1131',(#2591),#2554,.F.);
#2593=CARTESIAN_POINT('',(-27.0049800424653,-38.404034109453,-68.289241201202));
#2594=DIRECTION('',(0.,0.,-1.));
#2595=DIRECTION('',(-1.,0.,0.));
#2596=AXIS2_PLACEMENT_3D('',#2593,#2594,#2595);
#2597=TOROIDAL_SURFACE('',#2596,9.13378136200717,1.5);
#2598=ORIENTED_EDGE('',*,*,#2538,.T.);
#2599=ORIENTED_EDGE('',*,*,#2352,.F.);
#2600=ORIENTED_EDGE('',*,*,#123,.F.);
#2601=CARTESIAN_POINT('',(-27.0049800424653,-38.404034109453,-66.789241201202));
#2602=DIRECTION('',(0.,0.,-1.));
#2603=DIRECTION('',(-1.,0.,0.));
#2604=AXIS2_PLACEMENT_3D('',#2601,#2602,#2603);
#2605=CIRCLE('',#2604,9.13378136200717);
#2606=EDGE_CURVE('E1078',#2537,#89,#2605,.T.);
#2607=ORIENTED_EDGE('',*,*,#2606,.F.);
#2608=EDGE_LOOP('',(#2598,#2599,#2600,#2607));
#2609=FACE_BOUND('',#2608,.T.);
#2610=ADVANCED_FACE('F1122',(#2609),#2597,.F.);
#2611=CARTESIAN_POINT('',(-19.0515955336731,-42.8950959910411,-68.289241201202));
#2612=DIRECTION('',(0.,0.,1.));
#2613=DIRECTION('',(1.,0.,0.));
#2614=AXIS2_PLACEMENT_3D('',#2611,#2612,#2613);
#2615=SPHERICAL_SURFACE('',#2614,1.5);
#2616=ORIENTED_EDGE('',*,*,#2475,.F.);
#2617=CARTESIAN_POINT('',(-19.4059941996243,-42.7345479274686,-68.2206379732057));
#2618=DIRECTION('',(-0.897052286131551,0.406378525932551,0.173648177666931));
#2619=DIRECTION('',(-0.412647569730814,-0.910890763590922,0.));
#2620=AXIS2_PLACEMENT_3D('',#2617,#2618,#2619);
#2621=CIRCLE('',#2620,1.44703818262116);
#2622=CARTESIAN_POINT('',(-18.7845997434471,-41.4403749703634,-68.0392412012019));
#2623=VERTEX_POINT('',#2622);
#2624=EDGE_CURVE('E1092',#2467,#2623,#2621,.F.);
#2625=ORIENTED_EDGE('',*,*,#2624,.T.);
#2626=CARTESIAN_POINT('',(-19.0515955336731,-42.8950959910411,-68.0392412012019));
#2627=DIRECTION('',(0.,0.,-1.));
#2628=DIRECTION('',(-1.,0.,0.));
#2629=AXIS2_PLACEMENT_3D('',#2626,#2627,#2628);
#2630=CIRCLE('',#2629,1.4790199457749);
#2631=EDGE_CURVE('E1065',#2520,#2623,#2630,.F.);
#2632=ORIENTED_EDGE('',*,*,#2631,.F.);
#2633=ORIENTED_EDGE('',*,*,#2545,.T.);
#2634=CARTESIAN_POINT('',(-19.0515955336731,-42.8950959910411,-68.289241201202));
#2635=DIRECTION('',(0.491697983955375,0.870765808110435,0.));
#2636=DIRECTION('',(-0.870765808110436,0.491697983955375,0.));
#2637=AXIS2_PLACEMENT_3D('',#2634,#2635,#2636);
#2638=CIRCLE('',#2637,1.5);
#2639=EDGE_CURVE('E1075',#2375,#2537,#2638,.T.);
#2640=ORIENTED_EDGE('',*,*,#2639,.F.);
#2641=EDGE_LOOP('',(#2616,#2625,#2632,#2633,#2640));
#2642=FACE_BOUND('',#2641,.T.);
#2643=ADVANCED_FACE('F1147',(#2642),#2615,.F.);
#2644=CARTESIAN_POINT('',(-34.9583645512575,-42.8950959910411,-68.289241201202));
#2645=DIRECTION('',(0.,0.,1.));
#2646=DIRECTION('',(1.,0.,0.));
#2647=AXIS2_PLACEMENT_3D('',#2644,#2645,#2646);
#2648=SPHERICAL_SURFACE('',#2647,1.5);
#2649=CARTESIAN_POINT('',(-34.9583645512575,-42.8950959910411,-68.039241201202));
#2650=DIRECTION('',(0.,0.,-1.));
#2651=DIRECTION('',(-1.,0.,0.));
#2652=AXIS2_PLACEMENT_3D('',#2649,#2650,#2651);
#2653=CIRCLE('',#2652,1.4790199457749);
#2654=CARTESIAN_POINT('',(-35.2424460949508,-41.4436147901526,-68.039241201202));
#2655=VERTEX_POINT('',#2654);
#2656=EDGE_CURVE('E1100',#2655,#2571,#2653,.F.);
#2657=ORIENTED_EDGE('',*,*,#2656,.F.);
#2658=CARTESIAN_POINT('',(-35.1911274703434,-42.8950959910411,-68.3302835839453));
#2659=DIRECTION('',(0.984807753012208,0.,0.173648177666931));
#2660=DIRECTION('',(0.173648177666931,0.,-0.984807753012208));
#2661=AXIS2_PLACEMENT_3D('',#2658,#2659,#2660);
#2662=CIRCLE('',#2661,1.48126194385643);
#2663=EDGE_CURVE('E44',#2655,#2440,#2662,.F.);
#2664=ORIENTED_EDGE('',*,*,#2663,.T.);
#2665=ORIENTED_EDGE('',*,*,#2441,.F.);
#2666=CARTESIAN_POINT('',(-34.9583645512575,-42.8950959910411,-68.289241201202));
#2667=DIRECTION('',(-0.49169798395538,0.870765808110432,0.));
#2668=DIRECTION('',(-0.870765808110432,-0.49169798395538,0.));
#2669=AXIS2_PLACEMENT_3D('',#2666,#2667,#2668);
#2670=CIRCLE('',#2669,1.5);
#2671=EDGE_CURVE('E1073',#2580,#2384,#2670,.T.);
#2672=ORIENTED_EDGE('',*,*,#2671,.F.);
#2673=ORIENTED_EDGE('',*,*,#2581,.T.);
#2674=EDGE_LOOP('',(#2657,#2664,#2665,#2672,#2673));
#2675=FACE_BOUND('',#2674,.T.);
#2676=ADVANCED_FACE('F1103',(#2675),#2648,.F.);
#2677=CARTESIAN_POINT('',(-27.0049800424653,-38.404034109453,-68.289241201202));
#2678=DIRECTION('',(0.,0.,-1.));
#2679=DIRECTION('',(-1.,0.,0.));
#2680=AXIS2_PLACEMENT_3D('',#2677,#2678,#2679);
#2681=TOROIDAL_SURFACE('',#2680,9.13378136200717,1.5);
#2682=ORIENTED_EDGE('',*,*,#2343,.F.);
#2683=ORIENTED_EDGE('',*,*,#2588,.T.);
#2684=CARTESIAN_POINT('',(-27.0049800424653,-38.404034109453,-66.789241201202));
#2685=DIRECTION('',(0.,0.,-1.));
#2686=DIRECTION('',(-1.,0.,0.));
#2687=AXIS2_PLACEMENT_3D('',#2684,#2685,#2686);
#2688=CIRCLE('',#2687,9.13378136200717);
#2689=EDGE_CURVE('E551',#54,#2580,#2688,.T.);
#2690=ORIENTED_EDGE('',*,*,#2689,.F.);
#2691=ORIENTED_EDGE('',*,*,#154,.F.);
#2692=EDGE_LOOP('',(#2682,#2683,#2690,#2691));
#2693=FACE_BOUND('',#2692,.T.);
#2694=ADVANCED_FACE('F1055',(#2693),#2681,.F.);
#2695=CARTESIAN_POINT('',(-27.0049800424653,-38.404034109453,-68.289241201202));
#2696=DIRECTION('',(0.,0.,-1.));
#2697=DIRECTION('',(-1.,0.,0.));
#2698=AXIS2_PLACEMENT_3D('',#2695,#2696,#2697);
#2699=TOROIDAL_SURFACE('',#2698,9.13378136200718,1.5);
#2700=ORIENTED_EDGE('',*,*,#2606,.T.);
#2701=ORIENTED_EDGE('',*,*,#90,.F.);
#2702=ORIENTED_EDGE('',*,*,#2376,.F.);
#2703=ORIENTED_EDGE('',*,*,#2639,.T.);
#2704=EDGE_LOOP('',(#2700,#2701,#2702,#2703));
#2705=FACE_BOUND('',#2704,.T.);
#2706=ADVANCED_FACE('F1049',(#2705),#2699,.F.);
#2707=CARTESIAN_POINT('',(-27.0049800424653,-38.404034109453,-68.289241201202));
#2708=DIRECTION('',(0.,0.,-1.));
#2709=DIRECTION('',(-1.,0.,0.));
#2710=AXIS2_PLACEMENT_3D('',#2707,#2708,#2709);
#2711=TOROIDAL_SURFACE('',#2710,9.13378136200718,1.5);
#2712=ORIENTED_EDGE('',*,*,#2671,.T.);
#2713=ORIENTED_EDGE('',*,*,#2385,.F.);
#2714=ORIENTED_EDGE('',*,*,#57,.F.);
#2715=ORIENTED_EDGE('',*,*,#2689,.T.);
#2716=EDGE_LOOP('',(#2712,#2713,#2714,#2715));
#2717=FACE_BOUND('',#2716,.T.);
#2718=ADVANCED_FACE('F1043',(#2717),#2711,.F.);
#2719=CARTESIAN_POINT('',(-18.2617564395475,-41.7832865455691,-68.789241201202));
#2720=DIRECTION('',(0.89705228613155,-0.406378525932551,0.173648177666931));
#2721=DIRECTION('',(0.412647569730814,0.910890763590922,0.));
#2722=AXIS2_PLACEMENT_3D('',#2719,#2720,#2721);
#2723=PLANE('',#2722);
#2724=ORIENTED_EDGE('',*,*,#1304,.T.);
#2725=ORIENTED_EDGE('',*,*,#531,.T.);
#2726=ORIENTED_EDGE('',*,*,#2500,.F.);
#2727=ORIENTED_EDGE('',*,*,#2528,.F.);
#2728=DIRECTION('',(-0.412647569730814,-0.910890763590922,0.));
#2729=VECTOR('',#2728,1.);
#2730=CARTESIAN_POINT('',(0.432728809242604,-0.196032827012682,-68.0392412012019));
#2731=LINE('',#2730,#2729);
#2732=CARTESIAN_POINT('',(-17.8611646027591,-40.5785281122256,-68.0392412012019));
#2733=VERTEX_POINT('',#2732);
#2734=EDGE_CURVE('E533',#2733,#2518,#2731,.T.);
#2735=ORIENTED_EDGE('',*,*,#2734,.F.);
#2736=DIRECTION('',(0.254051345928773,0.152696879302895,-0.955061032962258));
#2737=VECTOR('',#2736,1.);
#2738=CARTESIAN_POINT('',(-17.6616605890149,-40.4586167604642,-68.789241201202));
#2739=LINE('',#2738,#2737);
#2740=EDGE_CURVE('E528',#2733,#1303,#2739,.T.);
#2741=ORIENTED_EDGE('',*,*,#2740,.T.);
#2742=EDGE_LOOP('',(#2724,#2725,#2726,#2727,#2735,#2741));
#2743=FACE_BOUND('',#2742,.T.);
#2744=ADVANCED_FACE('F1048',(#2743),#2723,.F.);
#2745=CARTESIAN_POINT('',(-18.9703918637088,-41.5300182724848,-68.789241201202));
#2746=DIRECTION('',(-0.897052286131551,0.406378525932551,0.173648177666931));
#2747=DIRECTION('',(-0.412647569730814,-0.910890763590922,0.));
#2748=AXIS2_PLACEMENT_3D('',#2745,#2746,#2747);
#2749=PLANE('',#2748);
#2750=ORIENTED_EDGE('',*,*,#1326,.T.);
#2751=DIRECTION('',(0.412647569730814,0.910890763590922,0.));
#2752=VECTOR('',#2751,1.);
#2753=CARTESIAN_POINT('',(-0.00951733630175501,0.0043115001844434,-68.0392412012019));
#2754=LINE('',#2753,#2752);
#2755=EDGE_CURVE('E531',#2623,#1319,#2754,.T.);
#2756=ORIENTED_EDGE('',*,*,#2755,.F.);
#2757=ORIENTED_EDGE('',*,*,#2624,.F.);
#2758=ORIENTED_EDGE('',*,*,#2468,.F.);
#2759=ORIENTED_EDGE('',*,*,#715,.T.);
#2760=EDGE_LOOP('',(#2750,#2756,#2757,#2758,#2759));
#2761=FACE_BOUND('',#2760,.T.);
#2762=ADVANCED_FACE('F1495',(#2761),#2749,.F.);
#2763=CARTESIAN_POINT('',(0.,0.,-68.0392412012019));
#2764=DIRECTION('',(0.,0.,-1.));
#2765=DIRECTION('',(-1.,0.,0.));
#2766=AXIS2_PLACEMENT_3D('',#2763,#2764,#2765);
#2767=PLANE('',#2766);
#2768=DIRECTION('',(0.998012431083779,-0.0630173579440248,0.));
#2769=VECTOR('',#2768,1.);
#2770=CARTESIAN_POINT('',(-2.62299914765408,-41.5407094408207,-68.0392412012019));
#2771=LINE('',#2770,#2769);
#2772=EDGE_CURVE('E527',#1311,#2733,#2771,.T.);
#2773=ORIENTED_EDGE('',*,*,#2772,.T.);
#2774=ORIENTED_EDGE('',*,*,#2734,.T.);
#2775=ORIENTED_EDGE('',*,*,#2521,.T.);
#2776=ORIENTED_EDGE('',*,*,#2631,.T.);
#2777=ORIENTED_EDGE('',*,*,#2755,.T.);
#2778=ORIENTED_EDGE('',*,*,#1320,.F.);
#2779=EDGE_LOOP('',(#2773,#2774,#2775,#2776,#2777,#2778));
#2780=FACE_BOUND('',#2779,.T.);
#2781=ADVANCED_FACE('F1483',(#2780),#2767,.T.);
#2782=CARTESIAN_POINT('',(-17.6616605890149,-40.4586167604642,-68.789241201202));
#2783=DIRECTION('',(0.0620599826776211,0.982850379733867,0.173648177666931));
#2784=DIRECTION('',(0.,-0.173983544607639,0.984748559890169));
#2785=AXIS2_PLACEMENT_3D('',#2782,#2783,#2784);
#2786=PLANE('',#2785);
#2787=ORIENTED_EDGE('',*,*,#1312,.T.);
#2788=ORIENTED_EDGE('',*,*,#2740,.F.);
#2789=ORIENTED_EDGE('',*,*,#2772,.F.);
#2790=EDGE_LOOP('',(#2787,#2788,#2789));
#2791=FACE_BOUND('',#2790,.T.);
#2792=ADVANCED_FACE('F1478',(#2791),#2786,.F.);
#2793=CARTESIAN_POINT('',(-35.857329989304,-42.0812232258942,-68.789241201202));
#2794=DIRECTION('',(-0.984807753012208,0.,0.173648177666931));
#2795=DIRECTION('',(0.173648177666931,0.,0.984807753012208));
#2796=AXIS2_PLACEMENT_3D('',#2793,#2794,#2795);
#2797=PLANE('',#2796);
#2798=ORIENTED_EDGE('',*,*,#1869,.T.);
#2799=DIRECTION('',(0.,1.,0.));
#2800=VECTOR('',#2799,1.);
#2801=CARTESIAN_POINT('',(-35.7250847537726,0.,-68.039241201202));
#2802=LINE('',#2801,#2800);
#2803=EDGE_CURVE('E494',#2562,#1862,#2802,.T.);
#2804=ORIENTED_EDGE('',*,*,#2803,.F.);
#2805=ORIENTED_EDGE('',*,*,#2563,.F.);
#2806=ORIENTED_EDGE('',*,*,#2416,.F.);
#2807=ORIENTED_EDGE('',*,*,#496,.T.);
#2808=EDGE_LOOP('',(#2798,#2804,#2805,#2806,#2807));
#2809=FACE_BOUND('',#2808,.T.);
#2810=ADVANCED_FACE('F1165',(#2809),#2797,.F.);
#2811=CARTESIAN_POINT('',(-35.1102008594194,-42.0812232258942,-68.789241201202));
#2812=DIRECTION('',(0.984807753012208,0.,0.173648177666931));
#2813=DIRECTION('',(0.173648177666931,0.,-0.984807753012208));
#2814=AXIS2_PLACEMENT_3D('',#2811,#2812,#2813);
#2815=PLANE('',#2814);
#2816=ORIENTED_EDGE('',*,*,#1855,.T.);
#2817=ORIENTED_EDGE('',*,*,#312,.T.);
#2818=ORIENTED_EDGE('',*,*,#2448,.F.);
#2819=ORIENTED_EDGE('',*,*,#2663,.F.);
#2820=DIRECTION('',(0.,-1.,0.));
#2821=VECTOR('',#2820,1.);
#2822=CARTESIAN_POINT('',(-35.2424460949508,0.,-68.039241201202));
#2823=LINE('',#2822,#2821);
#2824=EDGE_CURVE('E51',#1854,#2655,#2823,.T.);
#2825=ORIENTED_EDGE('',*,*,#2824,.F.);
#2826=EDGE_LOOP('',(#2816,#2817,#2818,#2819,#2825));
#2827=FACE_BOUND('',#2826,.T.);
#2828=ADVANCED_FACE('F502',(#2827),#2815,.F.);
#2829=CARTESIAN_POINT('',(0.,0.,-68.039241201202));
#2830=DIRECTION('',(0.,0.,-1.));
#2831=DIRECTION('',(-1.,0.,0.));
#2832=AXIS2_PLACEMENT_3D('',#2829,#2830,#2831);
#2833=PLANE('',#2832);
#2834=ORIENTED_EDGE('',*,*,#2824,.T.);
#2835=ORIENTED_EDGE('',*,*,#2656,.T.);
#2836=ORIENTED_EDGE('',*,*,#2572,.T.);
#2837=ORIENTED_EDGE('',*,*,#2803,.T.);
#2838=ORIENTED_EDGE('',*,*,#1863,.F.);
#2839=EDGE_LOOP('',(#2834,#2835,#2836,#2837,#2838));
#2840=FACE_BOUND('',#2839,.T.);
#2841=ADVANCED_FACE('F492',(#2840),#2833,.T.);
#2842=CLOSED_SHELL('',(#169,#209,#249,#289,#782,#813,#853,#893,#966,#1024,#1082,#1094,#1106,
#1118,#1130,#1142,#1154,#1166,#1178,#1198,#1218,#1230,#1261,#1292,#1354,#1385,#1416,#1447,#1478,
#1509,#1534,#1559,#1584,#1609,#1627,#1645,#1663,#1681,#1699,#1717,#1735,#1753,#1781,#1812,#1843,
#1897,#1928,#1959,#1990,#2021,#2052,#2077,#2102,#2127,#2152,#2170,#2188,#2206,#2224,#2242,#2260,
#2278,#2296,#2324,#2363,#2402,#2428,#2454,#2480,#2506,#2549,#2592,#2610,#2643,#2676,#2694,#2706,
#2718,#2744,#2762,#2781,#2792,#2810,#2828,#2841));
#2843=MANIFOLD_SOLID_BREP('B2',#2842);
#2844=ADVANCED_BREP_SHAPE_REPRESENTATION('',(#18,#2843),#14);
#2845=SHAPE_DEFINITION_REPRESENTATION(#9,#2844);
ENDSEC;
END-ISO-10303-21;
